VERSION 5.7 ;
  NOWIREEXTENSIONATPIN ON ;
  DIVIDERCHAR "/" ;
  BUSBITCHARS "[]" ;
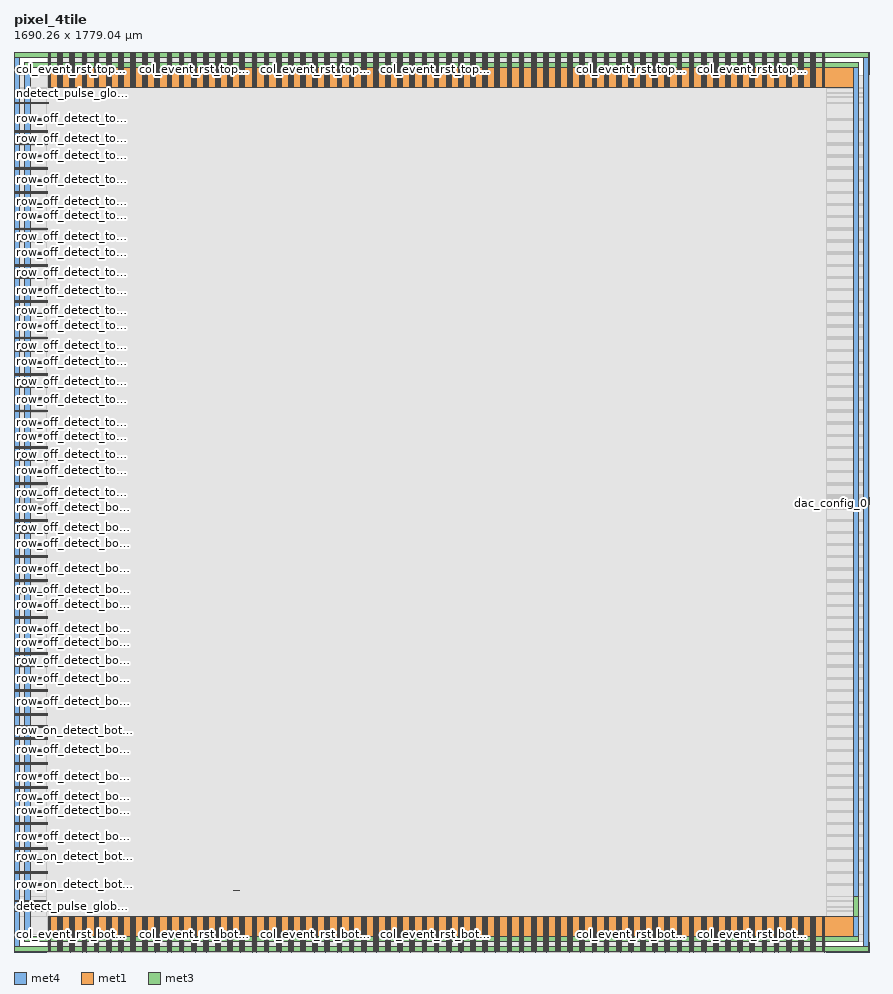
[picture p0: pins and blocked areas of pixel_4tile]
MACRO pixel_4tile
  CLASS BLOCK ;
  FOREIGN pixel_4tile ;
  ORIGIN 64.615 70.200 ;
  SIZE 1690.255 BY 1779.040 ;
  PIN array_col_top_right[5]
    ANTENNADIFFAREA 0.870000 ;
    PORT
      LAYER met4 ;
        RECT 1469.520 1638.440 1471.360 1708.840 ;
    END
  END array_col_top_right[5]
  PIN array_col_top_right[8]
    ANTENNADIFFAREA 0.870000 ;
    PORT
      LAYER met4 ;
        RECT 1438.020 1638.440 1439.860 1708.840 ;
    END
  END array_col_top_right[8]
  PIN array_col_top_right[9]
    ANTENNADIFFAREA 0.870000 ;
    PORT
      LAYER met4 ;
        RECT 1421.520 1638.440 1423.360 1708.840 ;
    END
  END array_col_top_right[9]
  PIN array_col_top_right[12]
    ANTENNADIFFAREA 0.870000 ;
    PORT
      LAYER met4 ;
        RECT 1390.020 1638.440 1391.860 1708.840 ;
    END
  END array_col_top_right[12]
  PIN array_col_top_right[13]
    ANTENNADIFFAREA 0.870000 ;
    PORT
      LAYER met4 ;
        RECT 1373.520 1638.440 1375.360 1708.840 ;
    END
  END array_col_top_right[13]
  PIN array_col_top_right[16]
    ANTENNADIFFAREA 0.870000 ;
    PORT
      LAYER met4 ;
        RECT 1342.020 1638.440 1343.860 1708.840 ;
    END
  END array_col_top_right[16]
  PIN array_col_top_right[26]
    ANTENNADIFFAREA 0.870000 ;
    PORT
      LAYER met4 ;
        RECT 1222.020 1638.440 1223.860 1708.840 ;
    END
  END array_col_top_right[26]
  PIN col_event_rst_top_right[40]
    ANTENNAGATEAREA 4.032000 ;
    PORT
      LAYER met4 ;
        RECT 1056.780 1638.440 1058.160 1708.840 ;
    END
  END col_event_rst_top_right[40]
  PIN col_event_rst_top_right[39]
    ANTENNAGATEAREA 4.032000 ;
    PORT
      LAYER met4 ;
        RECT 1059.220 1638.440 1060.600 1708.840 ;
    END
  END col_event_rst_top_right[39]
  PIN col_event_rst_top_right[38]
    ANTENNAGATEAREA 4.032000 ;
    PORT
      LAYER met4 ;
        RECT 1080.780 1638.440 1082.160 1708.840 ;
    END
  END col_event_rst_top_right[38]
  PIN col_event_rst_top_right[37]
    ANTENNAGATEAREA 4.032000 ;
    PORT
      LAYER met4 ;
        RECT 1083.220 1638.440 1084.600 1708.840 ;
    END
  END col_event_rst_top_right[37]
  PIN col_event_rst_top_right[36]
    ANTENNAGATEAREA 4.032000 ;
    PORT
      LAYER met4 ;
        RECT 1104.780 1638.440 1106.160 1708.840 ;
    END
  END col_event_rst_top_right[36]
  PIN col_event_rst_top_right[35]
    ANTENNAGATEAREA 4.032000 ;
    PORT
      LAYER met4 ;
        RECT 1107.220 1638.440 1108.600 1708.840 ;
    END
  END col_event_rst_top_right[35]
  PIN col_event_rst_top_right[34]
    ANTENNAGATEAREA 4.032000 ;
    PORT
      LAYER met4 ;
        RECT 1128.780 1638.440 1130.160 1708.840 ;
    END
  END col_event_rst_top_right[34]
  PIN col_event_rst_top_right[33]
    ANTENNAGATEAREA 4.032000 ;
    PORT
      LAYER met4 ;
        RECT 1131.220 1638.440 1132.600 1708.840 ;
    END
  END col_event_rst_top_right[33]
  PIN col_event_rst_top_right[27]
    ANTENNAGATEAREA 4.032000 ;
    PORT
      LAYER met4 ;
        RECT 1203.220 1638.440 1204.600 1708.840 ;
    END
  END col_event_rst_top_right[27]
  PIN col_event_rst_top_right[32]
    ANTENNAGATEAREA 4.032000 ;
    PORT
      LAYER met4 ;
        RECT 1152.780 1638.440 1154.160 1708.840 ;
    END
  END col_event_rst_top_right[32]
  PIN col_event_rst_top_right[26]
    ANTENNAGATEAREA 4.032000 ;
    PORT
      LAYER met4 ;
        RECT 1224.780 1638.440 1226.160 1708.840 ;
    END
  END col_event_rst_top_right[26]
  PIN col_event_rst_top_right[25]
    ANTENNAGATEAREA 4.032000 ;
    PORT
      LAYER met4 ;
        RECT 1227.220 1638.440 1228.600 1708.840 ;
    END
  END col_event_rst_top_right[25]
  PIN col_event_rst_top_right[24]
    ANTENNAGATEAREA 4.032000 ;
    PORT
      LAYER met4 ;
        RECT 1248.780 1638.440 1250.160 1708.840 ;
    END
  END col_event_rst_top_right[24]
  PIN col_event_rst_top_right[23]
    ANTENNAGATEAREA 4.032000 ;
    PORT
      LAYER met4 ;
        RECT 1251.220 1638.440 1252.600 1708.840 ;
    END
  END col_event_rst_top_right[23]
  PIN col_event_rst_top_right[22]
    ANTENNAGATEAREA 4.032000 ;
    PORT
      LAYER met4 ;
        RECT 1272.780 1638.440 1274.160 1708.840 ;
    END
  END col_event_rst_top_right[22]
  PIN col_event_rst_top_right[21]
    ANTENNAGATEAREA 4.032000 ;
    PORT
      LAYER met4 ;
        RECT 1275.220 1638.440 1276.600 1708.840 ;
    END
  END col_event_rst_top_right[21]
  PIN col_event_rst_top_right[20]
    ANTENNAGATEAREA 4.032000 ;
    PORT
      LAYER met4 ;
        RECT 1296.780 1638.440 1298.160 1708.840 ;
    END
  END col_event_rst_top_right[20]
  PIN col_event_rst_top_right[19]
    ANTENNAGATEAREA 4.032000 ;
    PORT
      LAYER met4 ;
        RECT 1299.220 1638.440 1300.600 1708.840 ;
    END
  END col_event_rst_top_right[19]
  PIN col_event_rst_top_right[18]
    ANTENNAGATEAREA 4.032000 ;
    PORT
      LAYER met4 ;
        RECT 1320.780 1638.440 1322.160 1708.840 ;
    END
  END col_event_rst_top_right[18]
  PIN col_event_rst_top_right[17]
    ANTENNAGATEAREA 4.032000 ;
    PORT
      LAYER met4 ;
        RECT 1323.220 1638.440 1324.600 1708.840 ;
    END
  END col_event_rst_top_right[17]
  PIN col_event_rst_top_right[16]
    ANTENNAGATEAREA 4.032000 ;
    PORT
      LAYER met4 ;
        RECT 1344.780 1638.440 1346.160 1708.840 ;
    END
  END col_event_rst_top_right[16]
  PIN col_event_rst_top_right[15]
    ANTENNAGATEAREA 4.032000 ;
    PORT
      LAYER met4 ;
        RECT 1347.220 1638.440 1348.600 1708.840 ;
    END
  END col_event_rst_top_right[15]
  PIN col_event_rst_top_right[14]
    ANTENNAGATEAREA 4.032000 ;
    PORT
      LAYER met4 ;
        RECT 1368.780 1638.440 1370.160 1708.840 ;
    END
  END col_event_rst_top_right[14]
  PIN col_event_rst_top_right[13]
    ANTENNAGATEAREA 4.032000 ;
    PORT
      LAYER met4 ;
        RECT 1371.220 1638.440 1372.600 1708.840 ;
    END
  END col_event_rst_top_right[13]
  PIN col_event_rst_top_right[12]
    ANTENNAGATEAREA 4.032000 ;
    PORT
      LAYER met4 ;
        RECT 1392.780 1638.440 1394.160 1708.840 ;
    END
  END col_event_rst_top_right[12]
  PIN col_event_rst_top_right[11]
    ANTENNAGATEAREA 4.032000 ;
    PORT
      LAYER met4 ;
        RECT 1395.220 1638.440 1396.600 1708.840 ;
    END
  END col_event_rst_top_right[11]
  PIN col_event_rst_top_right[10]
    ANTENNAGATEAREA 4.032000 ;
    PORT
      LAYER met4 ;
        RECT 1416.780 1638.440 1418.160 1708.840 ;
    END
  END col_event_rst_top_right[10]
  PIN col_event_rst_top_right[9]
    ANTENNAGATEAREA 4.032000 ;
    PORT
      LAYER met4 ;
        RECT 1419.220 1638.440 1420.600 1708.840 ;
    END
  END col_event_rst_top_right[9]
  PIN col_event_rst_top_right[8]
    ANTENNAGATEAREA 4.032000 ;
    PORT
      LAYER met4 ;
        RECT 1440.780 1638.440 1442.160 1708.840 ;
    END
  END col_event_rst_top_right[8]
  PIN col_event_rst_top_right[7]
    ANTENNAGATEAREA 4.032000 ;
    PORT
      LAYER met4 ;
        RECT 1443.220 1638.440 1444.600 1708.840 ;
    END
  END col_event_rst_top_right[7]
  PIN col_event_rst_top_right[6]
    ANTENNAGATEAREA 4.032000 ;
    PORT
      LAYER met4 ;
        RECT 1464.780 1638.440 1466.160 1708.840 ;
    END
  END col_event_rst_top_right[6]
  PIN col_event_rst_top_right[5]
    ANTENNAGATEAREA 4.032000 ;
    PORT
      LAYER met4 ;
        RECT 1467.220 1638.440 1468.600 1708.840 ;
    END
  END col_event_rst_top_right[5]
  PIN col_event_rst_top_right[4]
    ANTENNAGATEAREA 4.032000 ;
    PORT
      LAYER met4 ;
        RECT 1488.780 1638.440 1490.160 1708.840 ;
    END
  END col_event_rst_top_right[4]
  PIN col_event_rst_top_right[3]
    ANTENNAGATEAREA 4.032000 ;
    PORT
      LAYER met4 ;
        RECT 1491.220 1638.440 1492.600 1708.840 ;
    END
  END col_event_rst_top_right[3]
  PIN col_event_rst_top_right[2]
    ANTENNAGATEAREA 4.032000 ;
    PORT
      LAYER met4 ;
        RECT 1512.780 1638.440 1514.160 1708.840 ;
    END
  END col_event_rst_top_right[2]
  PIN col_event_rst_top_right[1]
    ANTENNAGATEAREA 4.032000 ;
    PORT
      LAYER met4 ;
        RECT 1515.220 1638.440 1516.600 1708.840 ;
    END
  END col_event_rst_top_right[1]
  PIN col_event_rst_top_right[0]
    ANTENNAGATEAREA 4.032000 ;
    PORT
      LAYER met4 ;
        RECT 1536.780 1638.440 1538.160 1708.840 ;
    END
  END col_event_rst_top_right[0]
  PIN col_event_rst_bot_right[63]
    ANTENNAGATEAREA 4.032000 ;
    PORT
      LAYER met4 ;
        RECT 771.220 -70.040 772.600 0.375 ;
    END
  END col_event_rst_bot_right[63]
  PIN col_event_rst_bot_right[62]
    ANTENNAGATEAREA 4.032000 ;
    PORT
      LAYER met4 ;
        RECT 792.780 -70.040 794.160 0.375 ;
    END
  END col_event_rst_bot_right[62]
  PIN col_event_rst_bot_right[61]
    ANTENNAGATEAREA 4.032000 ;
    PORT
      LAYER met4 ;
        RECT 795.220 -70.040 796.600 0.375 ;
    END
  END col_event_rst_bot_right[61]
  PIN col_event_rst_bot_right[60]
    ANTENNAGATEAREA 4.032000 ;
    PORT
      LAYER met4 ;
        RECT 817.250 -70.040 818.630 0.375 ;
    END
  END col_event_rst_bot_right[60]
  PIN col_event_rst_bot_right[59]
    ANTENNAGATEAREA 4.032000 ;
    PORT
      LAYER met4 ;
        RECT 819.220 -70.040 820.600 0.375 ;
    END
  END col_event_rst_bot_right[59]
  PIN col_event_rst_bot_right[58]
    ANTENNAGATEAREA 4.032000 ;
    PORT
      LAYER met4 ;
        RECT 840.780 -70.040 842.160 0.375 ;
    END
  END col_event_rst_bot_right[58]
  PIN col_event_rst_bot_right[57]
    ANTENNAGATEAREA 4.032000 ;
    PORT
      LAYER met4 ;
        RECT 843.220 -70.040 844.600 0.375 ;
    END
  END col_event_rst_bot_right[57]
  PIN col_event_rst_bot_right[56]
    ANTENNAGATEAREA 4.032000 ;
    PORT
      LAYER met4 ;
        RECT 864.780 -70.040 866.160 0.375 ;
    END
  END col_event_rst_bot_right[56]
  PIN col_event_rst_bot_right[55]
    ANTENNAGATEAREA 4.032000 ;
    PORT
      LAYER met4 ;
        RECT 867.220 -70.040 868.600 0.375 ;
    END
  END col_event_rst_bot_right[55]
  PIN col_event_rst_bot_right[54]
    ANTENNAGATEAREA 4.032000 ;
    PORT
      LAYER met4 ;
        RECT 888.780 -70.040 890.160 0.375 ;
    END
  END col_event_rst_bot_right[54]
  PIN col_event_rst_bot_right[53]
    ANTENNAGATEAREA 4.032000 ;
    PORT
      LAYER met4 ;
        RECT 891.220 -70.040 892.600 0.375 ;
    END
  END col_event_rst_bot_right[53]
  PIN col_event_rst_bot_right[52]
    ANTENNAGATEAREA 4.032000 ;
    PORT
      LAYER met4 ;
        RECT 912.780 -70.040 914.160 0.375 ;
    END
  END col_event_rst_bot_right[52]
  PIN col_event_rst_bot_right[51]
    ANTENNAGATEAREA 4.032000 ;
    PORT
      LAYER met4 ;
        RECT 915.220 -70.040 916.600 0.375 ;
    END
  END col_event_rst_bot_right[51]
  PIN col_event_rst_bot_right[50]
    ANTENNAGATEAREA 4.032000 ;
    PORT
      LAYER met4 ;
        RECT 936.780 -70.040 938.160 0.375 ;
    END
  END col_event_rst_bot_right[50]
  PIN col_event_rst_bot_right[49]
    ANTENNAGATEAREA 4.032000 ;
    PORT
      LAYER met4 ;
        RECT 939.220 -70.040 940.600 0.375 ;
    END
  END col_event_rst_bot_right[49]
  PIN col_event_rst_bot_right[48]
    ANTENNAGATEAREA 4.032000 ;
    PORT
      LAYER met4 ;
        RECT 960.780 -70.040 962.160 0.375 ;
    END
  END col_event_rst_bot_right[48]
  PIN col_event_rst_bot_right[47]
    ANTENNAGATEAREA 4.032000 ;
    PORT
      LAYER met4 ;
        RECT 963.220 -70.040 964.600 0.375 ;
    END
  END col_event_rst_bot_right[47]
  PIN col_event_rst_bot_right[46]
    ANTENNAGATEAREA 4.032000 ;
    PORT
      LAYER met4 ;
        RECT 984.780 -70.040 986.160 0.375 ;
    END
  END col_event_rst_bot_right[46]
  PIN col_event_rst_bot_right[45]
    ANTENNAGATEAREA 4.032000 ;
    PORT
      LAYER met4 ;
        RECT 987.220 -70.040 988.600 0.375 ;
    END
  END col_event_rst_bot_right[45]
  PIN col_event_rst_bot_right[44]
    ANTENNAGATEAREA 4.032000 ;
    PORT
      LAYER met4 ;
        RECT 1008.780 -70.040 1010.160 0.375 ;
    END
  END col_event_rst_bot_right[44]
  PIN col_event_rst_bot_right[43]
    ANTENNAGATEAREA 4.032000 ;
    PORT
      LAYER met4 ;
        RECT 1011.220 -70.040 1012.600 0.375 ;
    END
  END col_event_rst_bot_right[43]
  PIN col_event_rst_bot_right[42]
    ANTENNAGATEAREA 4.032000 ;
    PORT
      LAYER met4 ;
        RECT 1032.780 -70.040 1034.160 0.375 ;
    END
  END col_event_rst_bot_right[42]
  PIN col_event_rst_bot_right[41]
    ANTENNAGATEAREA 4.032000 ;
    PORT
      LAYER met4 ;
        RECT 1035.220 -70.040 1036.600 0.375 ;
    END
  END col_event_rst_bot_right[41]
  PIN col_event_rst_bot_right[40]
    ANTENNAGATEAREA 4.032000 ;
    PORT
      LAYER met4 ;
        RECT 1056.780 -70.040 1058.160 0.375 ;
    END
  END col_event_rst_bot_right[40]
  PIN col_event_rst_bot_right[39]
    ANTENNAGATEAREA 4.032000 ;
    PORT
      LAYER met4 ;
        RECT 1059.220 -70.040 1060.600 0.375 ;
    END
  END col_event_rst_bot_right[39]
  PIN col_event_rst_bot_right[38]
    ANTENNAGATEAREA 4.032000 ;
    PORT
      LAYER met4 ;
        RECT 1080.780 -70.040 1082.160 0.375 ;
    END
  END col_event_rst_bot_right[38]
  PIN col_event_rst_bot_right[37]
    ANTENNAGATEAREA 4.032000 ;
    PORT
      LAYER met4 ;
        RECT 1083.220 -70.040 1084.600 0.375 ;
    END
  END col_event_rst_bot_right[37]
  PIN col_event_rst_bot_right[36]
    ANTENNAGATEAREA 4.032000 ;
    PORT
      LAYER met4 ;
        RECT 1104.780 -70.040 1106.160 0.375 ;
    END
  END col_event_rst_bot_right[36]
  PIN col_event_rst_bot_right[35]
    ANTENNAGATEAREA 4.032000 ;
    PORT
      LAYER met4 ;
        RECT 1107.220 -70.040 1108.600 0.375 ;
    END
  END col_event_rst_bot_right[35]
  PIN col_event_rst_bot_right[34]
    ANTENNAGATEAREA 4.032000 ;
    PORT
      LAYER met4 ;
        RECT 1128.780 -70.040 1130.160 0.375 ;
    END
  END col_event_rst_bot_right[34]
  PIN col_event_rst_bot_right[33]
    ANTENNAGATEAREA 4.032000 ;
    PORT
      LAYER met4 ;
        RECT 1131.220 -70.040 1132.600 0.375 ;
    END
  END col_event_rst_bot_right[33]
  PIN col_event_rst_bot_right[32]
    ANTENNAGATEAREA 4.032000 ;
    PORT
      LAYER met4 ;
        RECT 1152.780 -70.040 1154.160 0.375 ;
    END
  END col_event_rst_bot_right[32]
  PIN col_event_rst_bot_right[31]
    ANTENNAGATEAREA 4.032000 ;
    PORT
      LAYER met4 ;
        RECT 1155.220 -70.040 1156.600 0.375 ;
    END
  END col_event_rst_bot_right[31]
  PIN col_event_rst_bot_right[30]
    ANTENNAGATEAREA 4.032000 ;
    PORT
      LAYER met4 ;
        RECT 1176.780 -70.040 1178.160 0.375 ;
    END
  END col_event_rst_bot_right[30]
  PIN col_event_rst_bot_right[29]
    ANTENNAGATEAREA 4.032000 ;
    PORT
      LAYER met4 ;
        RECT 1179.220 -70.040 1180.600 0.375 ;
    END
  END col_event_rst_bot_right[29]
  PIN col_event_rst_bot_right[28]
    ANTENNAGATEAREA 4.032000 ;
    PORT
      LAYER met4 ;
        RECT 1200.780 -70.040 1202.160 0.375 ;
    END
  END col_event_rst_bot_right[28]
  PIN col_event_rst_bot_right[27]
    ANTENNAGATEAREA 4.032000 ;
    PORT
      LAYER met4 ;
        RECT 1203.220 -70.040 1204.600 0.375 ;
    END
  END col_event_rst_bot_right[27]
  PIN col_event_rst_bot_right[26]
    ANTENNAGATEAREA 4.032000 ;
    PORT
      LAYER met4 ;
        RECT 1224.780 -70.040 1226.160 0.375 ;
    END
  END col_event_rst_bot_right[26]
  PIN col_event_rst_bot_right[25]
    ANTENNAGATEAREA 4.032000 ;
    PORT
      LAYER met4 ;
        RECT 1227.220 -70.040 1228.600 0.375 ;
    END
  END col_event_rst_bot_right[25]
  PIN col_event_rst_bot_right[24]
    ANTENNAGATEAREA 4.032000 ;
    PORT
      LAYER met4 ;
        RECT 1248.780 -70.040 1250.160 0.375 ;
    END
  END col_event_rst_bot_right[24]
  PIN col_event_rst_bot_right[23]
    ANTENNAGATEAREA 4.032000 ;
    PORT
      LAYER met4 ;
        RECT 1251.220 -70.040 1252.600 0.375 ;
    END
  END col_event_rst_bot_right[23]
  PIN col_event_rst_bot_right[22]
    ANTENNAGATEAREA 4.032000 ;
    PORT
      LAYER met4 ;
        RECT 1272.780 -70.040 1274.160 0.375 ;
    END
  END col_event_rst_bot_right[22]
  PIN col_event_rst_bot_right[21]
    ANTENNAGATEAREA 4.032000 ;
    PORT
      LAYER met4 ;
        RECT 1275.220 -70.040 1276.600 0.375 ;
    END
  END col_event_rst_bot_right[21]
  PIN col_event_rst_bot_right[20]
    ANTENNAGATEAREA 4.032000 ;
    PORT
      LAYER met4 ;
        RECT 1296.780 -70.040 1298.160 0.375 ;
    END
  END col_event_rst_bot_right[20]
  PIN col_event_rst_bot_right[19]
    ANTENNAGATEAREA 4.032000 ;
    PORT
      LAYER met4 ;
        RECT 1299.220 -70.040 1300.600 0.375 ;
    END
  END col_event_rst_bot_right[19]
  PIN col_event_rst_bot_right[18]
    ANTENNAGATEAREA 4.032000 ;
    PORT
      LAYER met4 ;
        RECT 1320.780 -70.040 1322.160 0.375 ;
    END
  END col_event_rst_bot_right[18]
  PIN col_event_rst_bot_right[17]
    ANTENNAGATEAREA 4.032000 ;
    PORT
      LAYER met4 ;
        RECT 1323.220 -70.040 1324.600 0.375 ;
    END
  END col_event_rst_bot_right[17]
  PIN col_event_rst_bot_right[16]
    ANTENNAGATEAREA 4.032000 ;
    PORT
      LAYER met4 ;
        RECT 1344.780 -70.040 1346.160 0.375 ;
    END
  END col_event_rst_bot_right[16]
  PIN col_event_rst_bot_right[15]
    ANTENNAGATEAREA 4.032000 ;
    PORT
      LAYER met4 ;
        RECT 1347.220 -70.040 1348.600 0.375 ;
    END
  END col_event_rst_bot_right[15]
  PIN col_event_rst_bot_right[14]
    ANTENNAGATEAREA 4.032000 ;
    PORT
      LAYER met4 ;
        RECT 1368.780 -70.040 1370.160 0.375 ;
    END
  END col_event_rst_bot_right[14]
  PIN col_event_rst_bot_right[13]
    ANTENNAGATEAREA 4.032000 ;
    PORT
      LAYER met4 ;
        RECT 1371.220 -70.040 1372.600 0.375 ;
    END
  END col_event_rst_bot_right[13]
  PIN col_event_rst_bot_right[12]
    ANTENNAGATEAREA 4.032000 ;
    PORT
      LAYER met4 ;
        RECT 1392.780 -70.040 1394.160 0.375 ;
    END
  END col_event_rst_bot_right[12]
  PIN col_event_rst_bot_right[11]
    ANTENNAGATEAREA 4.032000 ;
    PORT
      LAYER met4 ;
        RECT 1395.220 -70.040 1396.600 0.375 ;
    END
  END col_event_rst_bot_right[11]
  PIN col_event_rst_bot_right[10]
    ANTENNAGATEAREA 4.032000 ;
    PORT
      LAYER met4 ;
        RECT 1416.780 -70.040 1418.160 0.375 ;
    END
  END col_event_rst_bot_right[10]
  PIN col_event_rst_bot_right[9]
    ANTENNAGATEAREA 4.032000 ;
    PORT
      LAYER met4 ;
        RECT 1419.220 -70.040 1420.600 0.375 ;
    END
  END col_event_rst_bot_right[9]
  PIN col_event_rst_bot_right[8]
    ANTENNAGATEAREA 4.032000 ;
    PORT
      LAYER met4 ;
        RECT 1440.780 -70.040 1442.160 0.375 ;
    END
  END col_event_rst_bot_right[8]
  PIN col_event_rst_bot_right[7]
    ANTENNAGATEAREA 4.032000 ;
    PORT
      LAYER met4 ;
        RECT 1443.220 -70.040 1444.600 0.375 ;
    END
  END col_event_rst_bot_right[7]
  PIN col_event_rst_bot_right[6]
    ANTENNAGATEAREA 4.032000 ;
    PORT
      LAYER met4 ;
        RECT 1464.780 -70.040 1466.160 0.375 ;
    END
  END col_event_rst_bot_right[6]
  PIN col_event_rst_bot_right[5]
    ANTENNAGATEAREA 4.032000 ;
    PORT
      LAYER met4 ;
        RECT 1467.220 -70.040 1468.600 0.375 ;
    END
  END col_event_rst_bot_right[5]
  PIN col_event_rst_bot_right[4]
    ANTENNAGATEAREA 4.032000 ;
    PORT
      LAYER met4 ;
        RECT 1488.780 -70.040 1490.160 0.375 ;
    END
  END col_event_rst_bot_right[4]
  PIN col_event_rst_bot_right[3]
    ANTENNAGATEAREA 4.032000 ;
    PORT
      LAYER met4 ;
        RECT 1491.220 -70.040 1492.600 0.375 ;
    END
  END col_event_rst_bot_right[3]
  PIN col_event_rst_bot_right[2]
    ANTENNAGATEAREA 4.032000 ;
    PORT
      LAYER met4 ;
        RECT 1512.780 -70.040 1514.160 0.375 ;
    END
  END col_event_rst_bot_right[2]
  PIN col_event_rst_bot_right[1]
    ANTENNAGATEAREA 4.032000 ;
    PORT
      LAYER met4 ;
        RECT 1515.220 -70.040 1516.600 0.375 ;
    END
  END col_event_rst_bot_right[1]
  PIN col_event_rst_bot_right[0]
    ANTENNAGATEAREA 4.032000 ;
    PORT
      LAYER met4 ;
        RECT 1536.780 -70.040 1538.160 0.375 ;
    END
  END col_event_rst_bot_right[0]
  PIN col_event_rst_bot_left[63]
    ANTENNAGATEAREA 4.032000 ;
    PORT
      LAYER met4 ;
        RECT 3.220 -70.040 4.600 0.375 ;
    END
  END col_event_rst_bot_left[63]
  PIN col_event_rst_bot_left[62]
    ANTENNAGATEAREA 4.032000 ;
    PORT
      LAYER met4 ;
        RECT 24.780 -70.040 26.160 0.375 ;
    END
  END col_event_rst_bot_left[62]
  PIN col_event_rst_bot_left[61]
    ANTENNAGATEAREA 4.032000 ;
    PORT
      LAYER met4 ;
        RECT 27.220 -70.040 28.600 0.375 ;
    END
  END col_event_rst_bot_left[61]
  PIN col_event_rst_bot_left[60]
    ANTENNAGATEAREA 4.032000 ;
    PORT
      LAYER met4 ;
        RECT 48.780 -70.040 50.160 0.375 ;
    END
  END col_event_rst_bot_left[60]
  PIN col_event_rst_bot_left[59]
    ANTENNAGATEAREA 4.032000 ;
    PORT
      LAYER met4 ;
        RECT 51.220 -70.040 52.600 0.375 ;
    END
  END col_event_rst_bot_left[59]
  PIN col_event_rst_bot_left[58]
    ANTENNAGATEAREA 4.032000 ;
    PORT
      LAYER met4 ;
        RECT 72.780 -70.040 74.160 0.375 ;
    END
  END col_event_rst_bot_left[58]
  PIN col_event_rst_bot_left[57]
    ANTENNAGATEAREA 4.032000 ;
    PORT
      LAYER met4 ;
        RECT 75.220 -70.040 76.600 0.375 ;
    END
  END col_event_rst_bot_left[57]
  PIN col_event_rst_bot_left[56]
    ANTENNAGATEAREA 4.032000 ;
    PORT
      LAYER met4 ;
        RECT 96.780 -70.040 98.160 0.375 ;
    END
  END col_event_rst_bot_left[56]
  PIN col_event_rst_bot_left[55]
    ANTENNAGATEAREA 4.032000 ;
    PORT
      LAYER met4 ;
        RECT 99.220 -70.040 100.600 0.375 ;
    END
  END col_event_rst_bot_left[55]
  PIN col_event_rst_bot_left[54]
    ANTENNAGATEAREA 4.032000 ;
    PORT
      LAYER met4 ;
        RECT 120.780 -70.040 122.160 0.375 ;
    END
  END col_event_rst_bot_left[54]
  PIN col_event_rst_bot_left[53]
    ANTENNAGATEAREA 4.032000 ;
    PORT
      LAYER met4 ;
        RECT 123.220 -70.040 124.600 0.375 ;
    END
  END col_event_rst_bot_left[53]
  PIN col_event_rst_bot_left[52]
    ANTENNAGATEAREA 4.032000 ;
    PORT
      LAYER met4 ;
        RECT 144.780 -70.040 146.160 0.375 ;
    END
  END col_event_rst_bot_left[52]
  PIN col_event_rst_bot_left[51]
    ANTENNAGATEAREA 4.032000 ;
    PORT
      LAYER met4 ;
        RECT 147.220 -70.040 148.600 0.375 ;
    END
  END col_event_rst_bot_left[51]
  PIN col_event_rst_bot_left[50]
    ANTENNAGATEAREA 4.032000 ;
    PORT
      LAYER met4 ;
        RECT 168.780 -70.040 170.160 0.375 ;
    END
  END col_event_rst_bot_left[50]
  PIN col_event_rst_bot_left[49]
    ANTENNAGATEAREA 4.032000 ;
    PORT
      LAYER met4 ;
        RECT 171.220 -70.040 172.600 0.375 ;
    END
  END col_event_rst_bot_left[49]
  PIN col_event_rst_bot_left[48]
    ANTENNAGATEAREA 4.032000 ;
    PORT
      LAYER met4 ;
        RECT 192.780 -70.040 194.160 0.375 ;
    END
  END col_event_rst_bot_left[48]
  PIN col_event_rst_bot_left[47]
    ANTENNAGATEAREA 4.032000 ;
    PORT
      LAYER met4 ;
        RECT 195.220 -70.040 196.600 0.375 ;
    END
  END col_event_rst_bot_left[47]
  PIN col_event_rst_bot_left[46]
    ANTENNAGATEAREA 4.032000 ;
    PORT
      LAYER met4 ;
        RECT 216.780 -70.040 218.160 0.375 ;
    END
  END col_event_rst_bot_left[46]
  PIN col_event_rst_bot_left[45]
    ANTENNAGATEAREA 4.032000 ;
    PORT
      LAYER met4 ;
        RECT 219.220 -70.040 220.600 0.375 ;
    END
  END col_event_rst_bot_left[45]
  PIN col_event_rst_bot_left[44]
    ANTENNAGATEAREA 4.032000 ;
    PORT
      LAYER met4 ;
        RECT 240.780 -70.040 242.160 0.375 ;
    END
  END col_event_rst_bot_left[44]
  PIN col_event_rst_bot_left[43]
    ANTENNAGATEAREA 4.032000 ;
    PORT
      LAYER met4 ;
        RECT 243.220 -70.040 244.600 0.375 ;
    END
  END col_event_rst_bot_left[43]
  PIN col_event_rst_bot_left[42]
    ANTENNAGATEAREA 4.032000 ;
    PORT
      LAYER met4 ;
        RECT 264.780 -70.040 266.160 0.375 ;
    END
  END col_event_rst_bot_left[42]
  PIN col_event_rst_bot_left[41]
    ANTENNAGATEAREA 4.032000 ;
    PORT
      LAYER met4 ;
        RECT 267.220 -70.040 268.600 0.375 ;
    END
  END col_event_rst_bot_left[41]
  PIN col_event_rst_bot_left[40]
    ANTENNAGATEAREA 4.032000 ;
    PORT
      LAYER met4 ;
        RECT 288.780 -70.040 290.160 0.375 ;
    END
  END col_event_rst_bot_left[40]
  PIN col_event_rst_bot_left[39]
    ANTENNAGATEAREA 4.032000 ;
    PORT
      LAYER met4 ;
        RECT 291.220 -70.040 292.600 0.375 ;
    END
  END col_event_rst_bot_left[39]
  PIN col_event_rst_bot_left[38]
    ANTENNAGATEAREA 4.032000 ;
    PORT
      LAYER met4 ;
        RECT 312.780 -70.040 314.160 0.375 ;
    END
  END col_event_rst_bot_left[38]
  PIN col_event_rst_bot_left[37]
    ANTENNAGATEAREA 4.032000 ;
    PORT
      LAYER met4 ;
        RECT 315.220 -70.040 316.600 0.375 ;
    END
  END col_event_rst_bot_left[37]
  PIN col_event_rst_bot_left[36]
    ANTENNAGATEAREA 4.032000 ;
    PORT
      LAYER met4 ;
        RECT 336.780 -70.040 338.160 0.375 ;
    END
  END col_event_rst_bot_left[36]
  PIN col_event_rst_bot_left[35]
    ANTENNAGATEAREA 4.032000 ;
    PORT
      LAYER met4 ;
        RECT 339.220 -70.040 340.600 0.375 ;
    END
  END col_event_rst_bot_left[35]
  PIN col_event_rst_bot_left[34]
    ANTENNAGATEAREA 4.032000 ;
    PORT
      LAYER met4 ;
        RECT 360.780 -70.040 362.160 0.375 ;
    END
  END col_event_rst_bot_left[34]
  PIN col_event_rst_bot_left[33]
    ANTENNAGATEAREA 4.032000 ;
    PORT
      LAYER met4 ;
        RECT 363.220 -70.040 364.600 0.375 ;
    END
  END col_event_rst_bot_left[33]
  PIN col_event_rst_bot_left[32]
    ANTENNAGATEAREA 4.032000 ;
    PORT
      LAYER met4 ;
        RECT 384.780 -70.040 386.160 0.375 ;
    END
  END col_event_rst_bot_left[32]
  PIN col_event_rst_bot_left[31]
    ANTENNAGATEAREA 4.032000 ;
    PORT
      LAYER met4 ;
        RECT 387.220 -70.040 388.600 0.375 ;
    END
  END col_event_rst_bot_left[31]
  PIN col_event_rst_bot_left[30]
    ANTENNAGATEAREA 4.032000 ;
    PORT
      LAYER met4 ;
        RECT 408.780 -70.040 410.160 0.375 ;
    END
  END col_event_rst_bot_left[30]
  PIN col_event_rst_bot_left[29]
    ANTENNAGATEAREA 4.032000 ;
    PORT
      LAYER met4 ;
        RECT 411.220 -70.040 412.600 0.375 ;
    END
  END col_event_rst_bot_left[29]
  PIN col_event_rst_bot_left[28]
    ANTENNAGATEAREA 4.032000 ;
    PORT
      LAYER met4 ;
        RECT 432.780 -70.040 434.160 0.375 ;
    END
  END col_event_rst_bot_left[28]
  PIN col_event_rst_bot_left[27]
    ANTENNAGATEAREA 4.032000 ;
    PORT
      LAYER met4 ;
        RECT 435.220 -70.040 436.600 0.375 ;
    END
  END col_event_rst_bot_left[27]
  PIN col_event_rst_bot_left[26]
    ANTENNAGATEAREA 4.032000 ;
    PORT
      LAYER met4 ;
        RECT 456.780 -70.040 458.160 0.375 ;
    END
  END col_event_rst_bot_left[26]
  PIN col_event_rst_bot_left[25]
    ANTENNAGATEAREA 4.032000 ;
    PORT
      LAYER met4 ;
        RECT 459.220 -70.040 460.600 0.375 ;
    END
  END col_event_rst_bot_left[25]
  PIN col_event_rst_bot_left[24]
    ANTENNAGATEAREA 4.032000 ;
    PORT
      LAYER met4 ;
        RECT 480.780 -70.040 482.160 0.375 ;
    END
  END col_event_rst_bot_left[24]
  PIN col_event_rst_bot_left[23]
    ANTENNAGATEAREA 4.032000 ;
    PORT
      LAYER met4 ;
        RECT 483.220 -70.040 484.600 0.375 ;
    END
  END col_event_rst_bot_left[23]
  PIN col_event_rst_bot_left[22]
    ANTENNAGATEAREA 4.032000 ;
    PORT
      LAYER met4 ;
        RECT 504.780 -70.040 506.160 0.375 ;
    END
  END col_event_rst_bot_left[22]
  PIN col_event_rst_bot_left[21]
    ANTENNAGATEAREA 4.032000 ;
    PORT
      LAYER met4 ;
        RECT 507.220 -70.040 508.600 0.375 ;
    END
  END col_event_rst_bot_left[21]
  PIN col_event_rst_bot_left[20]
    ANTENNAGATEAREA 4.032000 ;
    PORT
      LAYER met4 ;
        RECT 528.780 -70.040 530.160 0.375 ;
    END
  END col_event_rst_bot_left[20]
  PIN col_event_rst_bot_left[19]
    ANTENNAGATEAREA 4.032000 ;
    PORT
      LAYER met4 ;
        RECT 531.220 -70.040 532.600 0.375 ;
    END
  END col_event_rst_bot_left[19]
  PIN col_event_rst_bot_left[18]
    ANTENNAGATEAREA 4.032000 ;
    PORT
      LAYER met4 ;
        RECT 552.780 -70.040 554.160 0.375 ;
    END
  END col_event_rst_bot_left[18]
  PIN col_event_rst_bot_left[17]
    ANTENNAGATEAREA 4.032000 ;
    PORT
      LAYER met4 ;
        RECT 555.220 -70.040 556.600 0.375 ;
    END
  END col_event_rst_bot_left[17]
  PIN col_event_rst_bot_left[16]
    ANTENNAGATEAREA 4.032000 ;
    PORT
      LAYER met4 ;
        RECT 576.780 -70.040 578.160 0.375 ;
    END
  END col_event_rst_bot_left[16]
  PIN col_event_rst_bot_left[15]
    ANTENNAGATEAREA 4.032000 ;
    PORT
      LAYER met4 ;
        RECT 579.220 -70.040 580.600 0.375 ;
    END
  END col_event_rst_bot_left[15]
  PIN col_event_rst_bot_left[14]
    ANTENNAGATEAREA 4.032000 ;
    PORT
      LAYER met4 ;
        RECT 600.780 -70.040 602.160 0.375 ;
    END
  END col_event_rst_bot_left[14]
  PIN col_event_rst_bot_left[13]
    ANTENNAGATEAREA 4.032000 ;
    PORT
      LAYER met4 ;
        RECT 603.220 -70.040 604.600 0.375 ;
    END
  END col_event_rst_bot_left[13]
  PIN col_event_rst_bot_left[12]
    ANTENNAGATEAREA 4.032000 ;
    PORT
      LAYER met4 ;
        RECT 624.780 -70.040 626.160 0.375 ;
    END
  END col_event_rst_bot_left[12]
  PIN col_event_rst_bot_left[11]
    ANTENNAGATEAREA 4.032000 ;
    PORT
      LAYER met4 ;
        RECT 627.220 -70.040 628.600 0.375 ;
    END
  END col_event_rst_bot_left[11]
  PIN col_event_rst_bot_left[10]
    ANTENNAGATEAREA 4.032000 ;
    PORT
      LAYER met4 ;
        RECT 648.780 -70.040 650.160 0.375 ;
    END
  END col_event_rst_bot_left[10]
  PIN col_event_rst_bot_left[9]
    ANTENNAGATEAREA 4.032000 ;
    PORT
      LAYER met4 ;
        RECT 651.220 -70.040 652.600 0.375 ;
    END
  END col_event_rst_bot_left[9]
  PIN col_event_rst_bot_left[8]
    ANTENNAGATEAREA 4.032000 ;
    PORT
      LAYER met4 ;
        RECT 672.780 -70.040 674.160 0.375 ;
    END
  END col_event_rst_bot_left[8]
  PIN col_event_rst_bot_left[7]
    ANTENNAGATEAREA 4.032000 ;
    PORT
      LAYER met4 ;
        RECT 675.220 -70.040 676.600 0.375 ;
    END
  END col_event_rst_bot_left[7]
  PIN col_event_rst_bot_left[6]
    ANTENNAGATEAREA 4.032000 ;
    PORT
      LAYER met4 ;
        RECT 696.780 -70.040 698.160 0.375 ;
    END
  END col_event_rst_bot_left[6]
  PIN col_event_rst_bot_left[5]
    ANTENNAGATEAREA 4.032000 ;
    PORT
      LAYER met4 ;
        RECT 699.220 -70.040 700.600 0.375 ;
    END
  END col_event_rst_bot_left[5]
  PIN col_event_rst_bot_left[4]
    ANTENNAGATEAREA 4.032000 ;
    PORT
      LAYER met4 ;
        RECT 720.780 -70.040 722.160 0.375 ;
    END
  END col_event_rst_bot_left[4]
  PIN col_event_rst_bot_left[3]
    ANTENNAGATEAREA 4.032000 ;
    PORT
      LAYER met4 ;
        RECT 723.220 -70.040 724.600 0.375 ;
    END
  END col_event_rst_bot_left[3]
  PIN col_event_rst_bot_left[2]
    ANTENNAGATEAREA 4.032000 ;
    PORT
      LAYER met4 ;
        RECT 744.780 -70.040 746.160 0.375 ;
    END
  END col_event_rst_bot_left[2]
  PIN col_event_rst_bot_left[1]
    ANTENNAGATEAREA 4.032000 ;
    PORT
      LAYER met4 ;
        RECT 747.220 -70.040 748.600 0.375 ;
    END
  END col_event_rst_bot_left[1]
  PIN col_event_rst_bot_left[0]
    ANTENNAGATEAREA 4.032000 ;
    PORT
      LAYER met4 ;
        RECT 768.780 -70.040 770.160 0.375 ;
    END
  END col_event_rst_bot_left[0]
  PIN vssa1
    ANTENNADIFFAREA 30668.416016 ;
    PORT
      LAYER met4 ;
        RECT -42.925 -50.000 -32.925 1688.440 ;
    END
    PORT
      LAYER met4 ;
        RECT 1595.000 -50.000 1605.000 1688.440 ;
    END
    PORT
      LAYER met1 ;
        RECT 2.690 1638.070 1605.000 1688.440 ;
    END
    PORT
      LAYER met1 ;
        RECT 2.690 -50.000 1605.000 0.370 ;
    END
    PORT
      LAYER met3 ;
        RECT 1539.250 1638.075 1542.950 1638.375 ;
    END
    PORT
      LAYER met3 ;
        RECT -42.925 1678.440 1605.000 1688.440 ;
    END
    PORT
      LAYER met3 ;
        RECT -42.925 -50.000 1605.000 -40.000 ;
    END
    PORT
      LAYER met3 ;
        RECT 1595.000 0.065 1605.000 40.065 ;
    END
  END vssa1
  PIN vdda1
    ANTENNAGATEAREA 1024.000000 ;
    ANTENNADIFFAREA 37975.105469 ;
    PORT
      LAYER met4 ;
        RECT -62.925 -70.000 -52.925 1708.440 ;
    END
    PORT
      LAYER met4 ;
        RECT 1615.000 -70.000 1625.000 1708.440 ;
    END
    PORT
      LAYER met4 ;
        RECT 368.795 50.390 380.585 52.050 ;
    END
    PORT
      LAYER met3 ;
        RECT -62.925 -70.000 1625.000 -60.000 ;
    END
    PORT
      LAYER met3 ;
        RECT -62.925 1698.440 1625.000 1708.440 ;
    END
  END vdda1
  PIN array_col_top_left[10]
    ANTENNADIFFAREA 0.870000 ;
    PORT
      LAYER met4 ;
        RECT 646.020 1638.440 647.860 1708.840 ;
    END
  END array_col_top_left[10]
  PIN array_col_top_left[14]
    ANTENNADIFFAREA 0.870000 ;
    PORT
      LAYER met4 ;
        RECT 598.020 1638.440 599.860 1708.840 ;
    END
  END array_col_top_left[14]
  PIN array_col_bot_left[55]
    ANTENNADIFFAREA 0.870000 ;
    PORT
      LAYER met4 ;
        RECT 101.520 -70.040 103.360 0.375 ;
    END
  END array_col_bot_left[55]
  PIN array_col_bot_left[42]
    ANTENNADIFFAREA 0.870000 ;
    PORT
      LAYER met4 ;
        RECT 262.020 -70.040 263.860 0.375 ;
    END
  END array_col_bot_left[42]
  PIN array_col_bot_right[14]
    ANTENNADIFFAREA 0.870000 ;
    PORT
      LAYER met4 ;
        RECT 1366.020 -70.040 1367.860 0.375 ;
    END
  END array_col_bot_right[14]
  PIN array_col_bot_left[41]
    ANTENNADIFFAREA 0.870000 ;
    PORT
      LAYER met4 ;
        RECT 269.520 -70.040 271.360 0.375 ;
    END
  END array_col_bot_left[41]
  PIN array_col_bot_left[40]
    ANTENNADIFFAREA 0.870000 ;
    PORT
      LAYER met4 ;
        RECT 286.020 -70.040 287.860 0.375 ;
    END
  END array_col_bot_left[40]
  PIN array_col_top_right[22]
    ANTENNADIFFAREA 0.870000 ;
    PORT
      LAYER met4 ;
        RECT 1270.365 1638.440 1272.205 1708.840 ;
    END
  END array_col_top_right[22]
  PIN array_col_bot_left[20]
    ANTENNADIFFAREA 0.870000 ;
    PORT
      LAYER met4 ;
        RECT 526.020 -70.040 527.860 0.375 ;
    END
  END array_col_bot_left[20]
  PIN array_col_top_left[20]
    ANTENNADIFFAREA 0.870000 ;
    PORT
      LAYER met4 ;
        RECT 526.020 1638.440 527.860 1708.840 ;
    END
  END array_col_top_left[20]
  PIN array_col_bot_left[23]
    ANTENNADIFFAREA 0.870000 ;
    PORT
      LAYER met4 ;
        RECT 485.520 -70.040 487.360 0.375 ;
    END
  END array_col_bot_left[23]
  PIN array_col_top_right[20]
    ANTENNADIFFAREA 0.870000 ;
    PORT
      LAYER met4 ;
        RECT 1294.020 1638.440 1295.860 1708.840 ;
    END
  END array_col_top_right[20]
  PIN col_event_rst_top_right[62]
    ANTENNAGATEAREA 4.032000 ;
    PORT
      LAYER met4 ;
        RECT 792.780 1638.440 794.160 1708.840 ;
    END
  END col_event_rst_top_right[62]
  PIN col_event_rst_top_left[2]
    ANTENNAGATEAREA 4.032000 ;
    PORT
      LAYER met4 ;
        RECT 744.780 1638.440 746.160 1708.840 ;
    END
  END col_event_rst_top_left[2]
  PIN array_col_bot_right[3]
    ANTENNADIFFAREA 0.870000 ;
    PORT
      LAYER met4 ;
        RECT 1493.520 -70.040 1495.360 0.375 ;
    END
  END array_col_bot_right[3]
  PIN array_col_bot_right[15]
    ANTENNADIFFAREA 0.870000 ;
    PORT
      LAYER met4 ;
        RECT 1349.520 -70.040 1351.360 0.375 ;
    END
  END array_col_bot_right[15]
  PIN array_col_bot_right[17]
    ANTENNADIFFAREA 0.870000 ;
    PORT
      LAYER met4 ;
        RECT 1325.520 -70.040 1327.360 0.375 ;
    END
  END array_col_bot_right[17]
  PIN array_col_bot_right[9]
    ANTENNADIFFAREA 0.870000 ;
    PORT
      LAYER met4 ;
        RECT 1421.520 -70.040 1423.360 0.375 ;
    END
  END array_col_bot_right[9]
  PIN array_col_top_right[15]
    ANTENNADIFFAREA 0.870000 ;
    PORT
      LAYER met4 ;
        RECT 1349.520 1638.440 1351.360 1708.840 ;
    END
  END array_col_top_right[15]
  PIN array_col_top_right[14]
    ANTENNADIFFAREA 0.870000 ;
    PORT
      LAYER met4 ;
        RECT 1366.020 1638.440 1367.860 1708.840 ;
    END
  END array_col_top_right[14]
  PIN array_col_top_right[7]
    ANTENNADIFFAREA 0.870000 ;
    PORT
      LAYER met4 ;
        RECT 1445.520 1638.440 1447.360 1708.840 ;
    END
  END array_col_top_right[7]
  PIN array_col_top_right[6]
    ANTENNADIFFAREA 0.870000 ;
    PORT
      LAYER met4 ;
        RECT 1462.020 1638.440 1463.860 1708.840 ;
    END
  END array_col_top_right[6]
  PIN col_event_rst_top_left[32]
    ANTENNAGATEAREA 4.032000 ;
    PORT
      LAYER met4 ;
        RECT 384.780 1638.440 386.160 1708.840 ;
    END
  END col_event_rst_top_left[32]
  PIN col_event_rst_top_left[28]
    ANTENNAGATEAREA 4.032000 ;
    PORT
      LAYER met4 ;
        RECT 432.780 1638.440 434.160 1708.840 ;
    END
  END col_event_rst_top_left[28]
  PIN col_event_rst_top_left[19]
    ANTENNAGATEAREA 4.032000 ;
    PORT
      LAYER met4 ;
        RECT 531.220 1638.440 532.600 1708.840 ;
    END
  END col_event_rst_top_left[19]
  PIN col_event_rst_top_left[16]
    ANTENNAGATEAREA 4.032000 ;
    PORT
      LAYER met4 ;
        RECT 576.780 1638.440 578.160 1708.840 ;
    END
  END col_event_rst_top_left[16]
  PIN array_col_bot_left[31]
    ANTENNADIFFAREA 0.870000 ;
    PORT
      LAYER met4 ;
        RECT 389.520 -70.040 391.360 0.375 ;
    END
  END array_col_bot_left[31]
  PIN col_event_rst_top_left[53]
    ANTENNAGATEAREA 4.032000 ;
    PORT
      LAYER met4 ;
        RECT 123.220 1638.440 124.600 1708.840 ;
    END
  END col_event_rst_top_left[53]
  PIN col_event_rst_top_left[60]
    ANTENNAGATEAREA 4.032000 ;
    PORT
      LAYER met4 ;
        RECT 48.780 1638.440 50.160 1708.840 ;
    END
  END col_event_rst_top_left[60]
  PIN col_event_rst_top_left[50]
    ANTENNAGATEAREA 4.032000 ;
    PORT
      LAYER met4 ;
        RECT 168.780 1638.440 170.160 1708.840 ;
    END
  END col_event_rst_top_left[50]
  PIN col_event_rst_top_left[12]
    ANTENNAGATEAREA 4.032000 ;
    PORT
      LAYER met4 ;
        RECT 624.780 1638.440 626.160 1708.840 ;
    END
  END col_event_rst_top_left[12]
  PIN array_col_bot_right[23]
    ANTENNADIFFAREA 0.870000 ;
    PORT
      LAYER met4 ;
        RECT 1253.520 -70.040 1255.360 0.375 ;
    END
  END array_col_bot_right[23]
  PIN array_col_top_left[35]
    ANTENNADIFFAREA 0.870000 ;
    PORT
      LAYER met4 ;
        RECT 341.520 1638.440 343.360 1708.840 ;
    END
  END array_col_top_left[35]
  PIN col_event_rst_top_left[6]
    ANTENNAGATEAREA 4.032000 ;
    PORT
      LAYER met4 ;
        RECT 696.780 1638.440 698.160 1708.840 ;
    END
  END col_event_rst_top_left[6]
  PIN col_event_rst_top_right[44]
    ANTENNAGATEAREA 4.032000 ;
    PORT
      LAYER met4 ;
        RECT 1008.780 1638.440 1010.160 1708.840 ;
    END
  END col_event_rst_top_right[44]
  PIN array_col_bot_left[43]
    ANTENNADIFFAREA 0.870000 ;
    PORT
      LAYER met4 ;
        RECT 245.520 -70.040 247.360 0.375 ;
    END
  END array_col_bot_left[43]
  PIN col_event_rst_top_right[47]
    ANTENNAGATEAREA 4.032000 ;
    PORT
      LAYER met4 ;
        RECT 963.220 1638.440 964.600 1708.840 ;
    END
  END col_event_rst_top_right[47]
  PIN col_event_rst_top_right[51]
    ANTENNAGATEAREA 4.032000 ;
    PORT
      LAYER met4 ;
        RECT 915.220 1638.440 916.600 1708.840 ;
    END
  END col_event_rst_top_right[51]
  PIN col_event_rst_top_right[55]
    ANTENNAGATEAREA 4.032000 ;
    PORT
      LAYER met4 ;
        RECT 867.220 1638.440 868.600 1708.840 ;
    END
  END col_event_rst_top_right[55]
  PIN col_event_rst_top_left[61]
    ANTENNAGATEAREA 4.032000 ;
    PORT
      LAYER met4 ;
        RECT 27.220 1638.440 28.600 1708.840 ;
    END
  END col_event_rst_top_left[61]
  PIN array_col_top_right[27]
    ANTENNADIFFAREA 0.870000 ;
    PORT
      LAYER met4 ;
        RECT 1205.520 1638.440 1207.360 1708.840 ;
    END
  END array_col_top_right[27]
  PIN col_event_rst_top_left[36]
    ANTENNAGATEAREA 4.032000 ;
    PORT
      LAYER met4 ;
        RECT 336.780 1638.440 338.160 1708.840 ;
    END
  END col_event_rst_top_left[36]
  PIN array_col_top_left[13]
    ANTENNADIFFAREA 0.870000 ;
    PORT
      LAYER met4 ;
        RECT 605.520 1638.440 607.360 1708.840 ;
    END
  END array_col_top_left[13]
  PIN array_col_top_left[34]
    ANTENNADIFFAREA 0.870000 ;
    PORT
      LAYER met4 ;
        RECT 358.020 1638.440 359.860 1708.840 ;
    END
  END array_col_top_left[34]
  PIN array_col_top_right[31]
    ANTENNADIFFAREA 0.870000 ;
    PORT
      LAYER met4 ;
        RECT 1157.520 1638.440 1159.360 1708.840 ;
    END
  END array_col_top_right[31]
  PIN array_col_top_right[30]
    ANTENNADIFFAREA 0.870000 ;
    PORT
      LAYER met4 ;
        RECT 1174.020 1638.440 1175.860 1708.840 ;
    END
  END array_col_top_right[30]
  PIN array_col_top_left[26]
    ANTENNADIFFAREA 0.870000 ;
    PORT
      LAYER met4 ;
        RECT 454.020 1638.440 455.860 1708.840 ;
    END
  END array_col_top_left[26]
  PIN array_col_top_left[8]
    ANTENNADIFFAREA 0.870000 ;
    PORT
      LAYER met4 ;
        RECT 670.020 1638.440 671.860 1708.840 ;
    END
  END array_col_top_left[8]
  PIN array_col_top_left[38]
    ANTENNADIFFAREA 0.870000 ;
    PORT
      LAYER met4 ;
        RECT 310.020 1638.440 311.860 1708.840 ;
    END
  END array_col_top_left[38]
  PIN array_col_top_left[39]
    ANTENNADIFFAREA 0.870000 ;
    PORT
      LAYER met4 ;
        RECT 293.520 1638.440 295.360 1708.840 ;
    END
  END array_col_top_left[39]
  PIN array_col_top_left[40]
    ANTENNADIFFAREA 0.870000 ;
    PORT
      LAYER met4 ;
        RECT 286.020 1638.440 287.860 1708.840 ;
    END
  END array_col_top_left[40]
  PIN array_col_top_left[2]
    ANTENNADIFFAREA 0.870000 ;
    PORT
      LAYER met4 ;
        RECT 742.020 1638.440 743.860 1708.840 ;
    END
  END array_col_top_left[2]
  PIN array_col_top_left[41]
    ANTENNADIFFAREA 0.870000 ;
    PORT
      LAYER met4 ;
        RECT 269.520 1638.440 271.360 1708.840 ;
    END
  END array_col_top_left[41]
  PIN array_col_top_left[42]
    ANTENNADIFFAREA 0.870000 ;
    PORT
      LAYER met4 ;
        RECT 262.020 1638.440 263.860 1708.840 ;
    END
  END array_col_top_left[42]
  PIN array_col_top_left[43]
    ANTENNADIFFAREA 0.870000 ;
    PORT
      LAYER met4 ;
        RECT 245.520 1638.440 247.360 1708.840 ;
    END
  END array_col_top_left[43]
  PIN array_col_top_left[44]
    ANTENNADIFFAREA 0.870000 ;
    PORT
      LAYER met4 ;
        RECT 238.020 1638.440 239.860 1708.840 ;
    END
  END array_col_top_left[44]
  PIN array_col_top_left[28]
    ANTENNADIFFAREA 0.870000 ;
    PORT
      LAYER met4 ;
        RECT 430.020 1638.440 431.860 1708.840 ;
    END
  END array_col_top_left[28]
  PIN array_col_top_left[45]
    ANTENNADIFFAREA 0.870000 ;
    PORT
      LAYER met4 ;
        RECT 221.520 1638.440 223.360 1708.840 ;
    END
  END array_col_top_left[45]
  PIN array_col_top_left[46]
    ANTENNADIFFAREA 0.870000 ;
    PORT
      LAYER met4 ;
        RECT 214.020 1638.440 215.860 1708.840 ;
    END
  END array_col_top_left[46]
  PIN array_col_top_left[12]
    ANTENNADIFFAREA 0.870000 ;
    PORT
      LAYER met4 ;
        RECT 622.020 1638.440 623.860 1708.840 ;
    END
  END array_col_top_left[12]
  PIN col_event_rst_top_right[60]
    ANTENNAGATEAREA 4.032000 ;
    PORT
      LAYER met4 ;
        RECT 816.780 1638.440 818.160 1708.840 ;
    END
  END col_event_rst_top_right[60]
  PIN array_col_top_left[47]
    ANTENNADIFFAREA 0.870000 ;
    PORT
      LAYER met4 ;
        RECT 197.520 1638.440 199.360 1708.840 ;
    END
  END array_col_top_left[47]
  PIN array_col_top_left[33]
    ANTENNADIFFAREA 0.870000 ;
    PORT
      LAYER met4 ;
        RECT 365.520 1638.440 367.360 1708.840 ;
    END
  END array_col_top_left[33]
  PIN array_col_bot_left[60]
    ANTENNADIFFAREA 0.870000 ;
    PORT
      LAYER met4 ;
        RECT 46.020 -70.040 47.860 0.375 ;
    END
  END array_col_bot_left[60]
  PIN array_col_top_left[48]
    ANTENNADIFFAREA 0.870000 ;
    PORT
      LAYER met4 ;
        RECT 190.020 1638.440 191.860 1708.840 ;
    END
  END array_col_top_left[48]
  PIN array_col_top_left[9]
    ANTENNADIFFAREA 0.870000 ;
    PORT
      LAYER met4 ;
        RECT 653.520 1638.440 655.360 1708.840 ;
    END
  END array_col_top_left[9]
  PIN array_col_top_right[25]
    ANTENNADIFFAREA 0.870000 ;
    PORT
      LAYER met4 ;
        RECT 1229.520 1638.440 1231.360 1708.840 ;
    END
  END array_col_top_right[25]
  PIN array_col_top_right[24]
    ANTENNADIFFAREA 0.870000 ;
    PORT
      LAYER met4 ;
        RECT 1246.020 1638.440 1247.860 1708.840 ;
    END
  END array_col_top_right[24]
  PIN array_col_top_right[23]
    ANTENNADIFFAREA 0.870000 ;
    PORT
      LAYER met4 ;
        RECT 1253.520 1638.440 1255.360 1708.840 ;
    END
  END array_col_top_right[23]
  PIN array_col_top_left[27]
    ANTENNADIFFAREA 0.870000 ;
    PORT
      LAYER met4 ;
        RECT 437.520 1638.440 439.360 1708.840 ;
    END
  END array_col_top_left[27]
  PIN array_col_top_right[21]
    ANTENNADIFFAREA 0.870000 ;
    PORT
      LAYER met4 ;
        RECT 1277.520 1638.440 1279.360 1708.840 ;
    END
  END array_col_top_right[21]
  PIN array_col_top_left[49]
    ANTENNADIFFAREA 0.870000 ;
    PORT
      LAYER met4 ;
        RECT 173.520 1638.440 175.360 1708.840 ;
    END
  END array_col_top_left[49]
  PIN array_col_bot_left[21]
    ANTENNADIFFAREA 0.870000 ;
    PORT
      LAYER met4 ;
        RECT 509.520 -70.040 511.360 0.375 ;
    END
  END array_col_bot_left[21]
  PIN array_col_top_right[29]
    ANTENNADIFFAREA 0.870000 ;
    PORT
      LAYER met4 ;
        RECT 1181.520 1638.440 1183.360 1708.840 ;
    END
  END array_col_top_right[29]
  PIN col_event_rst_top_left[5]
    ANTENNAGATEAREA 4.032000 ;
    PORT
      LAYER met4 ;
        RECT 699.220 1638.440 700.600 1708.840 ;
    END
  END col_event_rst_top_left[5]
  PIN array_col_bot_left[22]
    ANTENNADIFFAREA 0.870000 ;
    PORT
      LAYER met4 ;
        RECT 502.020 -70.040 503.860 0.375 ;
    END
  END array_col_bot_left[22]
  PIN array_col_top_left[50]
    ANTENNADIFFAREA 0.870000 ;
    PORT
      LAYER met4 ;
        RECT 166.020 1638.440 167.860 1708.840 ;
    END
  END array_col_top_left[50]
  PIN array_col_bot_left[16]
    ANTENNADIFFAREA 0.870000 ;
    PORT
      LAYER met4 ;
        RECT 574.020 -70.040 575.860 0.375 ;
    END
  END array_col_bot_left[16]
  PIN col_event_rst_top_left[1]
    ANTENNAGATEAREA 4.032000 ;
    PORT
      LAYER met4 ;
        RECT 747.220 1638.440 748.600 1708.840 ;
    END
  END col_event_rst_top_left[1]
  PIN array_col_bot_left[45]
    ANTENNADIFFAREA 0.870000 ;
    PORT
      LAYER met4 ;
        RECT 221.520 -70.040 223.360 0.375 ;
    END
  END array_col_bot_left[45]
  PIN array_col_top_left[18]
    ANTENNADIFFAREA 0.870000 ;
    PORT
      LAYER met4 ;
        RECT 550.020 1638.440 551.860 1708.840 ;
    END
  END array_col_top_left[18]
  PIN array_col_top_right[19]
    ANTENNADIFFAREA 0.870000 ;
    PORT
      LAYER met4 ;
        RECT 1301.520 1638.440 1303.360 1708.840 ;
    END
  END array_col_top_right[19]
  PIN array_col_top_right[18]
    ANTENNADIFFAREA 0.870000 ;
    PORT
      LAYER met4 ;
        RECT 1318.020 1638.440 1319.860 1708.840 ;
    END
  END array_col_top_right[18]
  PIN array_col_top_right[11]
    ANTENNADIFFAREA 0.870000 ;
    PORT
      LAYER met4 ;
        RECT 1397.520 1638.440 1399.360 1708.840 ;
    END
  END array_col_top_right[11]
  PIN array_col_top_right[10]
    ANTENNADIFFAREA 0.870000 ;
    PORT
      LAYER met4 ;
        RECT 1414.020 1638.440 1415.860 1708.840 ;
    END
  END array_col_top_right[10]
  PIN col_event_rst_top_left[41]
    ANTENNAGATEAREA 4.032000 ;
    PORT
      LAYER met4 ;
        RECT 267.220 1638.440 268.600 1708.840 ;
    END
  END col_event_rst_top_left[41]
  PIN col_event_rst_top_left[38]
    ANTENNAGATEAREA 4.032000 ;
    PORT
      LAYER met4 ;
        RECT 312.780 1638.440 314.160 1708.840 ;
    END
  END col_event_rst_top_left[38]
  PIN col_event_rst_top_left[34]
    ANTENNAGATEAREA 4.032000 ;
    PORT
      LAYER met4 ;
        RECT 360.780 1638.440 362.160 1708.840 ;
    END
  END col_event_rst_top_left[34]
  PIN col_event_rst_top_left[27]
    ANTENNAGATEAREA 4.032000 ;
    PORT
      LAYER met4 ;
        RECT 435.220 1638.440 436.600 1708.840 ;
    END
  END col_event_rst_top_left[27]
  PIN col_event_rst_top_left[21]
    ANTENNAGATEAREA 4.032000 ;
    PORT
      LAYER met4 ;
        RECT 507.220 1638.440 508.600 1708.840 ;
    END
  END col_event_rst_top_left[21]
  PIN col_event_rst_top_left[15]
    ANTENNAGATEAREA 4.032000 ;
    PORT
      LAYER met4 ;
        RECT 579.220 1638.440 580.600 1708.840 ;
    END
  END col_event_rst_top_left[15]
  PIN array_col_bot_right[16]
    ANTENNADIFFAREA 0.870000 ;
    PORT
      LAYER met4 ;
        RECT 1342.020 -70.040 1343.860 0.375 ;
    END
  END array_col_bot_right[16]
  PIN array_col_bot_left[32]
    ANTENNADIFFAREA 0.870000 ;
    PORT
      LAYER met4 ;
        RECT 382.020 -70.040 383.860 0.375 ;
    END
  END array_col_bot_left[32]
  PIN array_col_bot_left[7]
    ANTENNADIFFAREA 0.870000 ;
    PORT
      LAYER met4 ;
        RECT 677.520 -70.040 679.360 0.375 ;
    END
  END array_col_bot_left[7]
  PIN col_event_rst_top_left[10]
    ANTENNAGATEAREA 4.032000 ;
    PORT
      LAYER met4 ;
        RECT 648.780 1638.440 650.160 1708.840 ;
    END
  END col_event_rst_top_left[10]
  PIN col_event_rst_top_left[9]
    ANTENNAGATEAREA 4.032000 ;
    PORT
      LAYER met4 ;
        RECT 651.220 1638.440 652.600 1708.840 ;
    END
  END col_event_rst_top_left[9]
  PIN col_event_rst_top_left[20]
    ANTENNAGATEAREA 4.032000 ;
    PORT
      LAYER met4 ;
        RECT 528.780 1638.440 530.160 1708.840 ;
    END
  END col_event_rst_top_left[20]
  PIN array_col_bot_right[27]
    ANTENNADIFFAREA 0.870000 ;
    PORT
      LAYER met4 ;
        RECT 1205.520 -70.040 1207.360 0.375 ;
    END
  END array_col_bot_right[27]
  PIN array_col_bot_right[26]
    ANTENNADIFFAREA 0.870000 ;
    PORT
      LAYER met4 ;
        RECT 1222.020 -70.040 1223.860 0.375 ;
    END
  END array_col_bot_right[26]
  PIN col_event_rst_top_right[43]
    ANTENNAGATEAREA 4.032000 ;
    PORT
      LAYER met4 ;
        RECT 1011.220 1638.440 1012.600 1708.840 ;
    END
  END col_event_rst_top_right[43]
  PIN col_event_rst_top_right[48]
    ANTENNAGATEAREA 4.032000 ;
    PORT
      LAYER met4 ;
        RECT 960.780 1638.440 962.160 1708.840 ;
    END
  END col_event_rst_top_right[48]
  PIN col_event_rst_top_right[52]
    ANTENNAGATEAREA 4.032000 ;
    PORT
      LAYER met4 ;
        RECT 912.780 1638.440 914.160 1708.840 ;
    END
  END col_event_rst_top_right[52]
  PIN col_event_rst_top_right[56]
    ANTENNAGATEAREA 4.032000 ;
    PORT
      LAYER met4 ;
        RECT 864.780 1638.440 866.160 1708.840 ;
    END
  END col_event_rst_top_right[56]
  PIN col_event_rst_top_right[59]
    ANTENNAGATEAREA 4.032000 ;
    PORT
      LAYER met4 ;
        RECT 819.220 1638.440 820.600 1708.840 ;
    END
  END col_event_rst_top_right[59]
  PIN array_col_top_right[38]
    ANTENNADIFFAREA 0.870000 ;
    PORT
      LAYER met4 ;
        RECT 1078.020 1638.440 1079.860 1708.840 ;
    END
  END array_col_top_right[38]
  PIN col_event_rst_top_left[48]
    ANTENNAGATEAREA 4.032000 ;
    PORT
      LAYER met4 ;
        RECT 192.780 1638.440 194.160 1708.840 ;
    END
  END col_event_rst_top_left[48]
  PIN array_col_top_left[51]
    ANTENNADIFFAREA 0.870000 ;
    PORT
      LAYER met4 ;
        RECT 149.520 1638.440 151.360 1708.840 ;
    END
  END array_col_top_left[51]
  PIN array_col_top_right[3]
    ANTENNADIFFAREA 0.870000 ;
    PORT
      LAYER met4 ;
        RECT 1493.520 1638.440 1495.360 1708.840 ;
    END
  END array_col_top_right[3]
  PIN array_col_bot_right[11]
    ANTENNADIFFAREA 0.870000 ;
    PORT
      LAYER met4 ;
        RECT 1397.520 -70.040 1399.360 0.375 ;
    END
  END array_col_bot_right[11]
  PIN array_col_top_left[52]
    ANTENNADIFFAREA 0.870000 ;
    PORT
      LAYER met4 ;
        RECT 142.020 1638.440 143.860 1708.840 ;
    END
  END array_col_top_left[52]
  PIN array_col_top_left[53]
    ANTENNADIFFAREA 0.870000 ;
    PORT
      LAYER met4 ;
        RECT 125.520 1638.440 127.360 1708.840 ;
    END
  END array_col_top_left[53]
  PIN col_event_rst_top_left[24]
    ANTENNAGATEAREA 4.032000 ;
    PORT
      LAYER met4 ;
        RECT 480.780 1638.440 482.160 1708.840 ;
    END
  END col_event_rst_top_left[24]
  PIN array_col_top_left[54]
    ANTENNADIFFAREA 0.870000 ;
    PORT
      LAYER met4 ;
        RECT 118.020 1638.440 119.860 1708.840 ;
    END
  END array_col_top_left[54]
  PIN array_col_top_left[55]
    ANTENNADIFFAREA 0.870000 ;
    PORT
      LAYER met4 ;
        RECT 101.520 1638.440 103.360 1708.840 ;
    END
  END array_col_top_left[55]
  PIN array_col_bot_left[0]
    ANTENNADIFFAREA 0.870000 ;
    PORT
      LAYER met4 ;
        RECT 766.020 -70.040 767.860 0.375 ;
    END
  END array_col_bot_left[0]
  PIN array_col_top_left[56]
    ANTENNADIFFAREA 0.870000 ;
    PORT
      LAYER met4 ;
        RECT 94.020 1638.440 95.860 1708.840 ;
    END
  END array_col_top_left[56]
  PIN array_col_top_left[57]
    ANTENNADIFFAREA 0.870000 ;
    PORT
      LAYER met4 ;
        RECT 77.520 1638.440 79.360 1708.840 ;
    END
  END array_col_top_left[57]
  PIN array_col_top_left[58]
    ANTENNADIFFAREA 0.870000 ;
    PORT
      LAYER met4 ;
        RECT 70.020 1638.440 71.860 1708.840 ;
    END
  END array_col_top_left[58]
  PIN array_col_top_left[59]
    ANTENNADIFFAREA 0.870000 ;
    PORT
      LAYER met4 ;
        RECT 53.520 1638.440 55.360 1708.840 ;
    END
  END array_col_top_left[59]
  PIN array_col_top_left[60]
    ANTENNADIFFAREA 0.870000 ;
    PORT
      LAYER met4 ;
        RECT 46.020 1638.440 47.860 1708.840 ;
    END
  END array_col_top_left[60]
  PIN array_col_top_left[61]
    ANTENNADIFFAREA 0.870000 ;
    PORT
      LAYER met4 ;
        RECT 29.520 1638.440 31.360 1708.840 ;
    END
  END array_col_top_left[61]
  PIN array_col_top_left[62]
    ANTENNADIFFAREA 0.870000 ;
    PORT
      LAYER met4 ;
        RECT 22.020 1638.440 23.860 1708.840 ;
    END
  END array_col_top_left[62]
  PIN col_event_rst_top_right[63]
    ANTENNAGATEAREA 4.032000 ;
    PORT
      LAYER met4 ;
        RECT 771.220 1638.440 772.600 1708.840 ;
    END
  END col_event_rst_top_right[63]
  PIN col_event_rst_top_left[3]
    ANTENNAGATEAREA 4.032000 ;
    PORT
      LAYER met4 ;
        RECT 723.220 1638.440 724.600 1708.840 ;
    END
  END col_event_rst_top_left[3]
  PIN array_col_bot_right[2]
    ANTENNADIFFAREA 0.870000 ;
    PORT
      LAYER met4 ;
        RECT 1510.020 -70.040 1511.860 0.375 ;
    END
  END array_col_bot_right[2]
  PIN col_event_rst_top_left[7]
    ANTENNAGATEAREA 4.032000 ;
    PORT
      LAYER met4 ;
        RECT 675.220 1638.440 676.600 1708.840 ;
    END
  END col_event_rst_top_left[7]
  PIN array_col_top_left[24]
    ANTENNADIFFAREA 0.870000 ;
    PORT
      LAYER met4 ;
        RECT 478.020 1638.440 479.860 1708.840 ;
    END
  END array_col_top_left[24]
  PIN array_col_bot_right[18]
    ANTENNADIFFAREA 0.870000 ;
    PORT
      LAYER met4 ;
        RECT 1318.020 -70.040 1319.860 0.375 ;
    END
  END array_col_bot_right[18]
  PIN array_col_top_right[33]
    ANTENNADIFFAREA 0.870000 ;
    PORT
      LAYER met4 ;
        RECT 1133.520 1638.440 1135.360 1708.840 ;
    END
  END array_col_top_right[33]
  PIN array_col_top_left[15]
    ANTENNADIFFAREA 0.870000 ;
    PORT
      LAYER met4 ;
        RECT 581.520 1638.440 583.360 1708.840 ;
    END
  END array_col_top_left[15]
  PIN array_col_top_left[16]
    ANTENNADIFFAREA 0.870000 ;
    PORT
      LAYER met4 ;
        RECT 574.020 1638.440 575.860 1708.840 ;
    END
  END array_col_top_left[16]
  PIN col_event_rst_top_left[46]
    ANTENNAGATEAREA 4.032000 ;
    PORT
      LAYER met4 ;
        RECT 216.780 1638.440 218.160 1708.840 ;
    END
  END col_event_rst_top_left[46]
  PIN array_col_bot_left[44]
    ANTENNADIFFAREA 0.870000 ;
    PORT
      LAYER met4 ;
        RECT 238.020 -70.040 239.860 0.375 ;
    END
  END array_col_bot_left[44]
  PIN array_col_top_right[61]
    ANTENNADIFFAREA 0.870000 ;
    PORT
      LAYER met4 ;
        RECT 797.520 1638.440 799.360 1708.840 ;
    END
  END array_col_top_right[61]
  PIN array_col_top_right[60]
    ANTENNADIFFAREA 0.870000 ;
    PORT
      LAYER met4 ;
        RECT 814.020 1638.440 815.860 1708.840 ;
    END
  END array_col_top_right[60]
  PIN array_col_top_left[31]
    ANTENNADIFFAREA 0.870000 ;
    PORT
      LAYER met4 ;
        RECT 389.520 1638.440 391.360 1708.840 ;
    END
  END array_col_top_left[31]
  PIN col_event_rst_top_right[61]
    ANTENNAGATEAREA 4.032000 ;
    PORT
      LAYER met4 ;
        RECT 795.220 1638.440 796.600 1708.840 ;
    END
  END col_event_rst_top_right[61]
  PIN col_event_rst_top_left[57]
    ANTENNAGATEAREA 4.032000 ;
    PORT
      LAYER met4 ;
        RECT 75.220 1638.440 76.600 1708.840 ;
    END
  END col_event_rst_top_left[57]
  PIN array_col_bot_right[4]
    ANTENNADIFFAREA 0.870000 ;
    PORT
      LAYER met4 ;
        RECT 1486.020 -70.040 1487.860 0.375 ;
    END
  END array_col_bot_right[4]
  PIN col_event_rst_top_left[51]
    ANTENNAGATEAREA 4.032000 ;
    PORT
      LAYER met4 ;
        RECT 147.220 1638.440 148.600 1708.840 ;
    END
  END col_event_rst_top_left[51]
  PIN col_event_rst_top_left[49]
    ANTENNAGATEAREA 4.032000 ;
    PORT
      LAYER met4 ;
        RECT 171.220 1638.440 172.600 1708.840 ;
    END
  END col_event_rst_top_left[49]
  PIN array_col_top_right[28]
    ANTENNADIFFAREA 0.870000 ;
    PORT
      LAYER met4 ;
        RECT 1198.020 1638.440 1199.860 1708.840 ;
    END
  END array_col_top_right[28]
  PIN array_col_top_left[36]
    ANTENNADIFFAREA 0.870000 ;
    PORT
      LAYER met4 ;
        RECT 334.020 1638.440 335.860 1708.840 ;
    END
  END array_col_top_left[36]
  PIN array_col_bot_right[6]
    ANTENNADIFFAREA 0.870000 ;
    PORT
      LAYER met4 ;
        RECT 1462.020 -70.040 1463.860 0.375 ;
    END
  END array_col_bot_right[6]
  PIN array_col_bot_right[22]
    ANTENNADIFFAREA 0.870000 ;
    PORT
      LAYER met4 ;
        RECT 1270.020 -70.040 1271.860 0.375 ;
    END
  END array_col_bot_right[22]
  PIN array_col_bot_right[55]
    ANTENNADIFFAREA 0.870000 ;
    PORT
      LAYER met4 ;
        RECT 869.520 -70.040 871.360 0.375 ;
    END
  END array_col_bot_right[55]
  PIN array_col_top_right[37]
    ANTENNADIFFAREA 0.870000 ;
    PORT
      LAYER met4 ;
        RECT 1085.520 1638.440 1087.360 1708.840 ;
    END
  END array_col_top_right[37]
  PIN array_col_bot_right[10]
    ANTENNADIFFAREA 0.870000 ;
    PORT
      LAYER met4 ;
        RECT 1414.020 -70.040 1415.860 0.375 ;
    END
  END array_col_bot_right[10]
  PIN array_col_top_left[1]
    ANTENNADIFFAREA 0.870000 ;
    PORT
      LAYER met4 ;
        RECT 749.520 1638.440 751.360 1708.840 ;
    END
  END array_col_top_left[1]
  PIN array_col_top_left[22]
    ANTENNADIFFAREA 0.870000 ;
    PORT
      LAYER met4 ;
        RECT 502.020 1638.440 503.860 1708.840 ;
    END
  END array_col_top_left[22]
  PIN array_col_top_right[58]
    ANTENNADIFFAREA 0.870000 ;
    PORT
      LAYER met4 ;
        RECT 838.020 1638.440 839.860 1708.840 ;
    END
  END array_col_top_right[58]
  PIN array_col_top_right[57]
    ANTENNADIFFAREA 0.870000 ;
    PORT
      LAYER met4 ;
        RECT 845.520 1638.440 847.360 1708.840 ;
    END
  END array_col_top_right[57]
  PIN array_col_top_right[54]
    ANTENNADIFFAREA 0.870000 ;
    PORT
      LAYER met4 ;
        RECT 886.020 1638.440 887.860 1708.840 ;
    END
  END array_col_top_right[54]
  PIN array_col_top_right[51]
    ANTENNADIFFAREA 0.870000 ;
    PORT
      LAYER met4 ;
        RECT 917.520 1638.440 919.360 1708.840 ;
    END
  END array_col_top_right[51]
  PIN array_col_top_right[50]
    ANTENNADIFFAREA 0.870000 ;
    PORT
      LAYER met4 ;
        RECT 934.020 1638.440 935.860 1708.840 ;
    END
  END array_col_top_right[50]
  PIN array_col_top_right[49]
    ANTENNADIFFAREA 0.870000 ;
    PORT
      LAYER met4 ;
        RECT 941.520 1638.440 943.360 1708.840 ;
    END
  END array_col_top_right[49]
  PIN array_col_top_right[48]
    ANTENNADIFFAREA 0.870000 ;
    PORT
      LAYER met4 ;
        RECT 958.020 1638.440 959.860 1708.840 ;
    END
  END array_col_top_right[48]
  PIN array_col_top_right[45]
    ANTENNADIFFAREA 0.870000 ;
    PORT
      LAYER met4 ;
        RECT 989.520 1638.440 991.360 1708.840 ;
    END
  END array_col_top_right[45]
  PIN array_col_top_right[42]
    ANTENNADIFFAREA 0.870000 ;
    PORT
      LAYER met4 ;
        RECT 1030.020 1638.440 1031.860 1708.840 ;
    END
  END array_col_top_right[42]
  PIN array_col_top_right[41]
    ANTENNADIFFAREA 0.870000 ;
    PORT
      LAYER met4 ;
        RECT 1037.520 1638.440 1039.360 1708.840 ;
    END
  END array_col_top_right[41]
  PIN array_col_top_left[3]
    ANTENNADIFFAREA 0.870000 ;
    PORT
      LAYER met4 ;
        RECT 725.520 1638.440 727.360 1708.840 ;
    END
  END array_col_top_left[3]
  PIN array_col_top_right[39]
    ANTENNADIFFAREA 0.870000 ;
    PORT
      LAYER met4 ;
        RECT 1061.520 1638.440 1063.360 1708.840 ;
    END
  END array_col_top_right[39]
  PIN col_event_rst_top_left[0]
    ANTENNAGATEAREA 4.032000 ;
    PORT
      LAYER met4 ;
        RECT 768.780 1638.440 770.160 1708.840 ;
    END
  END col_event_rst_top_left[0]
  PIN col_event_rst_top_left[4]
    ANTENNAGATEAREA 4.032000 ;
    PORT
      LAYER met4 ;
        RECT 720.780 1638.440 722.160 1708.840 ;
    END
  END col_event_rst_top_left[4]
  PIN col_event_rst_top_left[8]
    ANTENNAGATEAREA 4.032000 ;
    PORT
      LAYER met4 ;
        RECT 672.780 1638.440 674.160 1708.840 ;
    END
  END col_event_rst_top_left[8]
  PIN array_col_top_left[23]
    ANTENNADIFFAREA 0.870000 ;
    PORT
      LAYER met4 ;
        RECT 485.520 1638.440 487.360 1708.840 ;
    END
  END array_col_top_left[23]
  PIN array_col_bot_right[19]
    ANTENNADIFFAREA 0.870000 ;
    PORT
      LAYER met4 ;
        RECT 1301.520 -70.040 1303.360 0.375 ;
    END
  END array_col_bot_right[19]
  PIN array_col_top_left[17]
    ANTENNADIFFAREA 0.870000 ;
    PORT
      LAYER met4 ;
        RECT 557.520 1638.440 559.360 1708.840 ;
    END
  END array_col_top_left[17]
  PIN array_col_top_right[35]
    ANTENNADIFFAREA 0.870000 ;
    PORT
      LAYER met4 ;
        RECT 1109.520 1638.440 1111.360 1708.840 ;
    END
  END array_col_top_right[35]
  PIN array_col_top_right[34]
    ANTENNADIFFAREA 0.870000 ;
    PORT
      LAYER met4 ;
        RECT 1126.020 1638.440 1127.860 1708.840 ;
    END
  END array_col_top_right[34]
  PIN array_col_bot_right[1]
    ANTENNADIFFAREA 0.870000 ;
    PORT
      LAYER met4 ;
        RECT 1517.520 -70.040 1519.360 0.375 ;
    END
  END array_col_bot_right[1]
  PIN array_col_top_left[32]
    ANTENNADIFFAREA 0.870000 ;
    PORT
      LAYER met4 ;
        RECT 382.020 1638.440 383.860 1708.840 ;
    END
  END array_col_top_left[32]
  PIN array_col_top_left[6]
    ANTENNADIFFAREA 0.870000 ;
    PORT
      LAYER met4 ;
        RECT 694.020 1638.440 695.860 1708.840 ;
    END
  END array_col_top_left[6]
  PIN array_col_top_left[29]
    ANTENNADIFFAREA 0.870000 ;
    PORT
      LAYER met4 ;
        RECT 413.520 1638.440 415.360 1708.840 ;
    END
  END array_col_top_left[29]
  PIN array_col_top_right[63]
    ANTENNADIFFAREA 0.870000 ;
    PORT
      LAYER met4 ;
        RECT 773.520 1638.440 775.360 1708.840 ;
    END
  END array_col_top_right[63]
  PIN array_col_top_right[62]
    ANTENNADIFFAREA 0.870000 ;
    PORT
      LAYER met4 ;
        RECT 790.020 1638.440 791.860 1708.840 ;
    END
  END array_col_top_right[62]
  PIN array_col_top_left[11]
    ANTENNADIFFAREA 0.870000 ;
    PORT
      LAYER met4 ;
        RECT 629.520 1638.440 631.360 1708.840 ;
    END
  END array_col_top_left[11]
  PIN col_event_rst_top_right[58]
    ANTENNAGATEAREA 4.032000 ;
    PORT
      LAYER met4 ;
        RECT 840.780 1638.440 842.160 1708.840 ;
    END
  END col_event_rst_top_right[58]
  PIN col_event_rst_top_left[56]
    ANTENNAGATEAREA 4.032000 ;
    PORT
      LAYER met4 ;
        RECT 96.780 1638.440 98.160 1708.840 ;
    END
  END col_event_rst_top_left[56]
  PIN col_event_rst_top_left[45]
    ANTENNAGATEAREA 4.032000 ;
    PORT
      LAYER met4 ;
        RECT 219.220 1638.440 220.600 1708.840 ;
    END
  END col_event_rst_top_left[45]
  PIN array_col_bot_right[62]
    ANTENNADIFFAREA 0.870000 ;
    PORT
      LAYER met4 ;
        RECT 790.020 -70.040 791.860 0.375 ;
    END
  END array_col_bot_right[62]
  PIN array_col_bot_right[59]
    ANTENNADIFFAREA 0.870000 ;
    PORT
      LAYER met4 ;
        RECT 821.520 -70.040 823.360 0.375 ;
    END
  END array_col_bot_right[59]
  PIN array_col_bot_right[0]
    ANTENNADIFFAREA 0.870000 ;
    PORT
      LAYER met4 ;
        RECT 1534.020 -70.040 1535.860 0.375 ;
    END
  END array_col_bot_right[0]
  PIN array_col_bot_right[58]
    ANTENNADIFFAREA 0.870000 ;
    PORT
      LAYER met4 ;
        RECT 838.020 -70.040 839.860 0.375 ;
    END
  END array_col_bot_right[58]
  PIN array_col_bot_right[54]
    ANTENNADIFFAREA 0.870000 ;
    PORT
      LAYER met4 ;
        RECT 886.020 -70.040 887.860 0.375 ;
    END
  END array_col_bot_right[54]
  PIN array_col_top_left[5]
    ANTENNADIFFAREA 0.870000 ;
    PORT
      LAYER met4 ;
        RECT 701.520 1638.440 703.360 1708.840 ;
    END
  END array_col_top_left[5]
  PIN array_col_top_right[59]
    ANTENNADIFFAREA 0.870000 ;
    PORT
      LAYER met4 ;
        RECT 821.520 1638.440 823.360 1708.840 ;
    END
  END array_col_top_right[59]
  PIN array_col_top_right[56]
    ANTENNADIFFAREA 0.870000 ;
    PORT
      LAYER met4 ;
        RECT 862.020 1638.440 863.860 1708.840 ;
    END
  END array_col_top_right[56]
  PIN array_col_top_right[55]
    ANTENNADIFFAREA 0.870000 ;
    PORT
      LAYER met4 ;
        RECT 869.520 1638.440 871.360 1708.840 ;
    END
  END array_col_top_right[55]
  PIN array_col_top_right[53]
    ANTENNADIFFAREA 0.870000 ;
    PORT
      LAYER met4 ;
        RECT 893.520 1638.440 895.360 1708.840 ;
    END
  END array_col_top_right[53]
  PIN array_col_top_right[52]
    ANTENNADIFFAREA 0.870000 ;
    PORT
      LAYER met4 ;
        RECT 910.020 1638.440 911.860 1708.840 ;
    END
  END array_col_top_right[52]
  PIN array_col_top_left[4]
    ANTENNADIFFAREA 0.870000 ;
    PORT
      LAYER met4 ;
        RECT 718.020 1638.440 719.860 1708.840 ;
    END
  END array_col_top_left[4]
  PIN array_col_top_right[47]
    ANTENNADIFFAREA 0.870000 ;
    PORT
      LAYER met4 ;
        RECT 965.520 1638.440 967.360 1708.840 ;
    END
  END array_col_top_right[47]
  PIN array_col_top_right[46]
    ANTENNADIFFAREA 0.870000 ;
    PORT
      LAYER met4 ;
        RECT 982.020 1638.440 983.860 1708.840 ;
    END
  END array_col_top_right[46]
  PIN array_col_top_right[44]
    ANTENNADIFFAREA 0.870000 ;
    PORT
      LAYER met4 ;
        RECT 1006.020 1638.440 1007.860 1708.840 ;
    END
  END array_col_top_right[44]
  PIN array_col_top_right[43]
    ANTENNADIFFAREA 0.870000 ;
    PORT
      LAYER met4 ;
        RECT 1013.520 1638.440 1015.360 1708.840 ;
    END
  END array_col_top_right[43]
  PIN array_col_top_right[40]
    ANTENNADIFFAREA 0.870000 ;
    PORT
      LAYER met4 ;
        RECT 1054.020 1638.440 1055.860 1708.840 ;
    END
  END array_col_top_right[40]
  PIN array_col_top_right[36]
    ANTENNADIFFAREA 0.870000 ;
    PORT
      LAYER met4 ;
        RECT 1102.020 1638.440 1103.860 1708.840 ;
    END
  END array_col_top_right[36]
  PIN array_col_top_left[19]
    ANTENNADIFFAREA 0.870000 ;
    PORT
      LAYER met4 ;
        RECT 533.520 1638.440 535.360 1708.840 ;
    END
  END array_col_top_left[19]
  PIN array_col_bot_left[62]
    ANTENNADIFFAREA 0.870000 ;
    PORT
      LAYER met4 ;
        RECT 22.020 -70.040 23.860 0.375 ;
    END
  END array_col_bot_left[62]
  PIN array_col_bot_left[15]
    ANTENNADIFFAREA 0.870000 ;
    PORT
      LAYER met4 ;
        RECT 581.520 -70.040 583.360 0.375 ;
    END
  END array_col_bot_left[15]
  PIN array_col_bot_left[14]
    ANTENNADIFFAREA 0.870000 ;
    PORT
      LAYER met4 ;
        RECT 598.020 -70.040 599.860 0.375 ;
    END
  END array_col_bot_left[14]
  PIN array_col_bot_left[5]
    ANTENNADIFFAREA 0.870000 ;
    PORT
      LAYER met4 ;
        RECT 701.520 -70.040 703.360 0.375 ;
    END
  END array_col_bot_left[5]
  PIN col_event_rst_top_left[47]
    ANTENNAGATEAREA 4.032000 ;
    PORT
      LAYER met4 ;
        RECT 195.220 1638.440 196.600 1708.840 ;
    END
  END col_event_rst_top_left[47]
  PIN array_col_top_left[25]
    ANTENNADIFFAREA 0.870000 ;
    PORT
      LAYER met4 ;
        RECT 461.520 1638.440 463.360 1708.840 ;
    END
  END array_col_top_left[25]
  PIN array_col_bot_left[4]
    ANTENNADIFFAREA 0.870000 ;
    PORT
      LAYER met4 ;
        RECT 718.020 -70.040 719.860 0.375 ;
    END
  END array_col_bot_left[4]
  PIN array_col_bot_right[13]
    ANTENNADIFFAREA 0.870000 ;
    PORT
      LAYER met4 ;
        RECT 1373.520 -70.040 1375.360 0.375 ;
    END
  END array_col_bot_right[13]
  PIN array_col_top_right[1]
    ANTENNADIFFAREA 0.870000 ;
    PORT
      LAYER met4 ;
        RECT 1517.520 1638.440 1519.360 1708.840 ;
    END
  END array_col_top_right[1]
  PIN array_col_top_right[0]
    ANTENNADIFFAREA 0.870000 ;
    PORT
      LAYER met4 ;
        RECT 1534.020 1638.440 1535.860 1708.840 ;
    END
  END array_col_top_right[0]
  PIN array_col_bot_right[61]
    ANTENNADIFFAREA 0.870000 ;
    PORT
      LAYER met4 ;
        RECT 797.520 -70.040 799.360 0.375 ;
    END
  END array_col_bot_right[61]
  PIN col_event_rst_top_left[29]
    ANTENNAGATEAREA 4.032000 ;
    PORT
      LAYER met4 ;
        RECT 411.220 1638.440 412.600 1708.840 ;
    END
  END col_event_rst_top_left[29]
  PIN col_event_rst_top_left[25]
    ANTENNAGATEAREA 4.032000 ;
    PORT
      LAYER met4 ;
        RECT 459.220 1638.440 460.600 1708.840 ;
    END
  END col_event_rst_top_left[25]
  PIN col_event_rst_top_left[23]
    ANTENNAGATEAREA 4.032000 ;
    PORT
      LAYER met4 ;
        RECT 483.220 1638.440 484.600 1708.840 ;
    END
  END col_event_rst_top_left[23]
  PIN col_event_rst_top_left[18]
    ANTENNAGATEAREA 4.032000 ;
    PORT
      LAYER met4 ;
        RECT 552.780 1638.440 554.160 1708.840 ;
    END
  END col_event_rst_top_left[18]
  PIN col_event_rst_top_left[17]
    ANTENNAGATEAREA 4.032000 ;
    PORT
      LAYER met4 ;
        RECT 555.220 1638.440 556.600 1708.840 ;
    END
  END col_event_rst_top_left[17]
  PIN col_event_rst_top_left[14]
    ANTENNAGATEAREA 4.032000 ;
    PORT
      LAYER met4 ;
        RECT 600.780 1638.440 602.160 1708.840 ;
    END
  END col_event_rst_top_left[14]
  PIN array_col_bot_left[30]
    ANTENNADIFFAREA 0.870000 ;
    PORT
      LAYER met4 ;
        RECT 406.020 -70.040 407.860 0.375 ;
    END
  END array_col_bot_left[30]
  PIN array_col_bot_left[33]
    ANTENNADIFFAREA 0.870000 ;
    PORT
      LAYER met4 ;
        RECT 365.520 -70.040 367.360 0.375 ;
    END
  END array_col_bot_left[33]
  PIN array_col_top_left[21]
    ANTENNADIFFAREA 0.870000 ;
    PORT
      LAYER met4 ;
        RECT 509.520 1638.440 511.360 1708.840 ;
    END
  END array_col_top_left[21]
  PIN array_col_bot_left[26]
    ANTENNADIFFAREA 0.870000 ;
    PORT
      LAYER met4 ;
        RECT 454.020 -70.040 455.860 0.375 ;
    END
  END array_col_bot_left[26]
  PIN array_col_bot_left[58]
    ANTENNADIFFAREA 0.870000 ;
    PORT
      LAYER met4 ;
        RECT 70.020 -70.040 71.860 0.375 ;
    END
  END array_col_bot_left[58]
  PIN col_event_rst_top_left[39]
    ANTENNAGATEAREA 4.032000 ;
    PORT
      LAYER met4 ;
        RECT 291.220 1638.440 292.600 1708.840 ;
    END
  END col_event_rst_top_left[39]
  PIN col_event_rst_top_left[26]
    ANTENNAGATEAREA 4.032000 ;
    PORT
      LAYER met4 ;
        RECT 456.780 1638.440 458.160 1708.840 ;
    END
  END col_event_rst_top_left[26]
  PIN array_col_bot_left[2]
    ANTENNADIFFAREA 0.870000 ;
    PORT
      LAYER met4 ;
        RECT 742.020 -70.040 743.860 0.375 ;
    END
  END array_col_bot_left[2]
  PIN array_col_bot_left[3]
    ANTENNADIFFAREA 0.870000 ;
    PORT
      LAYER met4 ;
        RECT 725.520 -70.040 727.360 0.375 ;
    END
  END array_col_bot_left[3]
  PIN col_event_rst_top_left[40]
    ANTENNAGATEAREA 4.032000 ;
    PORT
      LAYER met4 ;
        RECT 288.780 1638.440 290.160 1708.840 ;
    END
  END col_event_rst_top_left[40]
  PIN col_event_rst_top_left[30]
    ANTENNAGATEAREA 4.032000 ;
    PORT
      LAYER met4 ;
        RECT 408.780 1638.440 410.160 1708.840 ;
    END
  END col_event_rst_top_left[30]
  PIN array_col_bot_right[29]
    ANTENNADIFFAREA 0.870000 ;
    PORT
      LAYER met4 ;
        RECT 1181.520 -70.040 1183.360 0.375 ;
    END
  END array_col_bot_right[29]
  PIN array_col_bot_right[28]
    ANTENNADIFFAREA 0.870000 ;
    PORT
      LAYER met4 ;
        RECT 1198.020 -70.040 1199.860 0.375 ;
    END
  END array_col_bot_right[28]
  PIN array_col_bot_right[25]
    ANTENNADIFFAREA 0.870000 ;
    PORT
      LAYER met4 ;
        RECT 1229.520 -70.040 1231.360 0.375 ;
    END
  END array_col_bot_right[25]
  PIN col_event_rst_top_right[57]
    ANTENNAGATEAREA 4.032000 ;
    PORT
      LAYER met4 ;
        RECT 843.220 1638.440 844.600 1708.840 ;
    END
  END col_event_rst_top_right[57]
  PIN col_event_rst_top_right[54]
    ANTENNAGATEAREA 4.032000 ;
    PORT
      LAYER met4 ;
        RECT 888.780 1638.440 890.160 1708.840 ;
    END
  END col_event_rst_top_right[54]
  PIN col_event_rst_top_right[53]
    ANTENNAGATEAREA 4.032000 ;
    PORT
      LAYER met4 ;
        RECT 891.220 1638.440 892.600 1708.840 ;
    END
  END col_event_rst_top_right[53]
  PIN col_event_rst_top_right[50]
    ANTENNAGATEAREA 4.032000 ;
    PORT
      LAYER met4 ;
        RECT 936.780 1638.440 938.160 1708.840 ;
    END
  END col_event_rst_top_right[50]
  PIN col_event_rst_top_right[49]
    ANTENNAGATEAREA 4.032000 ;
    PORT
      LAYER met4 ;
        RECT 939.220 1638.440 940.600 1708.840 ;
    END
  END col_event_rst_top_right[49]
  PIN col_event_rst_top_right[46]
    ANTENNAGATEAREA 4.032000 ;
    PORT
      LAYER met4 ;
        RECT 984.780 1638.440 986.160 1708.840 ;
    END
  END col_event_rst_top_right[46]
  PIN col_event_rst_top_right[45]
    ANTENNAGATEAREA 4.032000 ;
    PORT
      LAYER met4 ;
        RECT 987.220 1638.440 988.600 1708.840 ;
    END
  END col_event_rst_top_right[45]
  PIN col_event_rst_top_right[42]
    ANTENNAGATEAREA 4.032000 ;
    PORT
      LAYER met4 ;
        RECT 1032.780 1638.440 1034.160 1708.840 ;
    END
  END col_event_rst_top_right[42]
  PIN col_event_rst_top_right[41]
    ANTENNAGATEAREA 4.032000 ;
    PORT
      LAYER met4 ;
        RECT 1035.220 1638.440 1036.600 1708.840 ;
    END
  END col_event_rst_top_right[41]
  PIN array_col_top_left[30]
    ANTENNADIFFAREA 0.870000 ;
    PORT
      LAYER met4 ;
        RECT 406.020 1638.440 407.860 1708.840 ;
    END
  END array_col_top_left[30]
  PIN array_col_top_right[32]
    ANTENNADIFFAREA 0.870000 ;
    PORT
      LAYER met4 ;
        RECT 1150.020 1638.440 1151.860 1708.840 ;
    END
  END array_col_top_right[32]
  PIN array_col_bot_left[54]
    ANTENNADIFFAREA 0.870000 ;
    PORT
      LAYER met4 ;
        RECT 118.020 -70.040 119.860 0.375 ;
    END
  END array_col_bot_left[54]
  PIN array_col_bot_right[24]
    ANTENNADIFFAREA 0.870000 ;
    PORT
      LAYER met4 ;
        RECT 1246.020 -70.040 1247.860 0.375 ;
    END
  END array_col_bot_right[24]
  PIN array_col_bot_right[21]
    ANTENNADIFFAREA 0.870000 ;
    PORT
      LAYER met4 ;
        RECT 1277.520 -70.040 1279.360 0.375 ;
    END
  END array_col_bot_right[21]
  PIN array_col_bot_right[20]
    ANTENNADIFFAREA 0.870000 ;
    PORT
      LAYER met4 ;
        RECT 1294.020 -70.040 1295.860 0.375 ;
    END
  END array_col_bot_right[20]
  PIN array_col_bot_right[7]
    ANTENNADIFFAREA 0.870000 ;
    PORT
      LAYER met4 ;
        RECT 1445.520 -70.040 1447.360 0.375 ;
    END
  END array_col_bot_right[7]
  PIN col_event_rst_top_left[43]
    ANTENNAGATEAREA 4.032000 ;
    PORT
      LAYER met4 ;
        RECT 243.220 1638.440 244.600 1708.840 ;
    END
  END col_event_rst_top_left[43]
  PIN array_col_top_left[7]
    ANTENNADIFFAREA 0.870000 ;
    PORT
      LAYER met4 ;
        RECT 677.520 1638.440 679.360 1708.840 ;
    END
  END array_col_top_left[7]
  PIN array_col_bot_right[12]
    ANTENNADIFFAREA 0.870000 ;
    PORT
      LAYER met4 ;
        RECT 1390.020 -70.040 1391.860 0.375 ;
    END
  END array_col_bot_right[12]
  PIN array_col_bot_left[53]
    ANTENNADIFFAREA 0.870000 ;
    PORT
      LAYER met4 ;
        RECT 125.520 -70.040 127.360 0.375 ;
    END
  END array_col_bot_left[53]
  PIN array_col_bot_left[50]
    ANTENNADIFFAREA 0.870000 ;
    PORT
      LAYER met4 ;
        RECT 166.020 -70.040 167.860 0.375 ;
    END
  END array_col_bot_left[50]
  PIN array_col_bot_left[49]
    ANTENNADIFFAREA 0.870000 ;
    PORT
      LAYER met4 ;
        RECT 173.520 -70.040 175.360 0.375 ;
    END
  END array_col_bot_left[49]
  PIN col_event_rst_top_left[59]
    ANTENNAGATEAREA 4.032000 ;
    PORT
      LAYER met4 ;
        RECT 51.220 1638.440 52.600 1708.840 ;
    END
  END col_event_rst_top_left[59]
  PIN array_col_bot_right[60]
    ANTENNADIFFAREA 0.870000 ;
    PORT
      LAYER met4 ;
        RECT 814.020 -70.040 815.860 0.375 ;
    END
  END array_col_bot_right[60]
  PIN array_col_bot_right[57]
    ANTENNADIFFAREA 0.870000 ;
    PORT
      LAYER met4 ;
        RECT 845.520 -70.040 847.360 0.375 ;
    END
  END array_col_bot_right[57]
  PIN array_col_bot_right[56]
    ANTENNADIFFAREA 0.870000 ;
    PORT
      LAYER met4 ;
        RECT 862.020 -70.040 863.860 0.375 ;
    END
  END array_col_bot_right[56]
  PIN array_col_bot_right[53]
    ANTENNADIFFAREA 0.870000 ;
    PORT
      LAYER met4 ;
        RECT 893.520 -70.040 895.360 0.375 ;
    END
  END array_col_bot_right[53]
  PIN array_col_bot_right[52]
    ANTENNADIFFAREA 0.870000 ;
    PORT
      LAYER met4 ;
        RECT 910.020 -70.040 911.860 0.375 ;
    END
  END array_col_bot_right[52]
  PIN array_col_bot_right[49]
    ANTENNADIFFAREA 0.870000 ;
    PORT
      LAYER met4 ;
        RECT 941.520 -70.040 943.360 0.375 ;
    END
  END array_col_bot_right[49]
  PIN array_col_bot_right[48]
    ANTENNADIFFAREA 0.870000 ;
    PORT
      LAYER met4 ;
        RECT 958.020 -70.040 959.860 0.375 ;
    END
  END array_col_bot_right[48]
  PIN array_col_bot_right[45]
    ANTENNADIFFAREA 0.870000 ;
    PORT
      LAYER met4 ;
        RECT 989.520 -70.040 991.360 0.375 ;
    END
  END array_col_bot_right[45]
  PIN array_col_bot_right[44]
    ANTENNADIFFAREA 0.870000 ;
    PORT
      LAYER met4 ;
        RECT 1006.020 -70.040 1007.860 0.375 ;
    END
  END array_col_bot_right[44]
  PIN col_event_rst_top_left[58]
    ANTENNAGATEAREA 4.032000 ;
    PORT
      LAYER met4 ;
        RECT 72.780 1638.440 74.160 1708.840 ;
    END
  END col_event_rst_top_left[58]
  PIN array_col_bot_right[41]
    ANTENNADIFFAREA 0.870000 ;
    PORT
      LAYER met4 ;
        RECT 1037.520 -70.040 1039.360 0.375 ;
    END
  END array_col_bot_right[41]
  PIN array_col_bot_right[40]
    ANTENNADIFFAREA 0.870000 ;
    PORT
      LAYER met4 ;
        RECT 1054.020 -70.040 1055.860 0.375 ;
    END
  END array_col_bot_right[40]
  PIN array_col_bot_right[37]
    ANTENNADIFFAREA 0.870000 ;
    PORT
      LAYER met4 ;
        RECT 1085.520 -70.040 1087.360 0.375 ;
    END
  END array_col_bot_right[37]
  PIN array_col_bot_right[36]
    ANTENNADIFFAREA 0.870000 ;
    PORT
      LAYER met4 ;
        RECT 1102.020 -70.040 1103.860 0.375 ;
    END
  END array_col_bot_right[36]
  PIN array_col_bot_right[33]
    ANTENNADIFFAREA 0.870000 ;
    PORT
      LAYER met4 ;
        RECT 1133.520 -70.040 1135.360 0.375 ;
    END
  END array_col_bot_right[33]
  PIN array_col_bot_right[32]
    ANTENNADIFFAREA 0.870000 ;
    PORT
      LAYER met4 ;
        RECT 1150.020 -70.040 1151.860 0.375 ;
    END
  END array_col_bot_right[32]
  PIN array_col_bot_left[10]
    ANTENNADIFFAREA 0.870000 ;
    PORT
      LAYER met4 ;
        RECT 646.020 -70.040 647.860 0.375 ;
    END
  END array_col_bot_left[10]
  PIN array_col_bot_left[11]
    ANTENNADIFFAREA 0.870000 ;
    PORT
      LAYER met4 ;
        RECT 629.520 -70.040 631.360 0.375 ;
    END
  END array_col_bot_left[11]
  PIN array_col_bot_left[6]
    ANTENNADIFFAREA 0.870000 ;
    PORT
      LAYER met4 ;
        RECT 694.020 -70.040 695.860 0.375 ;
    END
  END array_col_bot_left[6]
  PIN col_event_rst_top_left[54]
    ANTENNAGATEAREA 4.032000 ;
    PORT
      LAYER met4 ;
        RECT 120.780 1638.440 122.160 1708.840 ;
    END
  END col_event_rst_top_left[54]
  PIN col_event_rst_top_left[55]
    ANTENNAGATEAREA 4.032000 ;
    PORT
      LAYER met4 ;
        RECT 99.220 1638.440 100.600 1708.840 ;
    END
  END col_event_rst_top_left[55]
  PIN col_event_rst_top_left[22]
    ANTENNAGATEAREA 4.032000 ;
    PORT
      LAYER met4 ;
        RECT 504.780 1638.440 506.160 1708.840 ;
    END
  END col_event_rst_top_left[22]
  PIN col_event_rst_top_left[13]
    ANTENNAGATEAREA 4.032000 ;
    PORT
      LAYER met4 ;
        RECT 603.220 1638.440 604.600 1708.840 ;
    END
  END col_event_rst_top_left[13]
  PIN array_col_bot_left[37]
    ANTENNADIFFAREA 0.870000 ;
    PORT
      LAYER met4 ;
        RECT 317.520 -70.040 319.360 0.375 ;
    END
  END array_col_bot_left[37]
  PIN array_col_bot_left[36]
    ANTENNADIFFAREA 0.870000 ;
    PORT
      LAYER met4 ;
        RECT 334.020 -70.040 335.860 0.375 ;
    END
  END array_col_bot_left[36]
  PIN array_col_bot_left[29]
    ANTENNADIFFAREA 0.870000 ;
    PORT
      LAYER met4 ;
        RECT 413.520 -70.040 415.360 0.375 ;
    END
  END array_col_bot_left[29]
  PIN array_col_bot_left[28]
    ANTENNADIFFAREA 0.870000 ;
    PORT
      LAYER met4 ;
        RECT 430.020 -70.040 431.860 0.375 ;
    END
  END array_col_bot_left[28]
  PIN array_col_bot_left[24]
    ANTENNADIFFAREA 0.870000 ;
    PORT
      LAYER met4 ;
        RECT 478.020 -70.040 479.860 0.375 ;
    END
  END array_col_bot_left[24]
  PIN array_col_bot_left[19]
    ANTENNADIFFAREA 0.870000 ;
    PORT
      LAYER met4 ;
        RECT 533.520 -70.040 535.360 0.375 ;
    END
  END array_col_bot_left[19]
  PIN col_event_rst_top_left[52]
    ANTENNAGATEAREA 4.032000 ;
    PORT
      LAYER met4 ;
        RECT 144.780 1638.440 146.160 1708.840 ;
    END
  END col_event_rst_top_left[52]
  PIN array_col_bot_left[61]
    ANTENNADIFFAREA 0.870000 ;
    PORT
      LAYER met4 ;
        RECT 29.520 -70.040 31.360 0.375 ;
    END
  END array_col_bot_left[61]
  PIN array_col_bot_left[57]
    ANTENNADIFFAREA 0.870000 ;
    PORT
      LAYER met4 ;
        RECT 77.520 -70.040 79.360 0.375 ;
    END
  END array_col_bot_left[57]
  PIN array_col_bot_left[56]
    ANTENNADIFFAREA 0.870000 ;
    PORT
      LAYER met4 ;
        RECT 94.020 -70.040 95.860 0.375 ;
    END
  END array_col_bot_left[56]
  PIN array_col_bot_left[52]
    ANTENNADIFFAREA 0.870000 ;
    PORT
      LAYER met4 ;
        RECT 142.020 -70.040 143.860 0.375 ;
    END
  END array_col_bot_left[52]
  PIN array_col_bot_left[51]
    ANTENNADIFFAREA 0.870000 ;
    PORT
      LAYER met4 ;
        RECT 149.520 -70.040 151.360 0.375 ;
    END
  END array_col_bot_left[51]
  PIN array_col_bot_left[48]
    ANTENNADIFFAREA 0.870000 ;
    PORT
      LAYER met4 ;
        RECT 190.020 -70.040 191.860 0.375 ;
    END
  END array_col_bot_left[48]
  PIN array_col_bot_left[47]
    ANTENNADIFFAREA 0.870000 ;
    PORT
      LAYER met4 ;
        RECT 197.520 -70.040 199.360 0.375 ;
    END
  END array_col_bot_left[47]
  PIN array_col_bot_left[46]
    ANTENNADIFFAREA 0.870000 ;
    PORT
      LAYER met4 ;
        RECT 214.020 -70.040 215.860 0.375 ;
    END
  END array_col_bot_left[46]
  PIN col_event_rst_top_left[11]
    ANTENNAGATEAREA 4.032000 ;
    PORT
      LAYER met4 ;
        RECT 627.220 1638.440 628.600 1708.840 ;
    END
  END col_event_rst_top_left[11]
  PIN array_col_top_right[17]
    ANTENNADIFFAREA 0.870000 ;
    PORT
      LAYER met4 ;
        RECT 1325.520 1638.440 1327.360 1708.840 ;
    END
  END array_col_top_right[17]
  PIN array_col_bot_left[63]
    ANTENNADIFFAREA 0.870000 ;
    PORT
      LAYER met4 ;
        RECT 5.520 -70.040 7.360 0.375 ;
    END
  END array_col_bot_left[63]
  PIN array_col_bot_right[51]
    ANTENNADIFFAREA 0.870000 ;
    PORT
      LAYER met4 ;
        RECT 917.520 -70.040 919.360 0.375 ;
    END
  END array_col_bot_right[51]
  PIN array_col_bot_right[50]
    ANTENNADIFFAREA 0.870000 ;
    PORT
      LAYER met4 ;
        RECT 934.020 -70.040 935.860 0.375 ;
    END
  END array_col_bot_right[50]
  PIN array_col_bot_right[47]
    ANTENNADIFFAREA 0.870000 ;
    PORT
      LAYER met4 ;
        RECT 965.520 -70.040 967.360 0.375 ;
    END
  END array_col_bot_right[47]
  PIN array_col_bot_right[46]
    ANTENNADIFFAREA 0.870000 ;
    PORT
      LAYER met4 ;
        RECT 982.020 -70.040 983.860 0.375 ;
    END
  END array_col_bot_right[46]
  PIN array_col_bot_right[43]
    ANTENNADIFFAREA 0.870000 ;
    PORT
      LAYER met4 ;
        RECT 1013.520 -70.040 1015.360 0.375 ;
    END
  END array_col_bot_right[43]
  PIN array_col_bot_right[42]
    ANTENNADIFFAREA 0.870000 ;
    PORT
      LAYER met4 ;
        RECT 1030.020 -70.040 1031.860 0.375 ;
    END
  END array_col_bot_right[42]
  PIN array_col_bot_right[39]
    ANTENNADIFFAREA 0.870000 ;
    PORT
      LAYER met4 ;
        RECT 1061.520 -70.040 1063.360 0.375 ;
    END
  END array_col_bot_right[39]
  PIN array_col_bot_right[38]
    ANTENNADIFFAREA 0.870000 ;
    PORT
      LAYER met4 ;
        RECT 1078.020 -70.040 1079.860 0.375 ;
    END
  END array_col_bot_right[38]
  PIN array_col_bot_right[35]
    ANTENNADIFFAREA 0.870000 ;
    PORT
      LAYER met4 ;
        RECT 1109.520 -70.040 1111.360 0.375 ;
    END
  END array_col_bot_right[35]
  PIN array_col_bot_right[8]
    ANTENNADIFFAREA 0.870000 ;
    PORT
      LAYER met4 ;
        RECT 1438.020 -70.040 1439.860 0.375 ;
    END
  END array_col_bot_right[8]
  PIN array_col_bot_right[34]
    ANTENNADIFFAREA 0.870000 ;
    PORT
      LAYER met4 ;
        RECT 1126.020 -70.040 1127.860 0.375 ;
    END
  END array_col_bot_right[34]
  PIN array_col_bot_right[31]
    ANTENNADIFFAREA 0.870000 ;
    PORT
      LAYER met4 ;
        RECT 1157.520 -70.040 1159.360 0.375 ;
    END
  END array_col_bot_right[31]
  PIN array_col_top_right[4]
    ANTENNADIFFAREA 0.870000 ;
    PORT
      LAYER met4 ;
        RECT 1486.020 1638.440 1487.860 1708.840 ;
    END
  END array_col_top_right[4]
  PIN array_col_top_left[63]
    ANTENNADIFFAREA 0.870000 ;
    PORT
      LAYER met4 ;
        RECT 5.520 1638.440 7.360 1708.840 ;
    END
  END array_col_top_left[63]
  PIN array_col_top_left[0]
    ANTENNADIFFAREA 0.870000 ;
    PORT
      LAYER met4 ;
        RECT 766.020 1638.440 767.860 1708.840 ;
    END
  END array_col_top_left[0]
  PIN array_col_bot_left[1]
    ANTENNADIFFAREA 0.870000 ;
    PORT
      LAYER met4 ;
        RECT 749.520 -70.040 751.360 0.375 ;
    END
  END array_col_bot_left[1]
  PIN array_col_bot_right[30]
    ANTENNADIFFAREA 0.870000 ;
    PORT
      LAYER met4 ;
        RECT 1174.020 -70.040 1175.860 0.375 ;
    END
  END array_col_bot_right[30]
  PIN array_col_bot_left[12]
    ANTENNADIFFAREA 0.870000 ;
    PORT
      LAYER met4 ;
        RECT 622.020 -70.040 623.860 0.375 ;
    END
  END array_col_bot_left[12]
  PIN array_col_bot_left[13]
    ANTENNADIFFAREA 0.870000 ;
    PORT
      LAYER met4 ;
        RECT 605.520 -70.040 607.360 0.375 ;
    END
  END array_col_bot_left[13]
  PIN col_event_rst_top_left[44]
    ANTENNAGATEAREA 4.032000 ;
    PORT
      LAYER met4 ;
        RECT 240.780 1638.440 242.160 1708.840 ;
    END
  END col_event_rst_top_left[44]
  PIN col_event_rst_top_left[33]
    ANTENNAGATEAREA 4.032000 ;
    PORT
      LAYER met4 ;
        RECT 363.220 1638.440 364.600 1708.840 ;
    END
  END col_event_rst_top_left[33]
  PIN array_col_bot_left[39]
    ANTENNADIFFAREA 0.870000 ;
    PORT
      LAYER met4 ;
        RECT 293.520 -70.040 295.360 0.375 ;
    END
  END array_col_bot_left[39]
  PIN array_col_top_right[2]
    ANTENNADIFFAREA 0.870000 ;
    PORT
      LAYER met4 ;
        RECT 1510.020 1638.440 1511.860 1708.840 ;
    END
  END array_col_top_right[2]
  PIN array_col_bot_left[38]
    ANTENNADIFFAREA 0.870000 ;
    PORT
      LAYER met4 ;
        RECT 310.020 -70.040 311.860 0.375 ;
    END
  END array_col_bot_left[38]
  PIN array_col_bot_left[35]
    ANTENNADIFFAREA 0.870000 ;
    PORT
      LAYER met4 ;
        RECT 341.520 -70.040 343.360 0.375 ;
    END
  END array_col_bot_left[35]
  PIN array_col_bot_right[5]
    ANTENNADIFFAREA 0.870000 ;
    PORT
      LAYER met4 ;
        RECT 1469.520 -70.040 1471.360 0.375 ;
    END
  END array_col_bot_right[5]
  PIN array_col_bot_left[34]
    ANTENNADIFFAREA 0.870000 ;
    PORT
      LAYER met4 ;
        RECT 358.020 -70.040 359.860 0.375 ;
    END
  END array_col_bot_left[34]
  PIN array_col_bot_left[27]
    ANTENNADIFFAREA 0.870000 ;
    PORT
      LAYER met4 ;
        RECT 437.520 -70.040 439.360 0.375 ;
    END
  END array_col_bot_left[27]
  PIN array_col_bot_left[25]
    ANTENNADIFFAREA 0.870000 ;
    PORT
      LAYER met4 ;
        RECT 461.520 -70.040 463.360 0.375 ;
    END
  END array_col_bot_left[25]
  PIN array_col_bot_left[18]
    ANTENNADIFFAREA 0.870000 ;
    PORT
      LAYER met4 ;
        RECT 550.020 -70.040 551.860 0.375 ;
    END
  END array_col_bot_left[18]
  PIN array_col_bot_left[17]
    ANTENNADIFFAREA 0.870000 ;
    PORT
      LAYER met4 ;
        RECT 557.520 -70.040 559.360 0.375 ;
    END
  END array_col_bot_left[17]
  PIN array_col_bot_left[9]
    ANTENNADIFFAREA 0.870000 ;
    PORT
      LAYER met4 ;
        RECT 653.520 -70.040 655.360 0.375 ;
    END
  END array_col_bot_left[9]
  PIN array_col_bot_right[63]
    ANTENNADIFFAREA 0.870000 ;
    PORT
      LAYER met4 ;
        RECT 773.520 -70.040 775.360 0.375 ;
    END
  END array_col_bot_right[63]
  PIN array_col_bot_left[8]
    ANTENNADIFFAREA 0.870000 ;
    PORT
      LAYER met4 ;
        RECT 670.020 -70.040 671.860 0.375 ;
    END
  END array_col_bot_left[8]
  PIN col_event_rst_top_left[63]
    ANTENNAGATEAREA 4.032000 ;
    PORT
      LAYER met4 ;
        RECT 3.220 1638.440 4.600 1708.840 ;
    END
  END col_event_rst_top_left[63]
  PIN col_event_rst_top_left[62]
    ANTENNAGATEAREA 4.032000 ;
    PORT
      LAYER met4 ;
        RECT 24.780 1638.440 26.160 1708.840 ;
    END
  END col_event_rst_top_left[62]
  PIN col_event_rst_top_left[42]
    ANTENNAGATEAREA 4.032000 ;
    PORT
      LAYER met4 ;
        RECT 264.780 1638.440 266.160 1708.840 ;
    END
  END col_event_rst_top_left[42]
  PIN col_event_rst_top_left[37]
    ANTENNAGATEAREA 4.032000 ;
    PORT
      LAYER met4 ;
        RECT 315.220 1638.440 316.600 1708.840 ;
    END
  END col_event_rst_top_left[37]
  PIN col_event_rst_top_left[35]
    ANTENNAGATEAREA 4.032000 ;
    PORT
      LAYER met4 ;
        RECT 339.220 1638.440 340.600 1708.840 ;
    END
  END col_event_rst_top_left[35]
  PIN col_event_rst_top_left[31]
    ANTENNAGATEAREA 4.032000 ;
    PORT
      LAYER met4 ;
        RECT 387.220 1638.440 388.600 1708.840 ;
    END
  END col_event_rst_top_left[31]
  PIN array_col_bot_left[59]
    ANTENNADIFFAREA 0.870000 ;
    PORT
      LAYER met4 ;
        RECT 53.520 -70.040 55.360 0.375 ;
    END
  END array_col_bot_left[59]
  PIN array_col_top_left[37]
    ANTENNADIFFAREA 0.870000 ;
    PORT
      LAYER met4 ;
        RECT 317.520 1638.440 319.360 1708.840 ;
    END
  END array_col_top_left[37]
  PIN col_event_rst_top_right[31]
    ANTENNAGATEAREA 4.032000 ;
    PORT
      LAYER met4 ;
        RECT 1155.220 1638.440 1156.600 1708.840 ;
    END
  END col_event_rst_top_right[31]
  PIN col_event_rst_top_right[30]
    ANTENNAGATEAREA 4.032000 ;
    PORT
      LAYER met4 ;
        RECT 1176.780 1638.440 1178.160 1708.840 ;
    END
  END col_event_rst_top_right[30]
  PIN col_event_rst_top_right[29]
    ANTENNAGATEAREA 4.032000 ;
    PORT
      LAYER met4 ;
        RECT 1179.220 1638.440 1180.600 1708.840 ;
    END
  END col_event_rst_top_right[29]
  PIN col_event_rst_top_right[28]
    ANTENNAGATEAREA 4.032000 ;
    PORT
      LAYER met4 ;
        RECT 1200.780 1638.440 1202.160 1708.840 ;
    END
  END col_event_rst_top_right[28]
  PIN row_off_detect_bot[21]
    ANTENNAGATEAREA 8.064000 ;
    PORT
      LAYER met3 ;
        RECT -63.480 565.610 1.535 565.910 ;
    END
  END row_off_detect_bot[21]
  PIN row_off_detect_bot[22]
    ANTENNAGATEAREA 8.064000 ;
    PORT
      LAYER met3 ;
        RECT -63.480 544.530 1.535 544.830 ;
    END
  END row_off_detect_bot[22]
  PIN detect_pulse_global_bot_left
    ANTENNAGATEAREA 147.199997 ;
    PORT
      LAYER met3 ;
        RECT -63.480 18.225 3.040 19.585 ;
    END
  END detect_pulse_global_bot_left
  PIN row_on_detect_bot[5]
    ANTENNAGATEAREA 16.128000 ;
    PORT
      LAYER met3 ;
        RECT -63.480 758.730 1.535 759.030 ;
    END
  END row_on_detect_bot[5]
  PIN row_off_detect_top[12]
    ANTENNAGATEAREA 8.064000 ;
    PORT
      LAYER met3 ;
        RECT -63.480 1432.610 1.535 1432.910 ;
    END
  END row_off_detect_top[12]
  PIN row_on_detect_top[13]
    ANTENNAGATEAREA 16.128000 ;
    PORT
      LAYER met3 ;
        RECT -63.480 1430.570 1.535 1430.870 ;
    END
  END row_on_detect_top[13]
  PIN detect_pulse_global_top_left
    ANTENNAGATEAREA 147.199997 ;
    PORT
      LAYER met3 ;
        RECT -63.480 1618.945 2.710 1620.305 ;
    END
  END detect_pulse_global_top_left
  PIN row_on_detect_top[1]
    ANTENNAGATEAREA 16.128000 ;
    PORT
      LAYER met3 ;
        RECT -63.480 1574.730 1.535 1575.030 ;
    END
  END row_on_detect_top[1]
  PIN row_on_detect_top[35]
    ANTENNAGATEAREA 16.128000 ;
    PORT
      LAYER met3 ;
        RECT -63.480 1166.730 1.535 1167.030 ;
    END
  END row_on_detect_top[35]
  PIN row_off_detect_top[34]
    ANTENNAGATEAREA 8.064000 ;
    PORT
      LAYER met3 ;
        RECT -63.480 1168.770 1.535 1169.070 ;
    END
  END row_off_detect_top[34]
  PIN row_off_detect_top[14]
    ANTENNAGATEAREA 8.064000 ;
    PORT
      LAYER met3 ;
        RECT -63.480 1408.810 1.535 1409.110 ;
    END
  END row_off_detect_top[14]
  PIN pre_charge_global_top_left
    ANTENNAGATEAREA 1024.000000 ;
    PORT
      LAYER met3 ;
        RECT -63.480 1607.355 2.710 1608.715 ;
    END
  END pre_charge_global_top_left
  PIN row_on_detect_bot[20]
    ANTENNAGATEAREA 16.128000 ;
    PORT
      LAYER met3 ;
        RECT -63.480 567.650 1.535 567.950 ;
    END
  END row_on_detect_bot[20]
  PIN row_on_detect_top[19]
    ANTENNAGATEAREA 16.128000 ;
    PORT
      LAYER met3 ;
        RECT -63.480 1358.490 1.535 1358.790 ;
    END
  END row_on_detect_top[19]
  PIN row_on_detect_top[18]
    ANTENNAGATEAREA 16.128000 ;
    PORT
      LAYER met3 ;
        RECT -63.480 1359.850 1.535 1360.150 ;
    END
  END row_on_detect_top[18]
  PIN row_on_detect_bot[1]
    ANTENNAGATEAREA 16.128000 ;
    PORT
      LAYER met3 ;
        RECT -63.480 806.330 1.535 806.630 ;
    END
  END row_on_detect_bot[1]
  PIN row_on_detect_bot[0]
    ANTENNAGATEAREA 16.128000 ;
    PORT
      LAYER met3 ;
        RECT -63.480 807.690 1.535 807.990 ;
    END
  END row_on_detect_bot[0]
  PIN row_on_detect_top[8]
    ANTENNAGATEAREA 16.128000 ;
    PORT
      LAYER met3 ;
        RECT -63.480 1479.530 1.535 1479.830 ;
    END
  END row_on_detect_top[8]
  PIN row_off_detect_bot[36]
    ANTENNAGATEAREA 8.064000 ;
    PORT
      LAYER met3 ;
        RECT -63.480 376.570 1.535 376.870 ;
    END
  END row_off_detect_bot[36]
  PIN row_on_detect_bot[26]
    ANTENNAGATEAREA 16.128000 ;
    PORT
      LAYER met3 ;
        RECT -63.480 495.570 1.535 495.870 ;
    END
  END row_on_detect_bot[26]
  PIN row_off_detect_top[29]
    ANTENNAGATEAREA 8.064000 ;
    PORT
      LAYER met3 ;
        RECT -63.480 1237.450 1.535 1237.750 ;
    END
  END row_off_detect_top[29]
  PIN row_on_detect_top[28]
    ANTENNAGATEAREA 16.128000 ;
    PORT
      LAYER met3 ;
        RECT -63.480 1239.490 1.535 1239.790 ;
    END
  END row_on_detect_top[28]
  PIN row_off_detect_top[53]
    ANTENNAGATEAREA 8.064000 ;
    PORT
      LAYER met3 ;
        RECT -63.480 949.130 1.535 949.430 ;
    END
  END row_off_detect_top[53]
  PIN row_off_detect_bot[50]
    ANTENNAGATEAREA 8.064000 ;
    PORT
      LAYER met3 ;
        RECT -63.480 208.610 1.535 208.910 ;
    END
  END row_off_detect_bot[50]
  PIN row_off_detect_bot[52]
    ANTENNAGATEAREA 8.064000 ;
    PORT
      LAYER met3 ;
        RECT -63.480 184.810 1.535 185.110 ;
    END
  END row_off_detect_bot[52]
  PIN row_on_detect_top[9]
    ANTENNAGATEAREA 16.128000 ;
    PORT
      LAYER met3 ;
        RECT -63.480 1478.850 1.535 1479.150 ;
    END
  END row_on_detect_top[9]
  PIN row_off_detect_top[8]
    ANTENNAGATEAREA 8.064000 ;
    PORT
      LAYER met3 ;
        RECT -63.480 1480.890 1.535 1481.190 ;
    END
  END row_off_detect_top[8]
  PIN row_off_detect_top[46]
    ANTENNAGATEAREA 8.064000 ;
    PORT
      LAYER met3 ;
        RECT -63.480 1024.610 1.535 1024.910 ;
    END
  END row_off_detect_top[46]
  PIN row_off_detect_bot[40]
    ANTENNAGATEAREA 8.064000 ;
    PORT
      LAYER met3 ;
        RECT -63.480 328.970 1.535 329.270 ;
    END
  END row_off_detect_bot[40]
  PIN row_on_detect_bot[7]
    ANTENNAGATEAREA 16.128000 ;
    PORT
      LAYER met3 ;
        RECT -63.480 734.930 1.535 735.230 ;
    END
  END row_on_detect_bot[7]
  PIN row_on_detect_bot[13]
    ANTENNAGATEAREA 16.128000 ;
    PORT
      LAYER met3 ;
        RECT -63.480 662.850 1.535 663.150 ;
    END
  END row_on_detect_bot[13]
  PIN row_off_detect_top[7]
    ANTENNAGATEAREA 8.064000 ;
    PORT
      LAYER met3 ;
        RECT -63.480 1501.290 1.535 1501.590 ;
    END
  END row_off_detect_top[7]
  PIN row_on_detect_top[4]
    ANTENNAGATEAREA 16.128000 ;
    PORT
      LAYER met3 ;
        RECT -63.480 1527.810 1.535 1528.110 ;
    END
  END row_on_detect_top[4]
  PIN row_on_detect_top[25]
    ANTENNAGATEAREA 16.128000 ;
    PORT
      LAYER met3 ;
        RECT -63.480 1286.410 1.535 1286.710 ;
    END
  END row_on_detect_top[25]
  PIN row_on_detect_top[24]
    ANTENNAGATEAREA 16.128000 ;
    PORT
      LAYER met3 ;
        RECT -63.480 1287.770 1.535 1288.070 ;
    END
  END row_on_detect_top[24]
  PIN row_on_detect_top[36]
    ANTENNAGATEAREA 16.128000 ;
    PORT
      LAYER met3 ;
        RECT -63.480 1143.610 1.535 1143.910 ;
    END
  END row_on_detect_top[36]
  PIN row_off_detect_top[40]
    ANTENNAGATEAREA 8.064000 ;
    PORT
      LAYER met3 ;
        RECT -63.480 1096.690 1.535 1096.990 ;
    END
  END row_off_detect_top[40]
  PIN row_on_detect_top[11]
    ANTENNAGATEAREA 16.128000 ;
    PORT
      LAYER met3 ;
        RECT -63.480 1454.370 1.535 1454.670 ;
    END
  END row_on_detect_top[11]
  PIN dac_config_0
    ANTENNAGATEAREA 36576.000000 ;
    PORT
      LAYER met3 ;
        RECT 1624.640 816.180 1625.640 817.180 ;
    END
  END dac_config_0
  PIN row_on_detect_top[14]
    ANTENNAGATEAREA 16.128000 ;
    PORT
      LAYER met3 ;
        RECT -63.480 1407.450 1.535 1407.750 ;
    END
  END row_on_detect_top[14]
  PIN row_on_detect_top[38]
    ANTENNAGATEAREA 16.128000 ;
    PORT
      LAYER met3 ;
        RECT -63.480 1119.810 1.535 1120.110 ;
    END
  END row_on_detect_top[38]
  PIN row_off_detect_top[38]
    ANTENNAGATEAREA 8.064000 ;
    PORT
      LAYER met3 ;
        RECT -63.480 1120.490 1.535 1120.790 ;
    END
  END row_off_detect_top[38]
  PIN row_off_detect_top[43]
    ANTENNAGATEAREA 8.064000 ;
    PORT
      LAYER met3 ;
        RECT -63.480 1069.490 1.535 1069.790 ;
    END
  END row_off_detect_top[43]
  PIN row_on_detect_top[41]
    ANTENNAGATEAREA 16.128000 ;
    PORT
      LAYER met3 ;
        RECT -63.480 1094.650 1.535 1094.950 ;
    END
  END row_on_detect_top[41]
  PIN row_on_detect_top[30]
    ANTENNAGATEAREA 16.128000 ;
    PORT
      LAYER met3 ;
        RECT -63.480 1215.690 1.535 1215.990 ;
    END
  END row_on_detect_top[30]
  PIN row_off_detect_top[30]
    ANTENNAGATEAREA 8.064000 ;
    PORT
      LAYER met3 ;
        RECT -63.480 1216.370 1.535 1216.670 ;
    END
  END row_off_detect_top[30]
  PIN dac_config_2
    ANTENNAGATEAREA 36864.000000 ;
    PORT
      LAYER met3 ;
        RECT 1624.640 826.380 1625.640 827.380 ;
    END
  END dac_config_2
  PIN dac_config_6
    ANTENNAGATEAREA 38.399998 ;
    PORT
      LAYER met3 ;
        RECT 1624.640 814.140 1625.640 815.140 ;
    END
  END dac_config_6
  PIN row_on_detect_bot[21]
    ANTENNAGATEAREA 16.128000 ;
    PORT
      LAYER met3 ;
        RECT -63.480 566.290 1.535 566.590 ;
    END
  END row_on_detect_bot[21]
  PIN dac_config_3
    ANTENNAGATEAREA 1228.799927 ;
    PORT
      LAYER met3 ;
        RECT 1624.640 822.300 1625.640 823.300 ;
    END
  END dac_config_3
  PIN row_off_detect_top[15]
    ANTENNAGATEAREA 8.064000 ;
    PORT
      LAYER met3 ;
        RECT -63.480 1405.410 1.535 1405.710 ;
    END
  END row_off_detect_top[15]
  PIN row_on_detect_top[15]
    ANTENNAGATEAREA 16.128000 ;
    PORT
      LAYER met3 ;
        RECT -63.480 1406.090 1.535 1406.390 ;
    END
  END row_on_detect_top[15]
  PIN row_off_detect_top[9]
    ANTENNAGATEAREA 8.064000 ;
    PORT
      LAYER met3 ;
        RECT -63.480 1477.490 1.535 1477.790 ;
    END
  END row_off_detect_top[9]
  PIN row_on_detect_bot[34]
    ANTENNAGATEAREA 16.128000 ;
    PORT
      LAYER met3 ;
        RECT -63.480 399.690 1.535 399.990 ;
    END
  END row_on_detect_bot[34]
  PIN row_on_detect_bot[35]
    ANTENNAGATEAREA 16.128000 ;
    PORT
      LAYER met3 ;
        RECT -63.480 398.330 1.535 398.630 ;
    END
  END row_on_detect_bot[35]
  PIN row_off_detect_bot[35]
    ANTENNAGATEAREA 8.064000 ;
    PORT
      LAYER met3 ;
        RECT -63.480 397.650 1.535 397.950 ;
    END
  END row_off_detect_bot[35]
  PIN row_off_detect_bot[25]
    ANTENNAGATEAREA 8.064000 ;
    PORT
      LAYER met3 ;
        RECT -63.480 517.330 1.535 517.630 ;
    END
  END row_off_detect_bot[25]
  PIN row_off_detect_top[55]
    ANTENNAGATEAREA 8.064000 ;
    PORT
      LAYER met3 ;
        RECT -63.480 925.330 1.535 925.630 ;
    END
  END row_off_detect_top[55]
  PIN row_on_detect_top[53]
    ANTENNAGATEAREA 16.128000 ;
    PORT
      LAYER met3 ;
        RECT -63.480 950.490 1.535 950.790 ;
    END
  END row_on_detect_top[53]
  PIN row_off_detect_bot[28]
    ANTENNAGATEAREA 8.064000 ;
    PORT
      LAYER met3 ;
        RECT -63.480 472.450 1.535 472.750 ;
    END
  END row_off_detect_bot[28]
  PIN row_on_detect_top[55]
    ANTENNAGATEAREA 16.128000 ;
    PORT
      LAYER met3 ;
        RECT -63.480 926.690 1.535 926.990 ;
    END
  END row_on_detect_top[55]
  PIN row_off_detect_top[47]
    ANTENNAGATEAREA 8.064000 ;
    PORT
      LAYER met3 ;
        RECT -63.480 1021.210 1.535 1021.510 ;
    END
  END row_off_detect_top[47]
  PIN row_on_detect_bot[38]
    ANTENNAGATEAREA 16.128000 ;
    PORT
      LAYER met3 ;
        RECT -63.480 351.410 1.535 351.710 ;
    END
  END row_on_detect_bot[38]
  PIN row_on_detect_bot[39]
    ANTENNAGATEAREA 16.128000 ;
    PORT
      LAYER met3 ;
        RECT -63.480 350.730 1.535 351.030 ;
    END
  END row_on_detect_bot[39]
  PIN row_off_detect_top[48]
    ANTENNAGATEAREA 8.064000 ;
    PORT
      LAYER met3 ;
        RECT -63.480 1000.810 1.535 1001.110 ;
    END
  END row_off_detect_top[48]
  PIN row_on_detect_top[47]
    ANTENNAGATEAREA 16.128000 ;
    PORT
      LAYER met3 ;
        RECT -63.480 1022.570 1.535 1022.870 ;
    END
  END row_on_detect_top[47]
  PIN row_on_detect_bot[57]
    ANTENNAGATEAREA 16.128000 ;
    PORT
      LAYER met3 ;
        RECT -63.480 134.490 1.535 134.790 ;
    END
  END row_on_detect_bot[57]
  PIN dac_config_1
    ANTENNAGATEAREA 36864.000000 ;
    PORT
      LAYER met3 ;
        RECT 1624.640 818.220 1625.640 819.220 ;
    END
  END dac_config_1
  PIN row_off_detect_bot[39]
    ANTENNAGATEAREA 8.064000 ;
    PORT
      LAYER met3 ;
        RECT -63.480 349.370 1.535 349.670 ;
    END
  END row_off_detect_bot[39]
  PIN row_off_detect_bot[9]
    ANTENNAGATEAREA 8.064000 ;
    PORT
      LAYER met3 ;
        RECT -63.480 709.090 1.535 709.390 ;
    END
  END row_off_detect_bot[9]
  PIN row_off_detect_bot[12]
    ANTENNAGATEAREA 8.064000 ;
    PORT
      LAYER met3 ;
        RECT -63.480 664.890 1.535 665.190 ;
    END
  END row_off_detect_bot[12]
  PIN row_on_detect_bot[18]
    ANTENNAGATEAREA 16.128000 ;
    PORT
      LAYER met3 ;
        RECT -63.480 591.450 1.535 591.750 ;
    END
  END row_on_detect_bot[18]
  PIN row_off_detect_bot[18]
    ANTENNAGATEAREA 8.064000 ;
    PORT
      LAYER met3 ;
        RECT -63.480 592.810 1.535 593.110 ;
    END
  END row_off_detect_bot[18]
  PIN row_on_detect_top[6]
    ANTENNAGATEAREA 16.128000 ;
    PORT
      LAYER met3 ;
        RECT -63.480 1503.330 1.535 1503.630 ;
    END
  END row_on_detect_top[6]
  PIN pre_charge_global_bot_left
    ANTENNAGATEAREA 1024.000000 ;
    PORT
      LAYER met3 ;
        RECT -63.480 29.755 3.040 31.115 ;
    END
  END pre_charge_global_bot_left
  PIN row_off_detect_bot[14]
    ANTENNAGATEAREA 8.064000 ;
    PORT
      LAYER met3 ;
        RECT -63.480 640.410 1.535 640.710 ;
    END
  END row_off_detect_bot[14]
  PIN row_on_detect_bot[14]
    ANTENNAGATEAREA 16.128000 ;
    PORT
      LAYER met3 ;
        RECT -63.480 639.730 1.535 640.030 ;
    END
  END row_on_detect_bot[14]
  PIN row_on_detect_top[5]
    ANTENNAGATEAREA 16.128000 ;
    PORT
      LAYER met3 ;
        RECT -63.480 1526.450 1.535 1526.750 ;
    END
  END row_on_detect_top[5]
  PIN row_off_detect_top[37]
    ANTENNAGATEAREA 8.064000 ;
    PORT
      LAYER met3 ;
        RECT -63.480 1141.570 1.535 1141.870 ;
    END
  END row_off_detect_top[37]
  PIN row_on_detect_top[39]
    ANTENNAGATEAREA 16.128000 ;
    PORT
      LAYER met3 ;
        RECT -63.480 1118.450 1.535 1118.750 ;
    END
  END row_on_detect_top[39]
  PIN row_off_detect_top[11]
    ANTENNAGATEAREA 8.064000 ;
    PORT
      LAYER met3 ;
        RECT -63.480 1453.690 1.535 1453.990 ;
    END
  END row_off_detect_top[11]
  PIN row_off_detect_bot[4]
    ANTENNAGATEAREA 8.064000 ;
    PORT
      LAYER met3 ;
        RECT -63.480 760.770 1.535 761.070 ;
    END
  END row_off_detect_bot[4]
  PIN row_on_detect_top[22]
    ANTENNAGATEAREA 16.128000 ;
    PORT
      LAYER met3 ;
        RECT -63.480 1311.570 1.535 1311.870 ;
    END
  END row_on_detect_top[22]
  PIN row_off_detect_bot[53]
    ANTENNAGATEAREA 8.064000 ;
    PORT
      LAYER met3 ;
        RECT -63.480 181.410 1.535 181.710 ;
    END
  END row_off_detect_bot[53]
  PIN row_off_detect_bot[54]
    ANTENNAGATEAREA 8.064000 ;
    PORT
      LAYER met3 ;
        RECT -63.480 161.010 1.535 161.310 ;
    END
  END row_off_detect_bot[54]
  PIN row_off_detect_top[61]
    ANTENNAGATEAREA 8.064000 ;
    PORT
      LAYER met3 ;
        RECT -63.480 853.250 1.535 853.550 ;
    END
  END row_off_detect_top[61]
  PIN row_on_detect_top[58]
    ANTENNAGATEAREA 16.128000 ;
    PORT
      LAYER met3 ;
        RECT -63.480 879.770 1.535 880.070 ;
    END
  END row_on_detect_top[58]
  PIN row_off_detect_top[58]
    ANTENNAGATEAREA 8.064000 ;
    PORT
      LAYER met3 ;
        RECT -63.480 880.450 1.535 880.750 ;
    END
  END row_off_detect_top[58]
  PIN row_off_detect_bot[37]
    ANTENNAGATEAREA 8.064000 ;
    PORT
      LAYER met3 ;
        RECT -63.480 373.170 1.535 373.470 ;
    END
  END row_off_detect_bot[37]
  PIN row_off_detect_bot[27]
    ANTENNAGATEAREA 8.064000 ;
    PORT
      LAYER met3 ;
        RECT -63.480 493.530 1.535 493.830 ;
    END
  END row_off_detect_bot[27]
  PIN row_off_detect_top[10]
    ANTENNAGATEAREA 8.064000 ;
    PORT
      LAYER met3 ;
        RECT -63.480 1456.410 1.535 1456.710 ;
    END
  END row_off_detect_top[10]
  PIN row_on_detect_top[10]
    ANTENNAGATEAREA 16.128000 ;
    PORT
      LAYER met3 ;
        RECT -63.480 1455.730 1.535 1456.030 ;
    END
  END row_on_detect_top[10]
  PIN row_on_detect_bot[22]
    ANTENNAGATEAREA 16.128000 ;
    PORT
      LAYER met3 ;
        RECT -63.480 543.850 1.535 544.150 ;
    END
  END row_on_detect_bot[22]
  PIN row_off_detect_top[13]
    ANTENNAGATEAREA 8.064000 ;
    PORT
      LAYER met3 ;
        RECT -63.480 1429.210 1.535 1429.510 ;
    END
  END row_off_detect_top[13]
  PIN row_on_detect_top[12]
    ANTENNAGATEAREA 16.128000 ;
    PORT
      LAYER met3 ;
        RECT -63.480 1431.250 1.535 1431.550 ;
    END
  END row_on_detect_top[12]
  PIN row_on_detect_bot[19]
    ANTENNAGATEAREA 16.128000 ;
    PORT
      LAYER met3 ;
        RECT -63.480 590.090 1.535 590.390 ;
    END
  END row_on_detect_bot[19]
  PIN row_off_detect_bot[15]
    ANTENNAGATEAREA 8.064000 ;
    PORT
      LAYER met3 ;
        RECT -63.480 637.690 1.535 637.990 ;
    END
  END row_off_detect_bot[15]
  PIN row_on_detect_top[20]
    ANTENNAGATEAREA 16.128000 ;
    PORT
      LAYER met3 ;
        RECT -63.480 1336.050 1.535 1336.350 ;
    END
  END row_on_detect_top[20]
  PIN row_off_detect_bot[13]
    ANTENNAGATEAREA 8.064000 ;
    PORT
      LAYER met3 ;
        RECT -63.480 661.490 1.535 661.790 ;
    END
  END row_off_detect_bot[13]
  PIN row_on_detect_bot[9]
    ANTENNAGATEAREA 16.128000 ;
    PORT
      LAYER met3 ;
        RECT -63.480 710.450 1.535 710.750 ;
    END
  END row_on_detect_bot[9]
  PIN row_on_detect_bot[8]
    ANTENNAGATEAREA 16.128000 ;
    PORT
      LAYER met3 ;
        RECT -63.480 711.810 1.535 712.110 ;
    END
  END row_on_detect_bot[8]
  PIN row_on_detect_bot[47]
    ANTENNAGATEAREA 16.128000 ;
    PORT
      LAYER met3 ;
        RECT -63.480 254.850 1.535 255.150 ;
    END
  END row_on_detect_bot[47]
  PIN row_on_detect_bot[46]
    ANTENNAGATEAREA 16.128000 ;
    PORT
      LAYER met3 ;
        RECT -63.480 255.530 1.535 255.830 ;
    END
  END row_on_detect_bot[46]
  PIN row_on_detect_bot[28]
    ANTENNAGATEAREA 16.128000 ;
    PORT
      LAYER met3 ;
        RECT -63.480 471.770 1.535 472.070 ;
    END
  END row_on_detect_bot[28]
  PIN row_off_detect_bot[20]
    ANTENNAGATEAREA 8.064000 ;
    PORT
      LAYER met3 ;
        RECT -63.480 569.010 1.535 569.310 ;
    END
  END row_off_detect_bot[20]
  PIN row_on_detect_bot[17]
    ANTENNAGATEAREA 16.128000 ;
    PORT
      LAYER met3 ;
        RECT -63.480 614.570 1.535 614.870 ;
    END
  END row_on_detect_bot[17]
  PIN row_off_detect_bot[16]
    ANTENNAGATEAREA 8.064000 ;
    PORT
      LAYER met3 ;
        RECT -63.480 616.610 1.535 616.910 ;
    END
  END row_off_detect_bot[16]
  PIN row_on_detect_bot[16]
    ANTENNAGATEAREA 16.128000 ;
    PORT
      LAYER met3 ;
        RECT -63.480 615.250 1.535 615.550 ;
    END
  END row_on_detect_bot[16]
  PIN row_on_detect_top[49]
    ANTENNAGATEAREA 16.128000 ;
    PORT
      LAYER met3 ;
        RECT -63.480 998.090 1.535 998.390 ;
    END
  END row_on_detect_top[49]
  PIN row_on_detect_bot[10]
    ANTENNAGATEAREA 16.128000 ;
    PORT
      LAYER met3 ;
        RECT -63.480 687.330 1.535 687.630 ;
    END
  END row_on_detect_bot[10]
  PIN row_off_detect_top[60]
    ANTENNAGATEAREA 8.064000 ;
    PORT
      LAYER met3 ;
        RECT -63.480 856.650 1.535 856.950 ;
    END
  END row_off_detect_top[60]
  PIN row_on_detect_bot[2]
    ANTENNAGATEAREA 16.128000 ;
    PORT
      LAYER met3 ;
        RECT -63.480 783.210 1.535 783.510 ;
    END
  END row_on_detect_bot[2]
  PIN row_off_detect_top[24]
    ANTENNAGATEAREA 8.064000 ;
    PORT
      LAYER met3 ;
        RECT -63.480 1288.450 1.535 1288.750 ;
    END
  END row_off_detect_top[24]
  PIN row_on_detect_top[3]
    ANTENNAGATEAREA 16.128000 ;
    PORT
      LAYER met3 ;
        RECT -63.480 1550.930 1.535 1551.230 ;
    END
  END row_on_detect_top[3]
  PIN row_off_detect_bot[48]
    ANTENNAGATEAREA 8.064000 ;
    PORT
      LAYER met3 ;
        RECT -63.480 232.410 1.535 232.710 ;
    END
  END row_off_detect_bot[48]
  PIN row_off_detect_bot[51]
    ANTENNAGATEAREA 8.064000 ;
    PORT
      LAYER met3 ;
        RECT -63.480 205.210 1.535 205.510 ;
    END
  END row_off_detect_bot[51]
  PIN row_off_detect_top[31]
    ANTENNAGATEAREA 8.064000 ;
    PORT
      LAYER met3 ;
        RECT -63.480 1213.650 1.535 1213.950 ;
    END
  END row_off_detect_top[31]
  PIN row_on_detect_top[31]
    ANTENNAGATEAREA 16.128000 ;
    PORT
      LAYER met3 ;
        RECT -63.480 1214.330 1.535 1214.630 ;
    END
  END row_on_detect_top[31]
  PIN row_off_detect_top[25]
    ANTENNAGATEAREA 8.064000 ;
    PORT
      LAYER met3 ;
        RECT -63.480 1285.730 1.535 1286.030 ;
    END
  END row_off_detect_top[25]
  PIN row_on_detect_bot[51]
    ANTENNAGATEAREA 16.128000 ;
    PORT
      LAYER met3 ;
        RECT -63.480 206.570 1.535 206.870 ;
    END
  END row_on_detect_bot[51]
  PIN row_on_detect_bot[50]
    ANTENNAGATEAREA 16.128000 ;
    PORT
      LAYER met3 ;
        RECT -63.480 207.250 1.535 207.550 ;
    END
  END row_on_detect_bot[50]
  PIN row_on_detect_bot[48]
    ANTENNAGATEAREA 16.128000 ;
    PORT
      LAYER met3 ;
        RECT -63.480 231.730 1.535 232.030 ;
    END
  END row_on_detect_bot[48]
  PIN ndetect_pulse_global_top_left
    ANTENNAGATEAREA 64.000000 ;
    PORT
      LAYER met3 ;
        RECT -63.480 1627.075 2.710 1628.435 ;
    END
  END ndetect_pulse_global_top_left
  PIN row_off_detect_top[2]
    ANTENNAGATEAREA 8.064000 ;
    PORT
      LAYER met3 ;
        RECT -63.480 1552.970 1.535 1553.270 ;
    END
  END row_off_detect_top[2]
  PIN row_off_detect_top[57]
    ANTENNAGATEAREA 8.064000 ;
    PORT
      LAYER met3 ;
        RECT -63.480 901.530 1.535 901.830 ;
    END
  END row_off_detect_top[57]
  PIN row_on_detect_top[56]
    ANTENNAGATEAREA 16.128000 ;
    PORT
      LAYER met3 ;
        RECT -63.480 903.570 1.535 903.870 ;
    END
  END row_on_detect_top[56]
  PIN row_on_detect_top[61]
    ANTENNAGATEAREA 16.128000 ;
    PORT
      LAYER met3 ;
        RECT -63.480 854.610 1.535 854.910 ;
    END
  END row_on_detect_top[61]
  PIN row_off_detect_top[22]
    ANTENNAGATEAREA 8.064000 ;
    PORT
      LAYER met3 ;
        RECT -63.480 1312.930 1.535 1313.230 ;
    END
  END row_off_detect_top[22]
  PIN row_off_detect_bot[58]
    ANTENNAGATEAREA 8.064000 ;
    PORT
      LAYER met3 ;
        RECT -63.480 112.730 1.535 113.030 ;
    END
  END row_off_detect_bot[58]
  PIN row_off_detect_bot[55]
    ANTENNAGATEAREA 8.064000 ;
    PORT
      LAYER met3 ;
        RECT -63.480 157.610 1.535 157.910 ;
    END
  END row_off_detect_bot[55]
  PIN row_off_detect_bot[0]
    ANTENNAGATEAREA 8.064000 ;
    PORT
      LAYER met3 ;
        RECT -63.480 808.370 1.535 808.670 ;
    END
  END row_off_detect_bot[0]
  PIN row_off_detect_top[63]
    ANTENNAGATEAREA 8.064000 ;
    PORT
      LAYER met3 ;
        RECT -63.480 829.450 1.535 829.750 ;
    END
  END row_off_detect_top[63]
  PIN row_on_detect_top[34]
    ANTENNAGATEAREA 16.128000 ;
    PORT
      LAYER met3 ;
        RECT -63.480 1167.410 1.535 1167.710 ;
    END
  END row_on_detect_top[34]
  PIN row_on_detect_top[29]
    ANTENNAGATEAREA 16.128000 ;
    PORT
      LAYER met3 ;
        RECT -63.480 1238.810 1.535 1239.110 ;
    END
  END row_on_detect_top[29]
  PIN row_off_detect_top[28]
    ANTENNAGATEAREA 8.064000 ;
    PORT
      LAYER met3 ;
        RECT -63.480 1240.850 1.535 1241.150 ;
    END
  END row_off_detect_top[28]
  PIN row_on_detect_top[27]
    ANTENNAGATEAREA 16.128000 ;
    PORT
      LAYER met3 ;
        RECT -63.480 1262.610 1.535 1262.910 ;
    END
  END row_on_detect_top[27]
  PIN row_on_detect_bot[40]
    ANTENNAGATEAREA 16.128000 ;
    PORT
      LAYER met3 ;
        RECT -63.480 327.610 1.535 327.910 ;
    END
  END row_on_detect_bot[40]
  PIN row_on_detect_bot[59]
    ANTENNAGATEAREA 16.128000 ;
    PORT
      LAYER met3 ;
        RECT -63.480 110.690 1.535 110.990 ;
    END
  END row_on_detect_bot[59]
  PIN row_off_detect_bot[57]
    ANTENNAGATEAREA 8.064000 ;
    PORT
      LAYER met3 ;
        RECT -63.480 133.130 1.535 133.430 ;
    END
  END row_off_detect_bot[57]
  PIN row_on_detect_bot[25]
    ANTENNAGATEAREA 16.128000 ;
    PORT
      LAYER met3 ;
        RECT -63.480 518.690 1.535 518.990 ;
    END
  END row_on_detect_bot[25]
  PIN row_on_detect_bot[27]
    ANTENNAGATEAREA 16.128000 ;
    PORT
      LAYER met3 ;
        RECT -63.480 494.890 1.535 495.190 ;
    END
  END row_on_detect_bot[27]
  PIN row_off_detect_bot[29]
    ANTENNAGATEAREA 8.064000 ;
    PORT
      LAYER met3 ;
        RECT -63.480 469.730 1.535 470.030 ;
    END
  END row_off_detect_bot[29]
  PIN row_off_detect_bot[30]
    ANTENNAGATEAREA 8.064000 ;
    PORT
      LAYER met3 ;
        RECT -63.480 448.650 1.535 448.950 ;
    END
  END row_off_detect_bot[30]
  PIN row_off_detect_bot[33]
    ANTENNAGATEAREA 8.064000 ;
    PORT
      LAYER met3 ;
        RECT -63.480 421.450 1.535 421.750 ;
    END
  END row_off_detect_bot[33]
  PIN row_off_detect_bot[34]
    ANTENNAGATEAREA 8.064000 ;
    PORT
      LAYER met3 ;
        RECT -63.480 400.370 1.535 400.670 ;
    END
  END row_off_detect_bot[34]
  PIN row_on_detect_bot[36]
    ANTENNAGATEAREA 16.128000 ;
    PORT
      LAYER met3 ;
        RECT -63.480 375.210 1.535 375.510 ;
    END
  END row_on_detect_bot[36]
  PIN row_on_detect_top[59]
    ANTENNAGATEAREA 16.128000 ;
    PORT
      LAYER met3 ;
        RECT -63.480 878.410 1.535 878.710 ;
    END
  END row_on_detect_top[59]
  PIN row_off_detect_bot[7]
    ANTENNAGATEAREA 8.064000 ;
    PORT
      LAYER met3 ;
        RECT -63.480 733.570 1.535 733.870 ;
    END
  END row_off_detect_bot[7]
  PIN row_on_detect_top[23]
    ANTENNAGATEAREA 16.128000 ;
    PORT
      LAYER met3 ;
        RECT -63.480 1310.890 1.535 1311.190 ;
    END
  END row_on_detect_top[23]
  PIN row_off_detect_top[20]
    ANTENNAGATEAREA 8.064000 ;
    PORT
      LAYER met3 ;
        RECT -63.480 1336.730 1.535 1337.030 ;
    END
  END row_off_detect_top[20]
  PIN row_off_detect_bot[10]
    ANTENNAGATEAREA 8.064000 ;
    PORT
      LAYER met3 ;
        RECT -63.480 688.690 1.535 688.990 ;
    END
  END row_off_detect_bot[10]
  PIN row_off_detect_bot[2]
    ANTENNAGATEAREA 8.064000 ;
    PORT
      LAYER met3 ;
        RECT -63.480 784.570 1.535 784.870 ;
    END
  END row_off_detect_bot[2]
  PIN row_off_detect_bot[1]
    ANTENNAGATEAREA 8.064000 ;
    PORT
      LAYER met3 ;
        RECT -63.480 805.650 1.535 805.950 ;
    END
  END row_off_detect_bot[1]
  PIN row_on_detect_bot[3]
    ANTENNAGATEAREA 16.128000 ;
    PORT
      LAYER met3 ;
        RECT -63.480 782.530 1.535 782.830 ;
    END
  END row_on_detect_bot[3]
  PIN row_off_detect_bot[56]
    ANTENNAGATEAREA 8.064000 ;
    PORT
      LAYER met3 ;
        RECT -63.480 136.530 1.535 136.830 ;
    END
  END row_off_detect_bot[56]
  PIN row_off_detect_bot[59]
    ANTENNAGATEAREA 8.064000 ;
    PORT
      LAYER met3 ;
        RECT -63.480 109.330 1.535 109.630 ;
    END
  END row_off_detect_bot[59]
  PIN row_off_detect_top[21]
    ANTENNAGATEAREA 8.064000 ;
    PORT
      LAYER met3 ;
        RECT -63.480 1333.330 1.535 1333.630 ;
    END
  END row_off_detect_top[21]
  PIN row_on_detect_top[62]
    ANTENNAGATEAREA 16.128000 ;
    PORT
      LAYER met3 ;
        RECT -63.480 831.490 1.535 831.790 ;
    END
  END row_on_detect_top[62]
  PIN row_off_detect_bot[38]
    ANTENNAGATEAREA 8.064000 ;
    PORT
      LAYER met3 ;
        RECT -63.480 352.770 1.535 353.070 ;
    END
  END row_off_detect_bot[38]
  PIN row_on_detect_bot[29]
    ANTENNAGATEAREA 16.128000 ;
    PORT
      LAYER met3 ;
        RECT -63.480 470.410 1.535 470.710 ;
    END
  END row_on_detect_bot[29]
  PIN row_on_detect_bot[23]
    ANTENNAGATEAREA 16.128000 ;
    PORT
      LAYER met3 ;
        RECT -63.480 542.490 1.535 542.790 ;
    END
  END row_on_detect_bot[23]
  PIN row_off_detect_bot[19]
    ANTENNAGATEAREA 8.064000 ;
    PORT
      LAYER met3 ;
        RECT -63.480 589.410 1.535 589.710 ;
    END
  END row_off_detect_bot[19]
  PIN row_on_detect_bot[15]
    ANTENNAGATEAREA 16.128000 ;
    PORT
      LAYER met3 ;
        RECT -63.480 638.370 1.535 638.670 ;
    END
  END row_on_detect_bot[15]
  PIN row_on_detect_top[21]
    ANTENNAGATEAREA 16.128000 ;
    PORT
      LAYER met3 ;
        RECT -63.480 1334.690 1.535 1334.990 ;
    END
  END row_on_detect_top[21]
  PIN row_on_detect_top[50]
    ANTENNAGATEAREA 16.128000 ;
    PORT
      LAYER met3 ;
        RECT -63.480 975.650 1.535 975.950 ;
    END
  END row_on_detect_top[50]
  PIN row_off_detect_top[49]
    ANTENNAGATEAREA 8.064000 ;
    PORT
      LAYER met3 ;
        RECT -63.480 997.410 1.535 997.710 ;
    END
  END row_off_detect_top[49]
  PIN row_on_detect_bot[12]
    ANTENNAGATEAREA 16.128000 ;
    PORT
      LAYER met3 ;
        RECT -63.480 663.530 1.535 663.830 ;
    END
  END row_on_detect_bot[12]
  PIN row_off_detect_bot[23]
    ANTENNAGATEAREA 8.064000 ;
    PORT
      LAYER met3 ;
        RECT -63.480 541.130 1.535 541.430 ;
    END
  END row_off_detect_bot[23]
  PIN row_off_detect_bot[17]
    ANTENNAGATEAREA 8.064000 ;
    PORT
      LAYER met3 ;
        RECT -63.480 613.210 1.535 613.510 ;
    END
  END row_off_detect_bot[17]
  PIN row_off_detect_top[44]
    ANTENNAGATEAREA 8.064000 ;
    PORT
      LAYER met3 ;
        RECT -63.480 1048.410 1.535 1048.710 ;
    END
  END row_off_detect_top[44]
  PIN row_on_detect_top[2]
    ANTENNAGATEAREA 16.128000 ;
    PORT
      LAYER met3 ;
        RECT -63.480 1551.610 1.535 1551.910 ;
    END
  END row_on_detect_top[2]
  PIN row_off_detect_bot[11]
    ANTENNAGATEAREA 8.064000 ;
    PORT
      LAYER met3 ;
        RECT -63.480 685.290 1.535 685.590 ;
    END
  END row_off_detect_bot[11]
  PIN row_on_detect_top[60]
    ANTENNAGATEAREA 16.128000 ;
    PORT
      LAYER met3 ;
        RECT -63.480 855.290 1.535 855.590 ;
    END
  END row_on_detect_top[60]
  PIN row_on_detect_bot[4]
    ANTENNAGATEAREA 16.128000 ;
    PORT
      LAYER met3 ;
        RECT -63.480 759.410 1.535 759.710 ;
    END
  END row_on_detect_bot[4]
  PIN row_off_detect_bot[60]
    ANTENNAGATEAREA 8.064000 ;
    PORT
      LAYER met3 ;
        RECT -63.480 88.930 1.535 89.230 ;
    END
  END row_off_detect_bot[60]
  PIN row_on_detect_bot[60]
    ANTENNAGATEAREA 16.128000 ;
    PORT
      LAYER met3 ;
        RECT -63.480 87.570 1.535 87.870 ;
    END
  END row_on_detect_bot[60]
  PIN row_off_detect_top[5]
    ANTENNAGATEAREA 8.064000 ;
    PORT
      LAYER met3 ;
        RECT -63.480 1525.090 1.535 1525.390 ;
    END
  END row_off_detect_top[5]
  PIN row_off_detect_top[27]
    ANTENNAGATEAREA 8.064000 ;
    PORT
      LAYER met3 ;
        RECT -63.480 1261.250 1.535 1261.550 ;
    END
  END row_off_detect_top[27]
  PIN row_off_detect_bot[26]
    ANTENNAGATEAREA 8.064000 ;
    PORT
      LAYER met3 ;
        RECT -63.480 496.930 1.535 497.230 ;
    END
  END row_off_detect_bot[26]
  PIN row_on_detect_bot[49]
    ANTENNAGATEAREA 16.128000 ;
    PORT
      LAYER met3 ;
        RECT -63.480 230.370 1.535 230.670 ;
    END
  END row_on_detect_bot[49]
  PIN ndetect_pulse_global_bot_left
    ANTENNAGATEAREA 64.000000 ;
    PORT
      LAYER met3 ;
        RECT -63.480 9.385 3.040 10.745 ;
    END
  END ndetect_pulse_global_bot_left
  PIN row_off_detect_top[1]
    ANTENNAGATEAREA 8.064000 ;
    PORT
      LAYER met3 ;
        RECT -63.480 1573.370 1.535 1573.670 ;
    END
  END row_off_detect_top[1]
  PIN row_on_detect_top[17]
    ANTENNAGATEAREA 16.128000 ;
    PORT
      LAYER met3 ;
        RECT -63.480 1382.290 1.535 1382.590 ;
    END
  END row_on_detect_top[17]
  PIN row_on_detect_top[16]
    ANTENNAGATEAREA 16.128000 ;
    PORT
      LAYER met3 ;
        RECT -63.480 1383.650 1.535 1383.950 ;
    END
  END row_on_detect_top[16]
  PIN row_off_detect_top[19]
    ANTENNAGATEAREA 8.064000 ;
    PORT
      LAYER met3 ;
        RECT -63.480 1357.130 1.535 1357.430 ;
    END
  END row_off_detect_top[19]
  PIN row_off_detect_top[16]
    ANTENNAGATEAREA 8.064000 ;
    PORT
      LAYER met3 ;
        RECT -63.480 1385.010 1.535 1385.310 ;
    END
  END row_off_detect_top[16]
  PIN row_off_detect_top[62]
    ANTENNAGATEAREA 8.064000 ;
    PORT
      LAYER met3 ;
        RECT -63.480 832.850 1.535 833.150 ;
    END
  END row_off_detect_top[62]
  PIN row_on_detect_bot[58]
    ANTENNAGATEAREA 16.128000 ;
    PORT
      LAYER met3 ;
        RECT -63.480 112.050 1.535 112.350 ;
    END
  END row_on_detect_bot[58]
  PIN dac_config_5
    ANTENNAGATEAREA 10321.919922 ;
    PORT
      LAYER met3 ;
        RECT 1624.640 824.340 1625.640 825.340 ;
    END
  END dac_config_5
  PIN row_on_detect_top[52]
    ANTENNAGATEAREA 16.128000 ;
    PORT
      LAYER met3 ;
        RECT -63.480 951.850 1.535 952.150 ;
    END
  END row_on_detect_top[52]
  PIN row_off_detect_top[52]
    ANTENNAGATEAREA 8.064000 ;
    PORT
      LAYER met3 ;
        RECT -63.480 952.530 1.535 952.830 ;
    END
  END row_off_detect_top[52]
  PIN row_off_detect_top[35]
    ANTENNAGATEAREA 8.064000 ;
    PORT
      LAYER met3 ;
        RECT -63.480 1165.370 1.535 1165.670 ;
    END
  END row_off_detect_top[35]
  PIN row_off_detect_top[26]
    ANTENNAGATEAREA 8.064000 ;
    PORT
      LAYER met3 ;
        RECT -63.480 1264.650 1.535 1264.950 ;
    END
  END row_off_detect_top[26]
  PIN row_on_detect_bot[41]
    ANTENNAGATEAREA 16.128000 ;
    PORT
      LAYER met3 ;
        RECT -63.480 326.930 1.535 327.230 ;
    END
  END row_on_detect_bot[41]
  PIN row_on_detect_bot[24]
    ANTENNAGATEAREA 16.128000 ;
    PORT
      LAYER met3 ;
        RECT -63.480 520.050 1.535 520.350 ;
    END
  END row_on_detect_bot[24]
  PIN row_off_detect_bot[24]
    ANTENNAGATEAREA 8.064000 ;
    PORT
      LAYER met3 ;
        RECT -63.480 520.730 1.535 521.030 ;
    END
  END row_off_detect_bot[24]
  PIN row_off_detect_top[45]
    ANTENNAGATEAREA 8.064000 ;
    PORT
      LAYER met3 ;
        RECT -63.480 1045.690 1.535 1045.990 ;
    END
  END row_off_detect_top[45]
  PIN row_on_detect_top[42]
    ANTENNAGATEAREA 16.128000 ;
    PORT
      LAYER met3 ;
        RECT -63.480 1071.530 1.535 1071.830 ;
    END
  END row_on_detect_top[42]
  PIN row_on_detect_bot[32]
    ANTENNAGATEAREA 16.128000 ;
    PORT
      LAYER met3 ;
        RECT -63.480 423.490 1.535 423.790 ;
    END
  END row_on_detect_bot[32]
  PIN row_on_detect_bot[33]
    ANTENNAGATEAREA 16.128000 ;
    PORT
      LAYER met3 ;
        RECT -63.480 422.810 1.535 423.110 ;
    END
  END row_on_detect_bot[33]
  PIN row_on_detect_bot[6]
    ANTENNAGATEAREA 16.128000 ;
    PORT
      LAYER met3 ;
        RECT -63.480 735.610 1.535 735.910 ;
    END
  END row_on_detect_bot[6]
  PIN row_on_detect_bot[37]
    ANTENNAGATEAREA 16.128000 ;
    PORT
      LAYER met3 ;
        RECT -63.480 374.530 1.535 374.830 ;
    END
  END row_on_detect_bot[37]
  PIN row_off_detect_bot[8]
    ANTENNAGATEAREA 8.064000 ;
    PORT
      LAYER met3 ;
        RECT -63.480 712.490 1.535 712.790 ;
    END
  END row_off_detect_bot[8]
  PIN row_on_detect_bot[11]
    ANTENNAGATEAREA 16.128000 ;
    PORT
      LAYER met3 ;
        RECT -63.480 686.650 1.535 686.950 ;
    END
  END row_on_detect_bot[11]
  PIN row_on_detect_bot[56]
    ANTENNAGATEAREA 16.128000 ;
    PORT
      LAYER met3 ;
        RECT -63.480 135.850 1.535 136.150 ;
    END
  END row_on_detect_bot[56]
  PIN row_off_detect_bot[3]
    ANTENNAGATEAREA 8.064000 ;
    PORT
      LAYER met3 ;
        RECT -63.480 781.170 1.535 781.470 ;
    END
  END row_off_detect_bot[3]
  PIN row_on_detect_top[63]
    ANTENNAGATEAREA 16.128000 ;
    PORT
      LAYER met3 ;
        RECT -63.480 830.810 1.535 831.110 ;
    END
  END row_on_detect_top[63]
  PIN row_on_detect_top[44]
    ANTENNAGATEAREA 16.128000 ;
    PORT
      LAYER met3 ;
        RECT -63.480 1047.730 1.535 1048.030 ;
    END
  END row_on_detect_top[44]
  PIN row_on_detect_top[45]
    ANTENNAGATEAREA 16.128000 ;
    PORT
      LAYER met3 ;
        RECT -63.480 1046.370 1.535 1046.670 ;
    END
  END row_on_detect_top[45]
  PIN row_on_detect_bot[61]
    ANTENNAGATEAREA 16.128000 ;
    PORT
      LAYER met3 ;
        RECT -63.480 86.890 1.535 87.190 ;
    END
  END row_on_detect_bot[61]
  PIN row_off_detect_bot[61]
    ANTENNAGATEAREA 8.064000 ;
    PORT
      LAYER met3 ;
        RECT -63.480 85.530 1.535 85.830 ;
    END
  END row_off_detect_bot[61]
  PIN row_on_detect_bot[44]
    ANTENNAGATEAREA 16.128000 ;
    PORT
      LAYER met3 ;
        RECT -63.480 279.330 1.535 279.630 ;
    END
  END row_on_detect_bot[44]
  PIN row_on_detect_bot[45]
    ANTENNAGATEAREA 16.128000 ;
    PORT
      LAYER met3 ;
        RECT -63.480 278.650 1.535 278.950 ;
    END
  END row_on_detect_bot[45]
  PIN row_on_detect_bot[52]
    ANTENNAGATEAREA 16.128000 ;
    PORT
      LAYER met3 ;
        RECT -63.480 183.450 1.535 183.750 ;
    END
  END row_on_detect_bot[52]
  PIN row_on_detect_bot[53]
    ANTENNAGATEAREA 16.128000 ;
    PORT
      LAYER met3 ;
        RECT -63.480 182.090 1.535 182.390 ;
    END
  END row_on_detect_bot[53]
  PIN row_off_detect_bot[41]
    ANTENNAGATEAREA 8.064000 ;
    PORT
      LAYER met3 ;
        RECT -63.480 325.570 1.535 325.870 ;
    END
  END row_off_detect_bot[41]
  PIN row_off_detect_bot[42]
    ANTENNAGATEAREA 8.064000 ;
    PORT
      LAYER met3 ;
        RECT -63.480 304.490 1.535 304.790 ;
    END
  END row_off_detect_bot[42]
  PIN row_on_detect_bot[42]
    ANTENNAGATEAREA 16.128000 ;
    PORT
      LAYER met3 ;
        RECT -63.480 303.810 1.535 304.110 ;
    END
  END row_on_detect_bot[42]
  PIN row_on_detect_bot[43]
    ANTENNAGATEAREA 16.128000 ;
    PORT
      LAYER met3 ;
        RECT -63.480 302.450 1.535 302.750 ;
    END
  END row_on_detect_bot[43]
  PIN row_off_detect_bot[45]
    ANTENNAGATEAREA 8.064000 ;
    PORT
      LAYER met3 ;
        RECT -63.480 277.290 1.535 277.590 ;
    END
  END row_off_detect_bot[45]
  PIN row_off_detect_bot[47]
    ANTENNAGATEAREA 8.064000 ;
    PORT
      LAYER met3 ;
        RECT -63.480 253.490 1.535 253.790 ;
    END
  END row_off_detect_bot[47]
  PIN row_on_detect_top[40]
    ANTENNAGATEAREA 16.128000 ;
    PORT
      LAYER met3 ;
        RECT -63.480 1095.330 1.535 1095.630 ;
    END
  END row_on_detect_top[40]
  PIN row_off_detect_top[39]
    ANTENNAGATEAREA 8.064000 ;
    PORT
      LAYER met3 ;
        RECT -63.480 1117.090 1.535 1117.390 ;
    END
  END row_off_detect_top[39]
  PIN row_on_detect_top[57]
    ANTENNAGATEAREA 16.128000 ;
    PORT
      LAYER met3 ;
        RECT -63.480 902.890 1.535 903.190 ;
    END
  END row_on_detect_top[57]
  PIN row_off_detect_top[54]
    ANTENNAGATEAREA 8.064000 ;
    PORT
      LAYER met3 ;
        RECT -63.480 928.730 1.535 929.030 ;
    END
  END row_off_detect_top[54]
  PIN row_on_detect_top[54]
    ANTENNAGATEAREA 16.128000 ;
    PORT
      LAYER met3 ;
        RECT -63.480 928.050 1.535 928.350 ;
    END
  END row_on_detect_top[54]
  PIN row_off_detect_top[50]
    ANTENNAGATEAREA 8.064000 ;
    PORT
      LAYER met3 ;
        RECT -63.480 977.010 1.535 977.310 ;
    END
  END row_off_detect_top[50]
  PIN row_on_detect_top[48]
    ANTENNAGATEAREA 16.128000 ;
    PORT
      LAYER met3 ;
        RECT -63.480 999.450 1.535 999.750 ;
    END
  END row_on_detect_top[48]
  PIN row_on_detect_top[46]
    ANTENNAGATEAREA 16.128000 ;
    PORT
      LAYER met3 ;
        RECT -63.480 1023.250 1.535 1023.550 ;
    END
  END row_on_detect_top[46]
  PIN row_on_detect_top[43]
    ANTENNAGATEAREA 16.128000 ;
    PORT
      LAYER met3 ;
        RECT -63.480 1070.850 1.535 1071.150 ;
    END
  END row_on_detect_top[43]
  PIN row_off_detect_top[42]
    ANTENNAGATEAREA 8.064000 ;
    PORT
      LAYER met3 ;
        RECT -63.480 1072.890 1.535 1073.190 ;
    END
  END row_off_detect_top[42]
  PIN row_off_detect_top[41]
    ANTENNAGATEAREA 8.064000 ;
    PORT
      LAYER met3 ;
        RECT -63.480 1093.290 1.535 1093.590 ;
    END
  END row_off_detect_top[41]
  PIN row_off_detect_top[51]
    ANTENNAGATEAREA 8.064000 ;
    PORT
      LAYER met3 ;
        RECT -63.480 973.610 1.535 973.910 ;
    END
  END row_off_detect_top[51]
  PIN row_on_detect_top[51]
    ANTENNAGATEAREA 16.128000 ;
    PORT
      LAYER met3 ;
        RECT -63.480 974.290 1.535 974.590 ;
    END
  END row_on_detect_top[51]
  PIN row_on_detect_top[37]
    ANTENNAGATEAREA 16.128000 ;
    PORT
      LAYER met3 ;
        RECT -63.480 1142.930 1.535 1143.230 ;
    END
  END row_on_detect_top[37]
  PIN row_off_detect_top[36]
    ANTENNAGATEAREA 8.064000 ;
    PORT
      LAYER met3 ;
        RECT -63.480 1144.970 1.535 1145.270 ;
    END
  END row_off_detect_top[36]
  PIN row_on_detect_top[32]
    ANTENNAGATEAREA 16.128000 ;
    PORT
      LAYER met3 ;
        RECT -63.480 1191.210 1.535 1191.510 ;
    END
  END row_on_detect_top[32]
  PIN row_off_detect_top[33]
    ANTENNAGATEAREA 8.064000 ;
    PORT
      LAYER met3 ;
        RECT -63.480 1189.170 1.535 1189.470 ;
    END
  END row_off_detect_top[33]
  PIN row_on_detect_top[26]
    ANTENNAGATEAREA 16.128000 ;
    PORT
      LAYER met3 ;
        RECT -63.480 1263.290 1.535 1263.590 ;
    END
  END row_on_detect_top[26]
  PIN row_off_detect_top[56]
    ANTENNAGATEAREA 8.064000 ;
    PORT
      LAYER met3 ;
        RECT -63.480 904.930 1.535 905.230 ;
    END
  END row_off_detect_top[56]
  PIN row_off_detect_bot[6]
    ANTENNAGATEAREA 8.064000 ;
    PORT
      LAYER met3 ;
        RECT -63.480 736.970 1.535 737.270 ;
    END
  END row_off_detect_bot[6]
  PIN row_off_detect_bot[5]
    ANTENNAGATEAREA 8.064000 ;
    PORT
      LAYER met3 ;
        RECT -63.480 757.370 1.535 757.670 ;
    END
  END row_off_detect_bot[5]
  PIN row_on_detect_bot[30]
    ANTENNAGATEAREA 16.128000 ;
    PORT
      LAYER met3 ;
        RECT -63.480 447.290 1.535 447.590 ;
    END
  END row_on_detect_bot[30]
  PIN row_on_detect_bot[31]
    ANTENNAGATEAREA 16.128000 ;
    PORT
      LAYER met3 ;
        RECT -63.480 446.610 1.535 446.910 ;
    END
  END row_on_detect_bot[31]
  PIN row_off_detect_bot[31]
    ANTENNAGATEAREA 8.064000 ;
    PORT
      LAYER met3 ;
        RECT -63.480 445.250 1.535 445.550 ;
    END
  END row_off_detect_bot[31]
  PIN row_off_detect_bot[32]
    ANTENNAGATEAREA 8.064000 ;
    PORT
      LAYER met3 ;
        RECT -63.480 424.850 1.535 425.150 ;
    END
  END row_off_detect_bot[32]
  PIN row_off_detect_top[18]
    ANTENNAGATEAREA 8.064000 ;
    PORT
      LAYER met3 ;
        RECT -63.480 1360.530 1.535 1360.830 ;
    END
  END row_off_detect_top[18]
  PIN row_off_detect_top[17]
    ANTENNAGATEAREA 8.064000 ;
    PORT
      LAYER met3 ;
        RECT -63.480 1381.610 1.535 1381.910 ;
    END
  END row_off_detect_top[17]
  PIN row_off_detect_top[23]
    ANTENNAGATEAREA 8.064000 ;
    PORT
      LAYER met3 ;
        RECT -63.480 1309.530 1.535 1309.830 ;
    END
  END row_off_detect_top[23]
  PIN row_off_detect_top[4]
    ANTENNAGATEAREA 8.064000 ;
    PORT
      LAYER met3 ;
        RECT -63.480 1528.490 1.535 1528.790 ;
    END
  END row_off_detect_top[4]
  PIN row_off_detect_top[3]
    ANTENNAGATEAREA 8.064000 ;
    PORT
      LAYER met3 ;
        RECT -63.480 1549.570 1.535 1549.870 ;
    END
  END row_off_detect_top[3]
  PIN row_off_detect_top[59]
    ANTENNAGATEAREA 8.064000 ;
    PORT
      LAYER met3 ;
        RECT -63.480 877.730 1.535 878.030 ;
    END
  END row_off_detect_top[59]
  PIN row_off_detect_bot[43]
    ANTENNAGATEAREA 8.064000 ;
    PORT
      LAYER met3 ;
        RECT -63.480 301.090 1.535 301.390 ;
    END
  END row_off_detect_bot[43]
  PIN row_off_detect_bot[44]
    ANTENNAGATEAREA 8.064000 ;
    PORT
      LAYER met3 ;
        RECT -63.480 280.690 1.535 280.990 ;
    END
  END row_off_detect_bot[44]
  PIN row_on_detect_bot[63]
    ANTENNAGATEAREA 16.128000 ;
    PORT
      LAYER met3 ;
        RECT -63.480 62.410 1.535 62.710 ;
    END
  END row_on_detect_bot[63]
  PIN row_off_detect_bot[63]
    ANTENNAGATEAREA 8.064000 ;
    PORT
      LAYER met3 ;
        RECT -63.480 61.730 1.535 62.030 ;
    END
  END row_off_detect_bot[63]
  PIN row_on_detect_top[33]
    ANTENNAGATEAREA 16.128000 ;
    PORT
      LAYER met3 ;
        RECT -63.480 1190.530 1.535 1190.830 ;
    END
  END row_on_detect_top[33]
  PIN row_off_detect_top[32]
    ANTENNAGATEAREA 8.064000 ;
    PORT
      LAYER met3 ;
        RECT -63.480 1192.570 1.535 1192.870 ;
    END
  END row_off_detect_top[32]
  PIN row_on_detect_top[0]
    ANTENNAGATEAREA 16.128000 ;
    PORT
      LAYER met3 ;
        RECT -63.480 1575.410 1.535 1575.710 ;
    END
  END row_on_detect_top[0]
  PIN row_on_detect_top[7]
    ANTENNAGATEAREA 16.128000 ;
    PORT
      LAYER met3 ;
        RECT -63.480 1502.650 1.535 1502.950 ;
    END
  END row_on_detect_top[7]
  PIN row_off_detect_top[6]
    ANTENNAGATEAREA 8.064000 ;
    PORT
      LAYER met3 ;
        RECT -63.480 1504.690 1.535 1504.990 ;
    END
  END row_off_detect_top[6]
  PIN row_off_detect_bot[46]
    ANTENNAGATEAREA 8.064000 ;
    PORT
      LAYER met3 ;
        RECT -63.480 256.890 1.535 257.190 ;
    END
  END row_off_detect_bot[46]
  PIN row_off_detect_bot[49]
    ANTENNAGATEAREA 8.064000 ;
    PORT
      LAYER met3 ;
        RECT -63.480 229.690 1.535 229.990 ;
    END
  END row_off_detect_bot[49]
  PIN dac_config_4
    ANTENNAGATEAREA 10321.919922 ;
    PORT
      LAYER met3 ;
        RECT 1624.640 820.260 1625.640 821.260 ;
    END
  END dac_config_4
  PIN row_on_detect_bot[54]
    ANTENNAGATEAREA 16.128000 ;
    PORT
      LAYER met3 ;
        RECT -63.480 159.650 1.535 159.950 ;
    END
  END row_on_detect_bot[54]
  PIN row_on_detect_bot[55]
    ANTENNAGATEAREA 16.128000 ;
    PORT
      LAYER met3 ;
        RECT -63.480 158.290 1.535 158.590 ;
    END
  END row_on_detect_bot[55]
  PIN row_off_detect_bot[62]
    ANTENNAGATEAREA 8.064000 ;
    PORT
      LAYER met3 ;
        RECT -63.480 64.450 1.535 64.750 ;
    END
  END row_off_detect_bot[62]
  PIN row_on_detect_bot[62]
    ANTENNAGATEAREA 16.128000 ;
    PORT
      LAYER met3 ;
        RECT -63.480 63.770 1.535 64.070 ;
    END
  END row_on_detect_bot[62]
  PIN row_off_detect_top[0]
    ANTENNAGATEAREA 8.064000 ;
    PORT
      LAYER met3 ;
        RECT -63.480 1576.770 1.535 1577.070 ;
    END
  END row_off_detect_top[0]
  OBS
      LAYER nwell ;
        RECT -0.940 -0.005 1542.320 1638.445 ;
      LAYER li1 ;
        RECT -0.605 0.125 1541.985 1638.315 ;
      LAYER met1 ;
        RECT -0.665 1637.790 2.410 1638.070 ;
        RECT 1605.280 1637.790 1625.000 1638.070 ;
        RECT -0.665 0.650 1625.000 1637.790 ;
        RECT -0.665 0.370 2.410 0.650 ;
        RECT 1605.280 0.370 1625.000 0.650 ;
      LAYER met2 ;
        RECT 0.765 -50.000 1625.640 1663.015 ;
      LAYER met3 ;
        RECT -64.615 1638.775 1625.000 1663.015 ;
        RECT -64.615 1637.675 1538.850 1638.775 ;
        RECT 1543.350 1637.675 1625.000 1638.775 ;
        RECT -64.615 1628.835 1625.000 1637.675 ;
        RECT -64.615 1626.675 -63.880 1628.835 ;
        RECT 3.110 1626.675 1625.000 1628.835 ;
        RECT -64.615 1620.705 1625.000 1626.675 ;
        RECT -64.615 1618.545 -63.880 1620.705 ;
        RECT 3.110 1618.545 1625.000 1620.705 ;
        RECT -64.615 1609.115 1625.000 1618.545 ;
        RECT -64.615 1606.955 -63.880 1609.115 ;
        RECT 3.110 1606.955 1625.000 1609.115 ;
        RECT -64.615 1577.470 1625.000 1606.955 ;
        RECT -64.615 1576.370 -63.880 1577.470 ;
        RECT 1.935 1576.370 1625.000 1577.470 ;
        RECT -64.615 1576.110 1625.000 1576.370 ;
        RECT -64.615 1574.330 -63.880 1576.110 ;
        RECT 1.935 1574.330 1625.000 1576.110 ;
        RECT -64.615 1574.070 1625.000 1574.330 ;
        RECT -64.615 1572.970 -63.880 1574.070 ;
        RECT 1.935 1572.970 1625.000 1574.070 ;
        RECT -64.615 1553.670 1625.000 1572.970 ;
        RECT -64.615 1552.570 -63.880 1553.670 ;
        RECT 1.935 1552.570 1625.000 1553.670 ;
        RECT -64.615 1552.310 1625.000 1552.570 ;
        RECT -64.615 1550.530 -63.880 1552.310 ;
        RECT 1.935 1550.530 1625.000 1552.310 ;
        RECT -64.615 1550.270 1625.000 1550.530 ;
        RECT -64.615 1549.170 -63.880 1550.270 ;
        RECT 1.935 1549.170 1625.000 1550.270 ;
        RECT -64.615 1529.190 1625.000 1549.170 ;
        RECT -64.615 1527.410 -63.880 1529.190 ;
        RECT 1.935 1527.410 1625.000 1529.190 ;
        RECT -64.615 1527.150 1625.000 1527.410 ;
        RECT -64.615 1526.050 -63.880 1527.150 ;
        RECT 1.935 1526.050 1625.000 1527.150 ;
        RECT -64.615 1525.790 1625.000 1526.050 ;
        RECT -64.615 1524.690 -63.880 1525.790 ;
        RECT 1.935 1524.690 1625.000 1525.790 ;
        RECT -64.615 1505.390 1625.000 1524.690 ;
        RECT -64.615 1504.290 -63.880 1505.390 ;
        RECT 1.935 1504.290 1625.000 1505.390 ;
        RECT -64.615 1504.030 1625.000 1504.290 ;
        RECT -64.615 1502.250 -63.880 1504.030 ;
        RECT 1.935 1502.250 1625.000 1504.030 ;
        RECT -64.615 1501.990 1625.000 1502.250 ;
        RECT -64.615 1500.890 -63.880 1501.990 ;
        RECT 1.935 1500.890 1625.000 1501.990 ;
        RECT -64.615 1481.590 1625.000 1500.890 ;
        RECT -64.615 1480.490 -63.880 1481.590 ;
        RECT 1.935 1480.490 1625.000 1481.590 ;
        RECT -64.615 1480.230 1625.000 1480.490 ;
        RECT -64.615 1478.450 -63.880 1480.230 ;
        RECT 1.935 1478.450 1625.000 1480.230 ;
        RECT -64.615 1478.190 1625.000 1478.450 ;
        RECT -64.615 1477.090 -63.880 1478.190 ;
        RECT 1.935 1477.090 1625.000 1478.190 ;
        RECT -64.615 1457.110 1625.000 1477.090 ;
        RECT -64.615 1455.330 -63.880 1457.110 ;
        RECT 1.935 1455.330 1625.000 1457.110 ;
        RECT -64.615 1455.070 1625.000 1455.330 ;
        RECT -64.615 1453.290 -63.880 1455.070 ;
        RECT 1.935 1453.290 1625.000 1455.070 ;
        RECT -64.615 1433.310 1625.000 1453.290 ;
        RECT -64.615 1432.210 -63.880 1433.310 ;
        RECT 1.935 1432.210 1625.000 1433.310 ;
        RECT -64.615 1431.950 1625.000 1432.210 ;
        RECT -64.615 1430.170 -63.880 1431.950 ;
        RECT 1.935 1430.170 1625.000 1431.950 ;
        RECT -64.615 1429.910 1625.000 1430.170 ;
        RECT -64.615 1428.810 -63.880 1429.910 ;
        RECT 1.935 1428.810 1625.000 1429.910 ;
        RECT -64.615 1409.510 1625.000 1428.810 ;
        RECT -64.615 1408.410 -63.880 1409.510 ;
        RECT 1.935 1408.410 1625.000 1409.510 ;
        RECT -64.615 1408.150 1625.000 1408.410 ;
        RECT -64.615 1407.050 -63.880 1408.150 ;
        RECT 1.935 1407.050 1625.000 1408.150 ;
        RECT -64.615 1406.790 1625.000 1407.050 ;
        RECT -64.615 1405.010 -63.880 1406.790 ;
        RECT 1.935 1405.010 1625.000 1406.790 ;
        RECT -64.615 1385.710 1625.000 1405.010 ;
        RECT -64.615 1384.610 -63.880 1385.710 ;
        RECT 1.935 1384.610 1625.000 1385.710 ;
        RECT -64.615 1384.350 1625.000 1384.610 ;
        RECT -64.615 1383.250 -63.880 1384.350 ;
        RECT 1.935 1383.250 1625.000 1384.350 ;
        RECT -64.615 1382.990 1625.000 1383.250 ;
        RECT -64.615 1381.210 -63.880 1382.990 ;
        RECT 1.935 1381.210 1625.000 1382.990 ;
        RECT -64.615 1361.230 1625.000 1381.210 ;
        RECT -64.615 1359.450 -63.880 1361.230 ;
        RECT 1.935 1359.450 1625.000 1361.230 ;
        RECT -64.615 1359.190 1625.000 1359.450 ;
        RECT -64.615 1358.090 -63.880 1359.190 ;
        RECT 1.935 1358.090 1625.000 1359.190 ;
        RECT -64.615 1357.830 1625.000 1358.090 ;
        RECT -64.615 1356.730 -63.880 1357.830 ;
        RECT 1.935 1356.730 1625.000 1357.830 ;
        RECT -64.615 1337.430 1625.000 1356.730 ;
        RECT -64.615 1335.650 -63.880 1337.430 ;
        RECT 1.935 1335.650 1625.000 1337.430 ;
        RECT -64.615 1335.390 1625.000 1335.650 ;
        RECT -64.615 1334.290 -63.880 1335.390 ;
        RECT 1.935 1334.290 1625.000 1335.390 ;
        RECT -64.615 1334.030 1625.000 1334.290 ;
        RECT -64.615 1332.930 -63.880 1334.030 ;
        RECT 1.935 1332.930 1625.000 1334.030 ;
        RECT -64.615 1313.630 1625.000 1332.930 ;
        RECT -64.615 1312.530 -63.880 1313.630 ;
        RECT 1.935 1312.530 1625.000 1313.630 ;
        RECT -64.615 1312.270 1625.000 1312.530 ;
        RECT -64.615 1310.490 -63.880 1312.270 ;
        RECT 1.935 1310.490 1625.000 1312.270 ;
        RECT -64.615 1310.230 1625.000 1310.490 ;
        RECT -64.615 1309.130 -63.880 1310.230 ;
        RECT 1.935 1309.130 1625.000 1310.230 ;
        RECT -64.615 1289.150 1625.000 1309.130 ;
        RECT -64.615 1287.370 -63.880 1289.150 ;
        RECT 1.935 1287.370 1625.000 1289.150 ;
        RECT -64.615 1287.110 1625.000 1287.370 ;
        RECT -64.615 1285.330 -63.880 1287.110 ;
        RECT 1.935 1285.330 1625.000 1287.110 ;
        RECT -64.615 1265.350 1625.000 1285.330 ;
        RECT -64.615 1264.250 -63.880 1265.350 ;
        RECT 1.935 1264.250 1625.000 1265.350 ;
        RECT -64.615 1263.990 1625.000 1264.250 ;
        RECT -64.615 1262.210 -63.880 1263.990 ;
        RECT 1.935 1262.210 1625.000 1263.990 ;
        RECT -64.615 1261.950 1625.000 1262.210 ;
        RECT -64.615 1260.850 -63.880 1261.950 ;
        RECT 1.935 1260.850 1625.000 1261.950 ;
        RECT -64.615 1241.550 1625.000 1260.850 ;
        RECT -64.615 1240.450 -63.880 1241.550 ;
        RECT 1.935 1240.450 1625.000 1241.550 ;
        RECT -64.615 1240.190 1625.000 1240.450 ;
        RECT -64.615 1239.110 -63.880 1240.190 ;
        RECT -64.615 1238.810 -63.480 1239.110 ;
        RECT -64.615 1238.410 -63.880 1238.810 ;
        RECT 1.935 1238.410 1625.000 1240.190 ;
        RECT -64.615 1238.150 1625.000 1238.410 ;
        RECT -64.615 1237.050 -63.880 1238.150 ;
        RECT 1.935 1237.050 1625.000 1238.150 ;
        RECT -64.615 1217.070 1625.000 1237.050 ;
        RECT -64.615 1215.290 -63.880 1217.070 ;
        RECT 1.935 1215.290 1625.000 1217.070 ;
        RECT -64.615 1215.030 1625.000 1215.290 ;
        RECT -64.615 1213.250 -63.880 1215.030 ;
        RECT 1.935 1213.250 1625.000 1215.030 ;
        RECT -64.615 1193.270 1625.000 1213.250 ;
        RECT -64.615 1192.170 -63.880 1193.270 ;
        RECT 1.935 1192.170 1625.000 1193.270 ;
        RECT -64.615 1191.910 1625.000 1192.170 ;
        RECT -64.615 1190.130 -63.880 1191.910 ;
        RECT 1.935 1190.130 1625.000 1191.910 ;
        RECT -64.615 1189.870 1625.000 1190.130 ;
        RECT -64.615 1188.770 -63.880 1189.870 ;
        RECT 1.935 1188.770 1625.000 1189.870 ;
        RECT -64.615 1169.470 1625.000 1188.770 ;
        RECT -64.615 1168.370 -63.880 1169.470 ;
        RECT 1.935 1168.370 1625.000 1169.470 ;
        RECT -64.615 1168.110 1625.000 1168.370 ;
        RECT -64.615 1166.330 -63.880 1168.110 ;
        RECT 1.935 1166.330 1625.000 1168.110 ;
        RECT -64.615 1166.070 1625.000 1166.330 ;
        RECT -64.615 1164.970 -63.880 1166.070 ;
        RECT 1.935 1164.970 1625.000 1166.070 ;
        RECT -64.615 1145.670 1625.000 1164.970 ;
        RECT -64.615 1144.570 -63.880 1145.670 ;
        RECT 1.935 1144.570 1625.000 1145.670 ;
        RECT -64.615 1144.310 1625.000 1144.570 ;
        RECT -64.615 1142.530 -63.880 1144.310 ;
        RECT 1.935 1142.530 1625.000 1144.310 ;
        RECT -64.615 1142.270 1625.000 1142.530 ;
        RECT -64.615 1141.170 -63.880 1142.270 ;
        RECT 1.935 1141.170 1625.000 1142.270 ;
        RECT -64.615 1121.190 1625.000 1141.170 ;
        RECT -64.615 1119.410 -63.880 1121.190 ;
        RECT 1.935 1119.410 1625.000 1121.190 ;
        RECT -64.615 1119.150 1625.000 1119.410 ;
        RECT -64.615 1118.050 -63.880 1119.150 ;
        RECT 1.935 1118.050 1625.000 1119.150 ;
        RECT -64.615 1117.790 1625.000 1118.050 ;
        RECT -64.615 1116.690 -63.880 1117.790 ;
        RECT 1.935 1116.690 1625.000 1117.790 ;
        RECT -64.615 1097.390 1625.000 1116.690 ;
        RECT -64.615 1096.290 -63.880 1097.390 ;
        RECT 1.935 1096.290 1625.000 1097.390 ;
        RECT -64.615 1096.030 1625.000 1096.290 ;
        RECT -64.615 1094.250 -63.880 1096.030 ;
        RECT 1.935 1094.250 1625.000 1096.030 ;
        RECT -64.615 1093.990 1625.000 1094.250 ;
        RECT -64.615 1092.890 -63.880 1093.990 ;
        RECT 1.935 1092.890 1625.000 1093.990 ;
        RECT -64.615 1073.590 1625.000 1092.890 ;
        RECT -64.615 1072.490 -63.880 1073.590 ;
        RECT 1.935 1072.490 1625.000 1073.590 ;
        RECT -64.615 1072.230 1625.000 1072.490 ;
        RECT -64.615 1070.450 -63.880 1072.230 ;
        RECT 1.935 1070.450 1625.000 1072.230 ;
        RECT -64.615 1070.190 1625.000 1070.450 ;
        RECT -64.615 1069.090 -63.880 1070.190 ;
        RECT 1.935 1069.090 1625.000 1070.190 ;
        RECT -64.615 1049.110 1625.000 1069.090 ;
        RECT -64.615 1047.330 -63.880 1049.110 ;
        RECT 1.935 1047.330 1625.000 1049.110 ;
        RECT -64.615 1047.070 1625.000 1047.330 ;
        RECT -64.615 1045.290 -63.880 1047.070 ;
        RECT 1.935 1045.290 1625.000 1047.070 ;
        RECT -64.615 1025.310 1625.000 1045.290 ;
        RECT -64.615 1024.210 -63.880 1025.310 ;
        RECT 1.935 1024.210 1625.000 1025.310 ;
        RECT -64.615 1023.950 1625.000 1024.210 ;
        RECT -64.615 1022.170 -63.880 1023.950 ;
        RECT 1.935 1022.170 1625.000 1023.950 ;
        RECT -64.615 1021.910 1625.000 1022.170 ;
        RECT -64.615 1020.810 -63.880 1021.910 ;
        RECT 1.935 1020.810 1625.000 1021.910 ;
        RECT -64.615 1001.510 1625.000 1020.810 ;
        RECT -64.615 1000.410 -63.880 1001.510 ;
        RECT 1.935 1000.410 1625.000 1001.510 ;
        RECT -64.615 1000.150 1625.000 1000.410 ;
        RECT -64.615 999.050 -63.880 1000.150 ;
        RECT 1.935 999.050 1625.000 1000.150 ;
        RECT -64.615 998.790 1625.000 999.050 ;
        RECT -64.615 997.010 -63.880 998.790 ;
        RECT 1.935 997.010 1625.000 998.790 ;
        RECT -64.615 977.710 1625.000 997.010 ;
        RECT -64.615 976.610 -63.880 977.710 ;
        RECT 1.935 976.610 1625.000 977.710 ;
        RECT -64.615 976.350 1625.000 976.610 ;
        RECT -64.615 975.250 -63.880 976.350 ;
        RECT 1.935 975.250 1625.000 976.350 ;
        RECT -64.615 974.990 1625.000 975.250 ;
        RECT -64.615 973.210 -63.880 974.990 ;
        RECT 1.935 973.210 1625.000 974.990 ;
        RECT -64.615 953.230 1625.000 973.210 ;
        RECT -64.615 951.450 -63.880 953.230 ;
        RECT 1.935 951.450 1625.000 953.230 ;
        RECT -64.615 951.190 1625.000 951.450 ;
        RECT -64.615 950.090 -63.880 951.190 ;
        RECT 1.935 950.090 1625.000 951.190 ;
        RECT -64.615 949.830 1625.000 950.090 ;
        RECT -64.615 948.730 -63.880 949.830 ;
        RECT 1.935 948.730 1625.000 949.830 ;
        RECT -64.615 929.430 1625.000 948.730 ;
        RECT -64.615 927.650 -63.880 929.430 ;
        RECT 1.935 927.650 1625.000 929.430 ;
        RECT -64.615 927.390 1625.000 927.650 ;
        RECT -64.615 926.290 -63.880 927.390 ;
        RECT 1.935 926.290 1625.000 927.390 ;
        RECT -64.615 926.030 1625.000 926.290 ;
        RECT -64.615 924.930 -63.880 926.030 ;
        RECT 1.935 924.930 1625.000 926.030 ;
        RECT -64.615 905.630 1625.000 924.930 ;
        RECT -64.615 904.530 -63.880 905.630 ;
        RECT 1.935 904.530 1625.000 905.630 ;
        RECT -64.615 904.270 1625.000 904.530 ;
        RECT -64.615 902.490 -63.880 904.270 ;
        RECT 1.935 902.490 1625.000 904.270 ;
        RECT -64.615 902.230 1625.000 902.490 ;
        RECT -64.615 901.130 -63.880 902.230 ;
        RECT 1.935 901.130 1625.000 902.230 ;
        RECT -64.615 881.150 1625.000 901.130 ;
        RECT -64.615 879.370 -63.880 881.150 ;
        RECT 1.935 879.370 1625.000 881.150 ;
        RECT -64.615 879.110 1625.000 879.370 ;
        RECT -64.615 877.330 -63.880 879.110 ;
        RECT 1.935 877.330 1625.000 879.110 ;
        RECT -64.615 857.350 1625.000 877.330 ;
        RECT -64.615 856.250 -63.880 857.350 ;
        RECT 1.935 856.250 1625.000 857.350 ;
        RECT -64.615 855.990 1625.000 856.250 ;
        RECT -64.615 854.210 -63.880 855.990 ;
        RECT 1.935 854.210 1625.000 855.990 ;
        RECT -64.615 853.950 1625.000 854.210 ;
        RECT -64.615 852.850 -63.880 853.950 ;
        RECT 1.935 852.850 1625.000 853.950 ;
        RECT -64.615 833.550 1625.000 852.850 ;
        RECT -64.615 832.450 -63.880 833.550 ;
        RECT 1.935 832.450 1625.000 833.550 ;
        RECT -64.615 832.190 1625.000 832.450 ;
        RECT -64.615 831.110 -63.880 832.190 ;
        RECT -64.615 830.810 -63.480 831.110 ;
        RECT -64.615 830.410 -63.880 830.810 ;
        RECT 1.935 830.410 1625.000 832.190 ;
        RECT -64.615 830.150 1625.000 830.410 ;
        RECT -64.615 829.050 -63.880 830.150 ;
        RECT 1.935 829.050 1625.000 830.150 ;
        RECT -64.615 827.780 1625.000 829.050 ;
        RECT -64.615 825.980 1624.240 827.780 ;
        RECT -64.615 825.740 1625.000 825.980 ;
        RECT -64.615 823.940 1624.240 825.740 ;
        RECT -64.615 823.700 1625.000 823.940 ;
        RECT -64.615 821.900 1624.240 823.700 ;
        RECT -64.615 821.660 1625.000 821.900 ;
        RECT -64.615 819.860 1624.240 821.660 ;
        RECT -64.615 819.620 1625.000 819.860 ;
        RECT -64.615 817.820 1624.240 819.620 ;
        RECT -64.615 817.580 1625.000 817.820 ;
        RECT -64.615 815.780 1624.240 817.580 ;
        RECT -64.615 815.540 1625.000 815.780 ;
        RECT -64.615 813.740 1624.240 815.540 ;
        RECT -64.615 809.070 1625.000 813.740 ;
        RECT -64.615 807.290 -63.880 809.070 ;
        RECT 1.935 807.290 1625.000 809.070 ;
        RECT -64.615 807.030 1625.000 807.290 ;
        RECT -64.615 805.250 -63.880 807.030 ;
        RECT 1.935 805.250 1625.000 807.030 ;
        RECT -64.615 785.270 1625.000 805.250 ;
        RECT -64.615 784.170 -63.880 785.270 ;
        RECT 1.935 784.170 1625.000 785.270 ;
        RECT -64.615 783.910 1625.000 784.170 ;
        RECT -64.615 782.130 -63.880 783.910 ;
        RECT 1.935 782.130 1625.000 783.910 ;
        RECT -64.615 781.870 1625.000 782.130 ;
        RECT -64.615 780.770 -63.880 781.870 ;
        RECT 1.935 780.770 1625.000 781.870 ;
        RECT -64.615 761.470 1625.000 780.770 ;
        RECT -64.615 760.370 -63.880 761.470 ;
        RECT 1.935 760.370 1625.000 761.470 ;
        RECT -64.615 760.110 1625.000 760.370 ;
        RECT -64.615 758.330 -63.880 760.110 ;
        RECT 1.935 758.330 1625.000 760.110 ;
        RECT -64.615 758.070 1625.000 758.330 ;
        RECT -64.615 756.970 -63.880 758.070 ;
        RECT 1.935 756.970 1625.000 758.070 ;
        RECT -64.615 737.670 1625.000 756.970 ;
        RECT -64.615 736.570 -63.880 737.670 ;
        RECT 1.935 736.570 1625.000 737.670 ;
        RECT -64.615 736.310 1625.000 736.570 ;
        RECT -64.615 734.530 -63.880 736.310 ;
        RECT 1.935 734.530 1625.000 736.310 ;
        RECT -64.615 734.270 1625.000 734.530 ;
        RECT -64.615 733.170 -63.880 734.270 ;
        RECT 1.935 733.170 1625.000 734.270 ;
        RECT -64.615 713.190 1625.000 733.170 ;
        RECT -64.615 711.410 -63.880 713.190 ;
        RECT 1.935 711.410 1625.000 713.190 ;
        RECT -64.615 711.150 1625.000 711.410 ;
        RECT -64.615 710.050 -63.880 711.150 ;
        RECT 1.935 710.050 1625.000 711.150 ;
        RECT -64.615 709.790 1625.000 710.050 ;
        RECT -64.615 708.690 -63.880 709.790 ;
        RECT 1.935 708.690 1625.000 709.790 ;
        RECT -64.615 689.390 1625.000 708.690 ;
        RECT -64.615 688.290 -63.880 689.390 ;
        RECT 1.935 688.290 1625.000 689.390 ;
        RECT -64.615 688.030 1625.000 688.290 ;
        RECT -64.615 686.250 -63.880 688.030 ;
        RECT 1.935 686.250 1625.000 688.030 ;
        RECT -64.615 685.990 1625.000 686.250 ;
        RECT -64.615 684.890 -63.880 685.990 ;
        RECT 1.935 684.890 1625.000 685.990 ;
        RECT -64.615 665.590 1625.000 684.890 ;
        RECT -64.615 664.490 -63.880 665.590 ;
        RECT 1.935 664.490 1625.000 665.590 ;
        RECT -64.615 664.230 1625.000 664.490 ;
        RECT -64.615 662.450 -63.880 664.230 ;
        RECT 1.935 662.450 1625.000 664.230 ;
        RECT -64.615 662.190 1625.000 662.450 ;
        RECT -64.615 661.090 -63.880 662.190 ;
        RECT 1.935 661.090 1625.000 662.190 ;
        RECT -64.615 641.110 1625.000 661.090 ;
        RECT -64.615 639.330 -63.880 641.110 ;
        RECT 1.935 639.330 1625.000 641.110 ;
        RECT -64.615 639.070 1625.000 639.330 ;
        RECT -64.615 637.290 -63.880 639.070 ;
        RECT 1.935 637.290 1625.000 639.070 ;
        RECT -64.615 617.310 1625.000 637.290 ;
        RECT -64.615 616.210 -63.880 617.310 ;
        RECT 1.935 616.210 1625.000 617.310 ;
        RECT -64.615 615.950 1625.000 616.210 ;
        RECT -64.615 614.170 -63.880 615.950 ;
        RECT 1.935 614.170 1625.000 615.950 ;
        RECT -64.615 613.910 1625.000 614.170 ;
        RECT -64.615 612.810 -63.880 613.910 ;
        RECT 1.935 612.810 1625.000 613.910 ;
        RECT -64.615 593.510 1625.000 612.810 ;
        RECT -64.615 592.410 -63.880 593.510 ;
        RECT 1.935 592.410 1625.000 593.510 ;
        RECT -64.615 592.150 1625.000 592.410 ;
        RECT -64.615 591.050 -63.880 592.150 ;
        RECT 1.935 591.050 1625.000 592.150 ;
        RECT -64.615 590.790 1625.000 591.050 ;
        RECT -64.615 589.010 -63.880 590.790 ;
        RECT 1.935 589.010 1625.000 590.790 ;
        RECT -64.615 569.710 1625.000 589.010 ;
        RECT -64.615 568.610 -63.880 569.710 ;
        RECT 1.935 568.610 1625.000 569.710 ;
        RECT -64.615 568.350 1625.000 568.610 ;
        RECT -64.615 567.250 -63.880 568.350 ;
        RECT 1.935 567.250 1625.000 568.350 ;
        RECT -64.615 566.990 1625.000 567.250 ;
        RECT -64.615 565.210 -63.880 566.990 ;
        RECT 1.935 565.210 1625.000 566.990 ;
        RECT -64.615 545.230 1625.000 565.210 ;
        RECT -64.615 543.450 -63.880 545.230 ;
        RECT 1.935 543.450 1625.000 545.230 ;
        RECT -64.615 543.190 1625.000 543.450 ;
        RECT -64.615 542.090 -63.880 543.190 ;
        RECT 1.935 542.090 1625.000 543.190 ;
        RECT -64.615 541.830 1625.000 542.090 ;
        RECT -64.615 540.730 -63.880 541.830 ;
        RECT 1.935 540.730 1625.000 541.830 ;
        RECT -64.615 521.430 1625.000 540.730 ;
        RECT -64.615 519.650 -63.880 521.430 ;
        RECT 1.935 519.650 1625.000 521.430 ;
        RECT -64.615 519.390 1625.000 519.650 ;
        RECT -64.615 518.290 -63.880 519.390 ;
        RECT 1.935 518.290 1625.000 519.390 ;
        RECT -64.615 518.030 1625.000 518.290 ;
        RECT -64.615 516.930 -63.880 518.030 ;
        RECT 1.935 516.930 1625.000 518.030 ;
        RECT -64.615 497.630 1625.000 516.930 ;
        RECT -64.615 496.530 -63.880 497.630 ;
        RECT 1.935 496.530 1625.000 497.630 ;
        RECT -64.615 496.270 1625.000 496.530 ;
        RECT -64.615 494.490 -63.880 496.270 ;
        RECT 1.935 494.490 1625.000 496.270 ;
        RECT -64.615 494.230 1625.000 494.490 ;
        RECT -64.615 493.130 -63.880 494.230 ;
        RECT 1.935 493.130 1625.000 494.230 ;
        RECT -64.615 473.150 1625.000 493.130 ;
        RECT -64.615 471.370 -63.880 473.150 ;
        RECT 1.935 471.370 1625.000 473.150 ;
        RECT -64.615 471.110 1625.000 471.370 ;
        RECT -64.615 469.330 -63.880 471.110 ;
        RECT 1.935 469.330 1625.000 471.110 ;
        RECT -64.615 449.350 1625.000 469.330 ;
        RECT -64.615 448.250 -63.880 449.350 ;
        RECT 1.935 448.250 1625.000 449.350 ;
        RECT -64.615 447.990 1625.000 448.250 ;
        RECT -64.615 446.210 -63.880 447.990 ;
        RECT 1.935 446.210 1625.000 447.990 ;
        RECT -64.615 445.950 1625.000 446.210 ;
        RECT -64.615 444.850 -63.880 445.950 ;
        RECT 1.935 444.850 1625.000 445.950 ;
        RECT -64.615 425.550 1625.000 444.850 ;
        RECT -64.615 424.450 -63.880 425.550 ;
        RECT 1.935 424.450 1625.000 425.550 ;
        RECT -64.615 424.190 1625.000 424.450 ;
        RECT -64.615 423.110 -63.880 424.190 ;
        RECT -64.615 422.810 -63.480 423.110 ;
        RECT -64.615 422.410 -63.880 422.810 ;
        RECT 1.935 422.410 1625.000 424.190 ;
        RECT -64.615 422.150 1625.000 422.410 ;
        RECT -64.615 421.050 -63.880 422.150 ;
        RECT 1.935 421.050 1625.000 422.150 ;
        RECT -64.615 401.070 1625.000 421.050 ;
        RECT -64.615 399.290 -63.880 401.070 ;
        RECT 1.935 399.290 1625.000 401.070 ;
        RECT -64.615 399.030 1625.000 399.290 ;
        RECT -64.615 397.250 -63.880 399.030 ;
        RECT 1.935 397.250 1625.000 399.030 ;
        RECT -64.615 377.270 1625.000 397.250 ;
        RECT -64.615 376.170 -63.880 377.270 ;
        RECT 1.935 376.170 1625.000 377.270 ;
        RECT -64.615 375.910 1625.000 376.170 ;
        RECT -64.615 374.130 -63.880 375.910 ;
        RECT 1.935 374.130 1625.000 375.910 ;
        RECT -64.615 373.870 1625.000 374.130 ;
        RECT -64.615 372.770 -63.880 373.870 ;
        RECT 1.935 372.770 1625.000 373.870 ;
        RECT -64.615 353.470 1625.000 372.770 ;
        RECT -64.615 352.370 -63.880 353.470 ;
        RECT 1.935 352.370 1625.000 353.470 ;
        RECT -64.615 352.110 1625.000 352.370 ;
        RECT -64.615 350.330 -63.880 352.110 ;
        RECT 1.935 350.330 1625.000 352.110 ;
        RECT -64.615 350.070 1625.000 350.330 ;
        RECT -64.615 348.970 -63.880 350.070 ;
        RECT 1.935 348.970 1625.000 350.070 ;
        RECT -64.615 329.670 1625.000 348.970 ;
        RECT -64.615 328.570 -63.880 329.670 ;
        RECT 1.935 328.570 1625.000 329.670 ;
        RECT -64.615 328.310 1625.000 328.570 ;
        RECT -64.615 326.530 -63.880 328.310 ;
        RECT 1.935 326.530 1625.000 328.310 ;
        RECT -64.615 326.270 1625.000 326.530 ;
        RECT -64.615 325.170 -63.880 326.270 ;
        RECT 1.935 325.170 1625.000 326.270 ;
        RECT -64.615 305.190 1625.000 325.170 ;
        RECT -64.615 303.410 -63.880 305.190 ;
        RECT 1.935 303.410 1625.000 305.190 ;
        RECT -64.615 303.150 1625.000 303.410 ;
        RECT -64.615 302.050 -63.880 303.150 ;
        RECT 1.935 302.050 1625.000 303.150 ;
        RECT -64.615 301.790 1625.000 302.050 ;
        RECT -64.615 300.690 -63.880 301.790 ;
        RECT 1.935 300.690 1625.000 301.790 ;
        RECT -64.615 281.390 1625.000 300.690 ;
        RECT -64.615 280.290 -63.880 281.390 ;
        RECT 1.935 280.290 1625.000 281.390 ;
        RECT -64.615 280.030 1625.000 280.290 ;
        RECT -64.615 278.250 -63.880 280.030 ;
        RECT 1.935 278.250 1625.000 280.030 ;
        RECT -64.615 277.990 1625.000 278.250 ;
        RECT -64.615 276.890 -63.880 277.990 ;
        RECT 1.935 276.890 1625.000 277.990 ;
        RECT -64.615 257.590 1625.000 276.890 ;
        RECT -64.615 256.490 -63.880 257.590 ;
        RECT 1.935 256.490 1625.000 257.590 ;
        RECT -64.615 256.230 1625.000 256.490 ;
        RECT -64.615 254.450 -63.880 256.230 ;
        RECT 1.935 254.450 1625.000 256.230 ;
        RECT -64.615 254.190 1625.000 254.450 ;
        RECT -64.615 253.090 -63.880 254.190 ;
        RECT 1.935 253.090 1625.000 254.190 ;
        RECT -64.615 233.110 1625.000 253.090 ;
        RECT -64.615 231.330 -63.880 233.110 ;
        RECT 1.935 231.330 1625.000 233.110 ;
        RECT -64.615 231.070 1625.000 231.330 ;
        RECT -64.615 229.290 -63.880 231.070 ;
        RECT 1.935 229.290 1625.000 231.070 ;
        RECT -64.615 209.310 1625.000 229.290 ;
        RECT -64.615 208.210 -63.880 209.310 ;
        RECT 1.935 208.210 1625.000 209.310 ;
        RECT -64.615 207.950 1625.000 208.210 ;
        RECT -64.615 206.170 -63.880 207.950 ;
        RECT 1.935 206.170 1625.000 207.950 ;
        RECT -64.615 205.910 1625.000 206.170 ;
        RECT -64.615 204.810 -63.880 205.910 ;
        RECT 1.935 204.810 1625.000 205.910 ;
        RECT -64.615 185.510 1625.000 204.810 ;
        RECT -64.615 184.410 -63.880 185.510 ;
        RECT 1.935 184.410 1625.000 185.510 ;
        RECT -64.615 184.150 1625.000 184.410 ;
        RECT -64.615 183.050 -63.880 184.150 ;
        RECT 1.935 183.050 1625.000 184.150 ;
        RECT -64.615 182.790 1625.000 183.050 ;
        RECT -64.615 181.010 -63.880 182.790 ;
        RECT 1.935 181.010 1625.000 182.790 ;
        RECT -64.615 161.710 1625.000 181.010 ;
        RECT -64.615 160.610 -63.880 161.710 ;
        RECT 1.935 160.610 1625.000 161.710 ;
        RECT -64.615 160.350 1625.000 160.610 ;
        RECT -64.615 159.250 -63.880 160.350 ;
        RECT 1.935 159.250 1625.000 160.350 ;
        RECT -64.615 158.990 1625.000 159.250 ;
        RECT -64.615 157.210 -63.880 158.990 ;
        RECT 1.935 157.210 1625.000 158.990 ;
        RECT -64.615 137.230 1625.000 157.210 ;
        RECT -64.615 135.450 -63.880 137.230 ;
        RECT 1.935 135.450 1625.000 137.230 ;
        RECT -64.615 135.190 1625.000 135.450 ;
        RECT -64.615 134.090 -63.880 135.190 ;
        RECT 1.935 134.090 1625.000 135.190 ;
        RECT -64.615 133.830 1625.000 134.090 ;
        RECT -64.615 132.730 -63.880 133.830 ;
        RECT 1.935 132.730 1625.000 133.830 ;
        RECT -64.615 113.430 1625.000 132.730 ;
        RECT -64.615 111.650 -63.880 113.430 ;
        RECT 1.935 111.650 1625.000 113.430 ;
        RECT -64.615 111.390 1625.000 111.650 ;
        RECT -64.615 110.290 -63.880 111.390 ;
        RECT 1.935 110.290 1625.000 111.390 ;
        RECT -64.615 110.030 1625.000 110.290 ;
        RECT -64.615 108.930 -63.880 110.030 ;
        RECT 1.935 108.930 1625.000 110.030 ;
        RECT -64.615 89.630 1625.000 108.930 ;
        RECT -64.615 88.530 -63.880 89.630 ;
        RECT 1.935 88.530 1625.000 89.630 ;
        RECT -64.615 88.270 1625.000 88.530 ;
        RECT -64.615 86.490 -63.880 88.270 ;
        RECT 1.935 86.490 1625.000 88.270 ;
        RECT -64.615 86.230 1625.000 86.490 ;
        RECT -64.615 85.130 -63.880 86.230 ;
        RECT 1.935 85.130 1625.000 86.230 ;
        RECT -64.615 65.150 1625.000 85.130 ;
        RECT -64.615 63.370 -63.880 65.150 ;
        RECT 1.935 63.370 1625.000 65.150 ;
        RECT -64.615 63.110 1625.000 63.370 ;
        RECT -64.615 61.330 -63.880 63.110 ;
        RECT 1.935 61.330 1625.000 63.110 ;
        RECT -64.615 40.465 1625.000 61.330 ;
        RECT -64.615 31.515 1594.600 40.465 ;
        RECT -64.615 29.355 -63.880 31.515 ;
        RECT 3.440 29.355 1594.600 31.515 ;
        RECT -64.615 19.985 1594.600 29.355 ;
        RECT -64.615 17.825 -63.880 19.985 ;
        RECT 3.440 17.825 1594.600 19.985 ;
        RECT -64.615 11.145 1594.600 17.825 ;
        RECT -64.615 8.985 -63.880 11.145 ;
        RECT 3.440 8.985 1594.600 11.145 ;
        RECT -64.615 -0.335 1594.600 8.985 ;
        RECT 1605.400 -0.335 1625.000 40.465 ;
        RECT -64.615 -35.330 1625.000 -0.335 ;
      LAYER met4 ;
        RECT 1.565 1638.040 2.820 1708.640 ;
        RECT 5.000 1638.040 5.120 1708.640 ;
        RECT 7.760 1638.040 21.620 1708.640 ;
        RECT 24.260 1638.040 24.380 1708.640 ;
        RECT 26.560 1638.040 26.820 1708.640 ;
        RECT 29.000 1638.040 29.120 1708.640 ;
        RECT 31.760 1638.040 45.620 1708.640 ;
        RECT 48.260 1638.040 48.380 1708.640 ;
        RECT 50.560 1638.040 50.820 1708.640 ;
        RECT 53.000 1638.040 53.120 1708.640 ;
        RECT 55.760 1638.040 69.620 1708.640 ;
        RECT 72.260 1638.040 72.380 1708.640 ;
        RECT 74.560 1638.040 74.820 1708.640 ;
        RECT 77.000 1638.040 77.120 1708.640 ;
        RECT 79.760 1638.040 93.620 1708.640 ;
        RECT 96.260 1638.040 96.380 1708.640 ;
        RECT 98.560 1638.040 98.820 1708.640 ;
        RECT 101.000 1638.040 101.120 1708.640 ;
        RECT 103.760 1638.040 117.620 1708.640 ;
        RECT 120.260 1638.040 120.380 1708.640 ;
        RECT 122.560 1638.040 122.820 1708.640 ;
        RECT 125.000 1638.040 125.120 1708.640 ;
        RECT 127.760 1638.040 141.620 1708.640 ;
        RECT 144.260 1638.040 144.380 1708.640 ;
        RECT 146.560 1638.040 146.820 1708.640 ;
        RECT 149.000 1638.040 149.120 1708.640 ;
        RECT 151.760 1638.040 165.620 1708.640 ;
        RECT 168.260 1638.040 168.380 1708.640 ;
        RECT 170.560 1638.040 170.820 1708.640 ;
        RECT 173.000 1638.040 173.120 1708.640 ;
        RECT 175.760 1638.040 189.620 1708.640 ;
        RECT 192.260 1638.040 192.380 1708.640 ;
        RECT 194.560 1638.040 194.820 1708.640 ;
        RECT 197.000 1638.040 197.120 1708.640 ;
        RECT 199.760 1638.040 213.620 1708.640 ;
        RECT 216.260 1638.040 216.380 1708.640 ;
        RECT 218.560 1638.040 218.820 1708.640 ;
        RECT 221.000 1638.040 221.120 1708.640 ;
        RECT 223.760 1638.040 237.620 1708.640 ;
        RECT 240.260 1638.040 240.380 1708.640 ;
        RECT 242.560 1638.040 242.820 1708.640 ;
        RECT 245.000 1638.040 245.120 1708.640 ;
        RECT 247.760 1638.040 261.620 1708.640 ;
        RECT 264.260 1638.040 264.380 1708.640 ;
        RECT 266.560 1638.040 266.820 1708.640 ;
        RECT 269.000 1638.040 269.120 1708.640 ;
        RECT 271.760 1638.040 285.620 1708.640 ;
        RECT 288.260 1638.040 288.380 1708.640 ;
        RECT 290.560 1638.040 290.820 1708.640 ;
        RECT 293.000 1638.040 293.120 1708.640 ;
        RECT 295.760 1638.040 309.620 1708.640 ;
        RECT 312.260 1638.040 312.380 1708.640 ;
        RECT 314.560 1638.040 314.820 1708.640 ;
        RECT 317.000 1638.040 317.120 1708.640 ;
        RECT 319.760 1638.040 333.620 1708.640 ;
        RECT 336.260 1638.040 336.380 1708.640 ;
        RECT 338.560 1638.040 338.820 1708.640 ;
        RECT 341.000 1638.040 341.120 1708.640 ;
        RECT 343.760 1638.040 357.620 1708.640 ;
        RECT 360.260 1638.040 360.380 1708.640 ;
        RECT 362.560 1638.040 362.820 1708.640 ;
        RECT 365.000 1638.040 365.120 1708.640 ;
        RECT 367.760 1638.040 381.620 1708.640 ;
        RECT 384.260 1638.040 384.380 1708.640 ;
        RECT 386.560 1638.040 386.820 1708.640 ;
        RECT 389.000 1638.040 389.120 1708.640 ;
        RECT 391.760 1638.040 405.620 1708.640 ;
        RECT 408.260 1638.040 408.380 1708.640 ;
        RECT 410.560 1638.040 410.820 1708.640 ;
        RECT 413.000 1638.040 413.120 1708.640 ;
        RECT 415.760 1638.040 429.620 1708.640 ;
        RECT 432.260 1638.040 432.380 1708.640 ;
        RECT 434.560 1638.040 434.820 1708.640 ;
        RECT 437.000 1638.040 437.120 1708.640 ;
        RECT 439.760 1638.040 453.620 1708.640 ;
        RECT 456.260 1638.040 456.380 1708.640 ;
        RECT 458.560 1638.040 458.820 1708.640 ;
        RECT 461.000 1638.040 461.120 1708.640 ;
        RECT 463.760 1638.040 477.620 1708.640 ;
        RECT 480.260 1638.040 480.380 1708.640 ;
        RECT 482.560 1638.040 482.820 1708.640 ;
        RECT 485.000 1638.040 485.120 1708.640 ;
        RECT 487.760 1638.040 501.620 1708.640 ;
        RECT 504.260 1638.040 504.380 1708.640 ;
        RECT 506.560 1638.040 506.820 1708.640 ;
        RECT 509.000 1638.040 509.120 1708.640 ;
        RECT 511.760 1638.040 525.620 1708.640 ;
        RECT 528.260 1638.040 528.380 1708.640 ;
        RECT 530.560 1638.040 530.820 1708.640 ;
        RECT 533.000 1638.040 533.120 1708.640 ;
        RECT 535.760 1638.040 549.620 1708.640 ;
        RECT 552.260 1638.040 552.380 1708.640 ;
        RECT 554.560 1638.040 554.820 1708.640 ;
        RECT 557.000 1638.040 557.120 1708.640 ;
        RECT 559.760 1638.040 573.620 1708.640 ;
        RECT 576.260 1638.040 576.380 1708.640 ;
        RECT 578.560 1638.040 578.820 1708.640 ;
        RECT 581.000 1638.040 581.120 1708.640 ;
        RECT 583.760 1638.040 597.620 1708.640 ;
        RECT 600.260 1638.040 600.380 1708.640 ;
        RECT 602.560 1638.040 602.820 1708.640 ;
        RECT 605.000 1638.040 605.120 1708.640 ;
        RECT 607.760 1638.040 621.620 1708.640 ;
        RECT 624.260 1638.040 624.380 1708.640 ;
        RECT 626.560 1638.040 626.820 1708.640 ;
        RECT 629.000 1638.040 629.120 1708.640 ;
        RECT 631.760 1638.040 645.620 1708.640 ;
        RECT 648.260 1638.040 648.380 1708.640 ;
        RECT 650.560 1638.040 650.820 1708.640 ;
        RECT 653.000 1638.040 653.120 1708.640 ;
        RECT 655.760 1638.040 669.620 1708.640 ;
        RECT 672.260 1638.040 672.380 1708.640 ;
        RECT 674.560 1638.040 674.820 1708.640 ;
        RECT 677.000 1638.040 677.120 1708.640 ;
        RECT 679.760 1638.040 693.620 1708.640 ;
        RECT 696.260 1638.040 696.380 1708.640 ;
        RECT 698.560 1638.040 698.820 1708.640 ;
        RECT 701.000 1638.040 701.120 1708.640 ;
        RECT 703.760 1638.040 717.620 1708.640 ;
        RECT 720.260 1638.040 720.380 1708.640 ;
        RECT 722.560 1638.040 722.820 1708.640 ;
        RECT 725.000 1638.040 725.120 1708.640 ;
        RECT 727.760 1638.040 741.620 1708.640 ;
        RECT 744.260 1638.040 744.380 1708.640 ;
        RECT 746.560 1638.040 746.820 1708.640 ;
        RECT 749.000 1638.040 749.120 1708.640 ;
        RECT 751.760 1638.040 765.620 1708.640 ;
        RECT 768.260 1638.040 768.380 1708.640 ;
        RECT 770.560 1638.040 770.820 1708.640 ;
        RECT 773.000 1638.040 773.120 1708.640 ;
        RECT 775.760 1638.040 789.620 1708.640 ;
        RECT 792.260 1638.040 792.380 1708.640 ;
        RECT 794.560 1638.040 794.820 1708.640 ;
        RECT 797.000 1638.040 797.120 1708.640 ;
        RECT 799.760 1638.040 813.620 1708.640 ;
        RECT 816.260 1638.040 816.380 1708.640 ;
        RECT 818.560 1638.040 818.820 1708.640 ;
        RECT 821.000 1638.040 821.120 1708.640 ;
        RECT 823.760 1638.040 837.620 1708.640 ;
        RECT 840.260 1638.040 840.380 1708.640 ;
        RECT 842.560 1638.040 842.820 1708.640 ;
        RECT 845.000 1638.040 845.120 1708.640 ;
        RECT 847.760 1638.040 861.620 1708.640 ;
        RECT 864.260 1638.040 864.380 1708.640 ;
        RECT 866.560 1638.040 866.820 1708.640 ;
        RECT 869.000 1638.040 869.120 1708.640 ;
        RECT 871.760 1638.040 885.620 1708.640 ;
        RECT 888.260 1638.040 888.380 1708.640 ;
        RECT 890.560 1638.040 890.820 1708.640 ;
        RECT 893.000 1638.040 893.120 1708.640 ;
        RECT 895.760 1638.040 909.620 1708.640 ;
        RECT 912.260 1638.040 912.380 1708.640 ;
        RECT 914.560 1638.040 914.820 1708.640 ;
        RECT 917.000 1638.040 917.120 1708.640 ;
        RECT 919.760 1638.040 933.620 1708.640 ;
        RECT 936.260 1638.040 936.380 1708.640 ;
        RECT 938.560 1638.040 938.820 1708.640 ;
        RECT 941.000 1638.040 941.120 1708.640 ;
        RECT 943.760 1638.040 957.620 1708.640 ;
        RECT 960.260 1638.040 960.380 1708.640 ;
        RECT 962.560 1638.040 962.820 1708.640 ;
        RECT 965.000 1638.040 965.120 1708.640 ;
        RECT 967.760 1638.040 981.620 1708.640 ;
        RECT 984.260 1638.040 984.380 1708.640 ;
        RECT 986.560 1638.040 986.820 1708.640 ;
        RECT 989.000 1638.040 989.120 1708.640 ;
        RECT 991.760 1638.040 1005.620 1708.640 ;
        RECT 1008.260 1638.040 1008.380 1708.640 ;
        RECT 1010.560 1638.040 1010.820 1708.640 ;
        RECT 1013.000 1638.040 1013.120 1708.640 ;
        RECT 1015.760 1638.040 1029.620 1708.640 ;
        RECT 1032.260 1638.040 1032.380 1708.640 ;
        RECT 1034.560 1638.040 1034.820 1708.640 ;
        RECT 1037.000 1638.040 1037.120 1708.640 ;
        RECT 1039.760 1638.040 1053.620 1708.640 ;
        RECT 1056.260 1638.040 1056.380 1708.640 ;
        RECT 1058.560 1638.040 1058.820 1708.640 ;
        RECT 1061.000 1638.040 1061.120 1708.640 ;
        RECT 1063.760 1638.040 1077.620 1708.640 ;
        RECT 1080.260 1638.040 1080.380 1708.640 ;
        RECT 1082.560 1638.040 1082.820 1708.640 ;
        RECT 1085.000 1638.040 1085.120 1708.640 ;
        RECT 1087.760 1638.040 1101.620 1708.640 ;
        RECT 1104.260 1638.040 1104.380 1708.640 ;
        RECT 1106.560 1638.040 1106.820 1708.640 ;
        RECT 1109.000 1638.040 1109.120 1708.640 ;
        RECT 1111.760 1638.040 1125.620 1708.640 ;
        RECT 1128.260 1638.040 1128.380 1708.640 ;
        RECT 1130.560 1638.040 1130.820 1708.640 ;
        RECT 1133.000 1638.040 1133.120 1708.640 ;
        RECT 1135.760 1638.040 1149.620 1708.640 ;
        RECT 1152.260 1638.040 1152.380 1708.640 ;
        RECT 1154.560 1638.040 1154.820 1708.640 ;
        RECT 1157.000 1638.040 1157.120 1708.640 ;
        RECT 1159.760 1638.040 1173.620 1708.640 ;
        RECT 1176.260 1638.040 1176.380 1708.640 ;
        RECT 1178.560 1638.040 1178.820 1708.640 ;
        RECT 1181.000 1638.040 1181.120 1708.640 ;
        RECT 1183.760 1638.040 1197.620 1708.640 ;
        RECT 1200.260 1638.040 1200.380 1708.640 ;
        RECT 1202.560 1638.040 1202.820 1708.640 ;
        RECT 1205.000 1638.040 1205.120 1708.640 ;
        RECT 1207.760 1638.040 1221.620 1708.640 ;
        RECT 1224.260 1638.040 1224.380 1708.640 ;
        RECT 1226.560 1638.040 1226.820 1708.640 ;
        RECT 1229.000 1638.040 1229.120 1708.640 ;
        RECT 1231.760 1638.040 1245.620 1708.640 ;
        RECT 1248.260 1638.040 1248.380 1708.640 ;
        RECT 1250.560 1638.040 1250.820 1708.640 ;
        RECT 1253.000 1638.040 1253.120 1708.640 ;
        RECT 1255.760 1638.040 1269.965 1708.640 ;
        RECT 1274.560 1638.040 1274.820 1708.640 ;
        RECT 1277.000 1638.040 1277.120 1708.640 ;
        RECT 1279.760 1638.040 1293.620 1708.640 ;
        RECT 1296.260 1638.040 1296.380 1708.640 ;
        RECT 1298.560 1638.040 1298.820 1708.640 ;
        RECT 1301.000 1638.040 1301.120 1708.640 ;
        RECT 1303.760 1638.040 1317.620 1708.640 ;
        RECT 1320.260 1638.040 1320.380 1708.640 ;
        RECT 1322.560 1638.040 1322.820 1708.640 ;
        RECT 1325.000 1638.040 1325.120 1708.640 ;
        RECT 1327.760 1638.040 1341.620 1708.640 ;
        RECT 1344.260 1638.040 1344.380 1708.640 ;
        RECT 1346.560 1638.040 1346.820 1708.640 ;
        RECT 1349.000 1638.040 1349.120 1708.640 ;
        RECT 1351.760 1638.040 1365.620 1708.640 ;
        RECT 1368.260 1638.040 1368.380 1708.640 ;
        RECT 1370.560 1638.040 1370.820 1708.640 ;
        RECT 1373.000 1638.040 1373.120 1708.640 ;
        RECT 1375.760 1638.040 1389.620 1708.640 ;
        RECT 1392.260 1638.040 1392.380 1708.640 ;
        RECT 1394.560 1638.040 1394.820 1708.640 ;
        RECT 1397.000 1638.040 1397.120 1708.640 ;
        RECT 1399.760 1638.040 1413.620 1708.640 ;
        RECT 1416.260 1638.040 1416.380 1708.640 ;
        RECT 1418.560 1638.040 1418.820 1708.640 ;
        RECT 1421.000 1638.040 1421.120 1708.640 ;
        RECT 1423.760 1638.040 1437.620 1708.640 ;
        RECT 1440.260 1638.040 1440.380 1708.640 ;
        RECT 1442.560 1638.040 1442.820 1708.640 ;
        RECT 1445.000 1638.040 1445.120 1708.640 ;
        RECT 1447.760 1638.040 1461.620 1708.640 ;
        RECT 1464.260 1638.040 1464.380 1708.640 ;
        RECT 1466.560 1638.040 1466.820 1708.640 ;
        RECT 1469.000 1638.040 1469.120 1708.640 ;
        RECT 1471.760 1638.040 1485.620 1708.640 ;
        RECT 1488.260 1638.040 1488.380 1708.640 ;
        RECT 1490.560 1638.040 1490.820 1708.640 ;
        RECT 1493.000 1638.040 1493.120 1708.640 ;
        RECT 1495.760 1638.040 1509.620 1708.640 ;
        RECT 1512.260 1638.040 1512.380 1708.640 ;
        RECT 1514.560 1638.040 1514.820 1708.640 ;
        RECT 1517.000 1638.040 1517.120 1708.640 ;
        RECT 1519.760 1638.040 1533.620 1708.640 ;
        RECT 1536.260 1638.040 1536.380 1708.640 ;
        RECT 1538.560 1638.040 1539.815 1708.640 ;
        RECT 1.565 52.450 1539.815 1638.040 ;
        RECT 1.565 49.990 368.395 52.450 ;
        RECT 380.985 49.990 1539.815 52.450 ;
        RECT 1.565 0.775 1539.815 49.990 ;
        RECT 1.565 -70.200 2.820 0.775 ;
        RECT 5.000 -70.200 5.120 0.775 ;
        RECT 7.760 -70.200 21.620 0.775 ;
        RECT 24.260 -70.200 24.380 0.775 ;
        RECT 26.560 -70.200 26.820 0.775 ;
        RECT 29.000 -70.200 29.120 0.775 ;
        RECT 31.760 -70.200 45.620 0.775 ;
        RECT 48.260 -70.200 48.380 0.775 ;
        RECT 50.560 -70.200 50.820 0.775 ;
        RECT 53.000 -70.200 53.120 0.775 ;
        RECT 55.760 -70.200 69.620 0.775 ;
        RECT 72.260 -70.200 72.380 0.775 ;
        RECT 74.560 -70.200 74.820 0.775 ;
        RECT 77.000 -70.200 77.120 0.775 ;
        RECT 79.760 -70.200 93.620 0.775 ;
        RECT 96.260 -70.200 96.380 0.775 ;
        RECT 98.560 -70.200 98.820 0.775 ;
        RECT 101.000 -70.200 101.120 0.775 ;
        RECT 103.760 -70.200 117.620 0.775 ;
        RECT 120.260 -70.200 120.380 0.775 ;
        RECT 122.560 -70.200 122.820 0.775 ;
        RECT 125.000 -70.200 125.120 0.775 ;
        RECT 127.760 -70.200 141.620 0.775 ;
        RECT 144.260 -70.200 144.380 0.775 ;
        RECT 146.560 -70.200 146.820 0.775 ;
        RECT 149.000 -70.200 149.120 0.775 ;
        RECT 151.760 -70.200 165.620 0.775 ;
        RECT 168.260 -70.200 168.380 0.775 ;
        RECT 170.560 -70.200 170.820 0.775 ;
        RECT 173.000 -70.200 173.120 0.775 ;
        RECT 175.760 -70.200 189.620 0.775 ;
        RECT 192.260 -70.200 192.380 0.775 ;
        RECT 194.560 -70.200 194.820 0.775 ;
        RECT 197.000 -70.200 197.120 0.775 ;
        RECT 199.760 -70.200 213.620 0.775 ;
        RECT 216.260 -70.200 216.380 0.775 ;
        RECT 218.560 -70.200 218.820 0.775 ;
        RECT 221.000 -70.200 221.120 0.775 ;
        RECT 223.760 -70.200 237.620 0.775 ;
        RECT 240.260 -70.200 240.380 0.775 ;
        RECT 242.560 -70.200 242.820 0.775 ;
        RECT 245.000 -70.200 245.120 0.775 ;
        RECT 247.760 -70.200 261.620 0.775 ;
        RECT 264.260 -70.200 264.380 0.775 ;
        RECT 266.560 -70.200 266.820 0.775 ;
        RECT 269.000 -70.200 269.120 0.775 ;
        RECT 271.760 -70.200 285.620 0.775 ;
        RECT 288.260 -70.200 288.380 0.775 ;
        RECT 290.560 -70.200 290.820 0.775 ;
        RECT 293.000 -70.200 293.120 0.775 ;
        RECT 295.760 -70.200 309.620 0.775 ;
        RECT 312.260 -70.200 312.380 0.775 ;
        RECT 314.560 -70.200 314.820 0.775 ;
        RECT 317.000 -70.200 317.120 0.775 ;
        RECT 319.760 -70.200 333.620 0.775 ;
        RECT 336.260 -70.200 336.380 0.775 ;
        RECT 338.560 -70.200 338.820 0.775 ;
        RECT 341.000 -70.200 341.120 0.775 ;
        RECT 343.760 -70.200 357.620 0.775 ;
        RECT 360.260 -70.200 360.380 0.775 ;
        RECT 362.560 -70.200 362.820 0.775 ;
        RECT 365.000 -70.200 365.120 0.775 ;
        RECT 367.760 -70.200 381.620 0.775 ;
        RECT 384.260 -70.200 384.380 0.775 ;
        RECT 386.560 -70.200 386.820 0.775 ;
        RECT 389.000 -70.200 389.120 0.775 ;
        RECT 391.760 -70.200 405.620 0.775 ;
        RECT 408.260 -70.200 408.380 0.775 ;
        RECT 410.560 -70.200 410.820 0.775 ;
        RECT 413.000 -70.200 413.120 0.775 ;
        RECT 415.760 -70.200 429.620 0.775 ;
        RECT 432.260 -70.200 432.380 0.775 ;
        RECT 434.560 -70.200 434.820 0.775 ;
        RECT 437.000 -70.200 437.120 0.775 ;
        RECT 439.760 -70.200 453.620 0.775 ;
        RECT 456.260 -70.200 456.380 0.775 ;
        RECT 458.560 -70.200 458.820 0.775 ;
        RECT 461.000 -70.200 461.120 0.775 ;
        RECT 463.760 -70.200 477.620 0.775 ;
        RECT 480.260 -70.200 480.380 0.775 ;
        RECT 482.560 -70.200 482.820 0.775 ;
        RECT 485.000 -70.200 485.120 0.775 ;
        RECT 487.760 -70.200 501.620 0.775 ;
        RECT 504.260 -70.200 504.380 0.775 ;
        RECT 506.560 -70.200 506.820 0.775 ;
        RECT 509.000 -70.200 509.120 0.775 ;
        RECT 511.760 -70.200 525.620 0.775 ;
        RECT 528.260 -70.200 528.380 0.775 ;
        RECT 530.560 -70.200 530.820 0.775 ;
        RECT 533.000 -70.200 533.120 0.775 ;
        RECT 535.760 -70.200 549.620 0.775 ;
        RECT 552.260 -70.200 552.380 0.775 ;
        RECT 554.560 -70.200 554.820 0.775 ;
        RECT 557.000 -70.200 557.120 0.775 ;
        RECT 559.760 -70.200 573.620 0.775 ;
        RECT 576.260 -70.200 576.380 0.775 ;
        RECT 578.560 -70.200 578.820 0.775 ;
        RECT 581.000 -70.200 581.120 0.775 ;
        RECT 583.760 -70.200 597.620 0.775 ;
        RECT 600.260 -70.200 600.380 0.775 ;
        RECT 602.560 -70.200 602.820 0.775 ;
        RECT 605.000 -70.200 605.120 0.775 ;
        RECT 607.760 -70.200 621.620 0.775 ;
        RECT 624.260 -70.200 624.380 0.775 ;
        RECT 626.560 -70.200 626.820 0.775 ;
        RECT 629.000 -70.200 629.120 0.775 ;
        RECT 631.760 -70.200 645.620 0.775 ;
        RECT 648.260 -70.200 648.380 0.775 ;
        RECT 650.560 -70.200 650.820 0.775 ;
        RECT 653.000 -70.200 653.120 0.775 ;
        RECT 655.760 -70.200 669.620 0.775 ;
        RECT 672.260 -70.200 672.380 0.775 ;
        RECT 674.560 -70.200 674.820 0.775 ;
        RECT 677.000 -70.200 677.120 0.775 ;
        RECT 679.760 -70.200 693.620 0.775 ;
        RECT 696.260 -70.200 696.380 0.775 ;
        RECT 698.560 -70.200 698.820 0.775 ;
        RECT 701.000 -70.200 701.120 0.775 ;
        RECT 703.760 -70.200 717.620 0.775 ;
        RECT 720.260 -70.200 720.380 0.775 ;
        RECT 722.560 -70.200 722.820 0.775 ;
        RECT 725.000 -70.200 725.120 0.775 ;
        RECT 727.760 -70.200 741.620 0.775 ;
        RECT 744.260 -70.200 744.380 0.775 ;
        RECT 746.560 -70.200 746.820 0.775 ;
        RECT 749.000 -70.200 749.120 0.775 ;
        RECT 751.760 -70.200 765.620 0.775 ;
        RECT 768.260 -70.200 768.380 0.775 ;
        RECT 770.560 -70.200 770.820 0.775 ;
        RECT 773.000 -70.200 773.120 0.775 ;
        RECT 775.760 -70.200 789.620 0.775 ;
        RECT 792.260 -70.200 792.380 0.775 ;
        RECT 794.560 -70.200 794.820 0.775 ;
        RECT 797.000 -70.200 797.120 0.775 ;
        RECT 799.760 -70.200 813.620 0.775 ;
        RECT 816.260 -70.200 816.850 0.775 ;
        RECT 821.000 -70.200 821.120 0.775 ;
        RECT 823.760 -70.200 837.620 0.775 ;
        RECT 840.260 -70.200 840.380 0.775 ;
        RECT 842.560 -70.200 842.820 0.775 ;
        RECT 845.000 -70.200 845.120 0.775 ;
        RECT 847.760 -70.200 861.620 0.775 ;
        RECT 864.260 -70.200 864.380 0.775 ;
        RECT 866.560 -70.200 866.820 0.775 ;
        RECT 869.000 -70.200 869.120 0.775 ;
        RECT 871.760 -70.200 885.620 0.775 ;
        RECT 888.260 -70.200 888.380 0.775 ;
        RECT 890.560 -70.200 890.820 0.775 ;
        RECT 893.000 -70.200 893.120 0.775 ;
        RECT 895.760 -70.200 909.620 0.775 ;
        RECT 912.260 -70.200 912.380 0.775 ;
        RECT 914.560 -70.200 914.820 0.775 ;
        RECT 917.000 -70.200 917.120 0.775 ;
        RECT 919.760 -70.200 933.620 0.775 ;
        RECT 936.260 -70.200 936.380 0.775 ;
        RECT 938.560 -70.200 938.820 0.775 ;
        RECT 941.000 -70.200 941.120 0.775 ;
        RECT 943.760 -70.200 957.620 0.775 ;
        RECT 960.260 -70.200 960.380 0.775 ;
        RECT 962.560 -70.200 962.820 0.775 ;
        RECT 965.000 -70.200 965.120 0.775 ;
        RECT 967.760 -70.200 981.620 0.775 ;
        RECT 984.260 -70.200 984.380 0.775 ;
        RECT 986.560 -70.200 986.820 0.775 ;
        RECT 989.000 -70.200 989.120 0.775 ;
        RECT 991.760 -70.200 1005.620 0.775 ;
        RECT 1008.260 -70.200 1008.380 0.775 ;
        RECT 1010.560 -70.200 1010.820 0.775 ;
        RECT 1013.000 -70.200 1013.120 0.775 ;
        RECT 1015.760 -70.200 1029.620 0.775 ;
        RECT 1032.260 -70.200 1032.380 0.775 ;
        RECT 1034.560 -70.200 1034.820 0.775 ;
        RECT 1037.000 -70.200 1037.120 0.775 ;
        RECT 1039.760 -70.200 1053.620 0.775 ;
        RECT 1056.260 -70.200 1056.380 0.775 ;
        RECT 1058.560 -70.200 1058.820 0.775 ;
        RECT 1061.000 -70.200 1061.120 0.775 ;
        RECT 1063.760 -70.200 1077.620 0.775 ;
        RECT 1080.260 -70.200 1080.380 0.775 ;
        RECT 1082.560 -70.200 1082.820 0.775 ;
        RECT 1085.000 -70.200 1085.120 0.775 ;
        RECT 1087.760 -70.200 1101.620 0.775 ;
        RECT 1104.260 -70.200 1104.380 0.775 ;
        RECT 1106.560 -70.200 1106.820 0.775 ;
        RECT 1109.000 -70.200 1109.120 0.775 ;
        RECT 1111.760 -70.200 1125.620 0.775 ;
        RECT 1128.260 -70.200 1128.380 0.775 ;
        RECT 1130.560 -70.200 1130.820 0.775 ;
        RECT 1133.000 -70.200 1133.120 0.775 ;
        RECT 1135.760 -70.200 1149.620 0.775 ;
        RECT 1152.260 -70.200 1152.380 0.775 ;
        RECT 1154.560 -70.200 1154.820 0.775 ;
        RECT 1157.000 -70.200 1157.120 0.775 ;
        RECT 1159.760 -70.200 1173.620 0.775 ;
        RECT 1176.260 -70.200 1176.380 0.775 ;
        RECT 1178.560 -70.200 1178.820 0.775 ;
        RECT 1181.000 -70.200 1181.120 0.775 ;
        RECT 1183.760 -70.200 1197.620 0.775 ;
        RECT 1200.260 -70.200 1200.380 0.775 ;
        RECT 1202.560 -70.200 1202.820 0.775 ;
        RECT 1205.000 -70.200 1205.120 0.775 ;
        RECT 1207.760 -70.200 1221.620 0.775 ;
        RECT 1224.260 -70.200 1224.380 0.775 ;
        RECT 1226.560 -70.200 1226.820 0.775 ;
        RECT 1229.000 -70.200 1229.120 0.775 ;
        RECT 1231.760 -70.200 1245.620 0.775 ;
        RECT 1248.260 -70.200 1248.380 0.775 ;
        RECT 1250.560 -70.200 1250.820 0.775 ;
        RECT 1253.000 -70.200 1253.120 0.775 ;
        RECT 1255.760 -70.200 1269.620 0.775 ;
        RECT 1272.260 -70.200 1272.380 0.775 ;
        RECT 1274.560 -70.200 1274.820 0.775 ;
        RECT 1277.000 -70.200 1277.120 0.775 ;
        RECT 1279.760 -70.200 1293.620 0.775 ;
        RECT 1296.260 -70.200 1296.380 0.775 ;
        RECT 1298.560 -70.200 1298.820 0.775 ;
        RECT 1301.000 -70.200 1301.120 0.775 ;
        RECT 1303.760 -70.200 1317.620 0.775 ;
        RECT 1320.260 -70.200 1320.380 0.775 ;
        RECT 1322.560 -70.200 1322.820 0.775 ;
        RECT 1325.000 -70.200 1325.120 0.775 ;
        RECT 1327.760 -70.200 1341.620 0.775 ;
        RECT 1344.260 -70.200 1344.380 0.775 ;
        RECT 1346.560 -70.200 1346.820 0.775 ;
        RECT 1349.000 -70.200 1349.120 0.775 ;
        RECT 1351.760 -70.200 1365.620 0.775 ;
        RECT 1368.260 -70.200 1368.380 0.775 ;
        RECT 1370.560 -70.200 1370.820 0.775 ;
        RECT 1373.000 -70.200 1373.120 0.775 ;
        RECT 1375.760 -70.200 1389.620 0.775 ;
        RECT 1392.260 -70.200 1392.380 0.775 ;
        RECT 1394.560 -70.200 1394.820 0.775 ;
        RECT 1397.000 -70.200 1397.120 0.775 ;
        RECT 1399.760 -70.200 1413.620 0.775 ;
        RECT 1416.260 -70.200 1416.380 0.775 ;
        RECT 1418.560 -70.200 1418.820 0.775 ;
        RECT 1421.000 -70.200 1421.120 0.775 ;
        RECT 1423.760 -70.200 1437.620 0.775 ;
        RECT 1440.260 -70.200 1440.380 0.775 ;
        RECT 1442.560 -70.200 1442.820 0.775 ;
        RECT 1445.000 -70.200 1445.120 0.775 ;
        RECT 1447.760 -70.200 1461.620 0.775 ;
        RECT 1464.260 -70.200 1464.380 0.775 ;
        RECT 1466.560 -70.200 1466.820 0.775 ;
        RECT 1469.000 -70.200 1469.120 0.775 ;
        RECT 1471.760 -70.200 1485.620 0.775 ;
        RECT 1488.260 -70.200 1488.380 0.775 ;
        RECT 1490.560 -70.200 1490.820 0.775 ;
        RECT 1493.000 -70.200 1493.120 0.775 ;
        RECT 1495.760 -70.200 1509.620 0.775 ;
        RECT 1512.260 -70.200 1512.380 0.775 ;
        RECT 1514.560 -70.200 1514.820 0.775 ;
        RECT 1517.000 -70.200 1517.120 0.775 ;
        RECT 1519.760 -70.200 1533.620 0.775 ;
        RECT 1536.260 -70.200 1536.380 0.775 ;
        RECT 1538.560 -70.200 1539.815 0.775 ;
      LAYER met5 ;
        RECT 0.000 0.475 1541.380 1637.965 ;
  END
END pixel_4tile
END LIBRARY

